VERSION 5.8 ;
BUSBITCHARS "[]" ;
DIVIDERCHAR "/" ;
UNITS
    DATABASE MICRONS 1000 ;
END UNITS

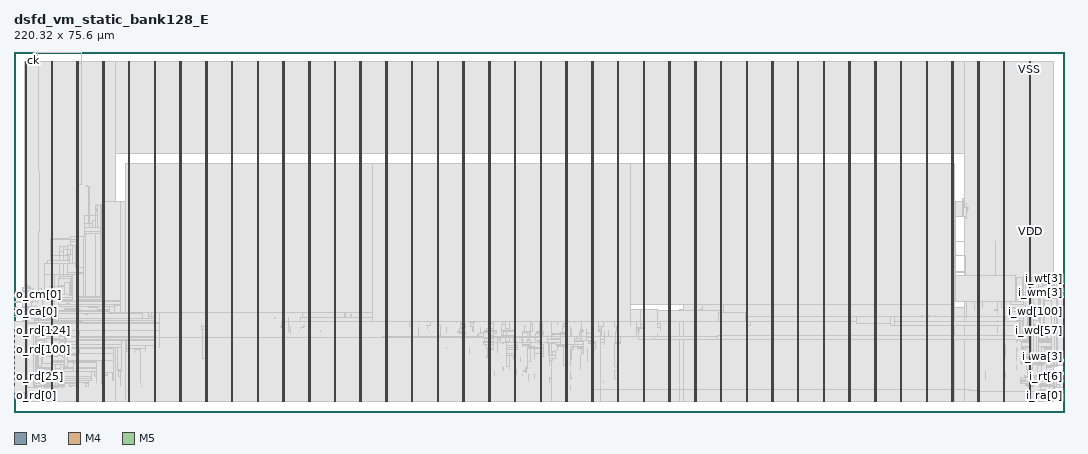
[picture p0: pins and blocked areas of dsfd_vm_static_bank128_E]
MACRO dsfd_vm_static_bank128_E
  FOREIGN dsfd_vm_static_bank128_E 0 0 ;
  CLASS BLOCK ;
  SIZE 220.32 BY 75.6 ;
  PIN ck
    DIRECTION INPUT ;
    USE SIGNAL ;
    PORT
      LAYER M3 ;
        RECT  4.032 75.562 4.05 75.6 ;
    END
  END ck
  PIN i_ra[0]
    DIRECTION INPUT ;
    USE SIGNAL ;
    PORT
      LAYER M4 ;
        RECT  220.236 5.088 220.32 5.112 ;
    END
  END i_ra[0]
  PIN i_ra[1]
    DIRECTION INPUT ;
    USE SIGNAL ;
    PORT
      LAYER M4 ;
        RECT  220.236 5.184 220.32 5.208 ;
    END
  END i_ra[1]
  PIN i_ra[2]
    DIRECTION INPUT ;
    USE SIGNAL ;
    PORT
      LAYER M4 ;
        RECT  220.236 5.28 220.32 5.304 ;
    END
  END i_ra[2]
  PIN i_ra[3]
    DIRECTION INPUT ;
    USE SIGNAL ;
    PORT
      LAYER M4 ;
        RECT  220.236 5.376 220.32 5.4 ;
    END
  END i_ra[3]
  PIN i_ra[4]
    DIRECTION INPUT ;
    USE SIGNAL ;
    PORT
      LAYER M4 ;
        RECT  220.236 5.472 220.32 5.496 ;
    END
  END i_ra[4]
  PIN i_ra[5]
    DIRECTION INPUT ;
    USE SIGNAL ;
    PORT
      LAYER M4 ;
        RECT  220.236 5.568 220.32 5.592 ;
    END
  END i_ra[5]
  PIN i_ra[6]
    DIRECTION INPUT ;
    USE SIGNAL ;
    PORT
      LAYER M4 ;
        RECT  220.236 5.664 220.32 5.688 ;
    END
  END i_ra[6]
  PIN i_ra[7]
    DIRECTION INPUT ;
    USE SIGNAL ;
    PORT
      LAYER M4 ;
        RECT  220.236 5.76 220.32 5.784 ;
    END
  END i_ra[7]
  PIN i_ra[8]
    DIRECTION INPUT ;
    USE SIGNAL ;
    PORT
      LAYER M4 ;
        RECT  220.236 5.856 220.32 5.88 ;
    END
  END i_ra[8]
  PIN i_rt[0]
    DIRECTION INPUT ;
    USE SIGNAL ;
    PORT
      LAYER M4 ;
        RECT  220.236 6.912 220.32 6.936 ;
    END
  END i_rt[0]
  PIN i_rt[1]
    DIRECTION INPUT ;
    USE SIGNAL ;
    PORT
      LAYER M4 ;
        RECT  220.236 7.008 220.32 7.032 ;
    END
  END i_rt[1]
  PIN i_rt[2]
    DIRECTION INPUT ;
    USE SIGNAL ;
    PORT
      LAYER M4 ;
        RECT  220.236 7.104 220.32 7.128 ;
    END
  END i_rt[2]
  PIN i_rt[3]
    DIRECTION INPUT ;
    USE SIGNAL ;
    PORT
      LAYER M4 ;
        RECT  220.236 7.2 220.32 7.224 ;
    END
  END i_rt[3]
  PIN i_rt[4]
    DIRECTION INPUT ;
    USE SIGNAL ;
    PORT
      LAYER M4 ;
        RECT  220.236 7.296 220.32 7.32 ;
    END
  END i_rt[4]
  PIN i_rt[5]
    DIRECTION INPUT ;
    USE SIGNAL ;
    PORT
      LAYER M4 ;
        RECT  220.236 7.392 220.32 7.416 ;
    END
  END i_rt[5]
  PIN i_rt[6]
    DIRECTION INPUT ;
    USE SIGNAL ;
    PORT
      LAYER M4 ;
        RECT  220.236 7.488 220.32 7.512 ;
    END
  END i_rt[6]
  PIN i_rt[7]
    DIRECTION INPUT ;
    USE SIGNAL ;
    PORT
      LAYER M4 ;
        RECT  220.236 7.584 220.32 7.608 ;
    END
  END i_rt[7]
  PIN i_rv
    DIRECTION INPUT ;
    USE SIGNAL ;
    PORT
      LAYER M4 ;
        RECT  220.236 4.032 220.32 4.056 ;
    END
  END i_rv
  PIN i_wa[0]
    DIRECTION INPUT ;
    USE SIGNAL ;
    PORT
      LAYER M4 ;
        RECT  220.236 9.696 220.32 9.72 ;
    END
  END i_wa[0]
  PIN i_wa[1]
    DIRECTION INPUT ;
    USE SIGNAL ;
    PORT
      LAYER M4 ;
        RECT  220.236 9.792 220.32 9.816 ;
    END
  END i_wa[1]
  PIN i_wa[2]
    DIRECTION INPUT ;
    USE SIGNAL ;
    PORT
      LAYER M4 ;
        RECT  220.236 9.888 220.32 9.912 ;
    END
  END i_wa[2]
  PIN i_wa[3]
    DIRECTION INPUT ;
    USE SIGNAL ;
    PORT
      LAYER M4 ;
        RECT  220.236 9.984 220.32 10.008 ;
    END
  END i_wa[3]
  PIN i_wa[4]
    DIRECTION INPUT ;
    USE SIGNAL ;
    PORT
      LAYER M4 ;
        RECT  220.236 10.08 220.32 10.104 ;
    END
  END i_wa[4]
  PIN i_wa[5]
    DIRECTION INPUT ;
    USE SIGNAL ;
    PORT
      LAYER M4 ;
        RECT  220.236 10.176 220.32 10.2 ;
    END
  END i_wa[5]
  PIN i_wa[6]
    DIRECTION INPUT ;
    USE SIGNAL ;
    PORT
      LAYER M4 ;
        RECT  220.236 10.272 220.32 10.296 ;
    END
  END i_wa[6]
  PIN i_wa[7]
    DIRECTION INPUT ;
    USE SIGNAL ;
    PORT
      LAYER M4 ;
        RECT  220.236 10.368 220.32 10.392 ;
    END
  END i_wa[7]
  PIN i_wa[8]
    DIRECTION INPUT ;
    USE SIGNAL ;
    PORT
      LAYER M4 ;
        RECT  220.236 10.464 220.32 10.488 ;
    END
  END i_wa[8]
  PIN i_wd[0]
    DIRECTION INPUT ;
    USE SIGNAL ;
    PORT
      LAYER M4 ;
        RECT  220.236 11.52 220.32 11.544 ;
    END
  END i_wd[0]
  PIN i_wd[100]
    DIRECTION INPUT ;
    USE SIGNAL ;
    PORT
      LAYER M4 ;
        RECT  220.236 21.12 220.32 21.144 ;
    END
  END i_wd[100]
  PIN i_wd[101]
    DIRECTION INPUT ;
    USE SIGNAL ;
    PORT
      LAYER M4 ;
        RECT  220.236 21.216 220.32 21.24 ;
    END
  END i_wd[101]
  PIN i_wd[102]
    DIRECTION INPUT ;
    USE SIGNAL ;
    PORT
      LAYER M4 ;
        RECT  220.236 21.312 220.32 21.336 ;
    END
  END i_wd[102]
  PIN i_wd[103]
    DIRECTION INPUT ;
    USE SIGNAL ;
    PORT
      LAYER M4 ;
        RECT  220.236 21.408 220.32 21.432 ;
    END
  END i_wd[103]
  PIN i_wd[104]
    DIRECTION INPUT ;
    USE SIGNAL ;
    PORT
      LAYER M4 ;
        RECT  220.236 21.504 220.32 21.528 ;
    END
  END i_wd[104]
  PIN i_wd[105]
    DIRECTION INPUT ;
    USE SIGNAL ;
    PORT
      LAYER M4 ;
        RECT  220.236 21.6 220.32 21.624 ;
    END
  END i_wd[105]
  PIN i_wd[106]
    DIRECTION INPUT ;
    USE SIGNAL ;
    PORT
      LAYER M4 ;
        RECT  220.236 21.696 220.32 21.72 ;
    END
  END i_wd[106]
  PIN i_wd[107]
    DIRECTION INPUT ;
    USE SIGNAL ;
    PORT
      LAYER M4 ;
        RECT  220.236 21.792 220.32 21.816 ;
    END
  END i_wd[107]
  PIN i_wd[108]
    DIRECTION INPUT ;
    USE SIGNAL ;
    PORT
      LAYER M4 ;
        RECT  220.236 21.888 220.32 21.912 ;
    END
  END i_wd[108]
  PIN i_wd[109]
    DIRECTION INPUT ;
    USE SIGNAL ;
    PORT
      LAYER M4 ;
        RECT  220.236 21.984 220.32 22.008 ;
    END
  END i_wd[109]
  PIN i_wd[10]
    DIRECTION INPUT ;
    USE SIGNAL ;
    PORT
      LAYER M4 ;
        RECT  220.236 12.48 220.32 12.504 ;
    END
  END i_wd[10]
  PIN i_wd[110]
    DIRECTION INPUT ;
    USE SIGNAL ;
    PORT
      LAYER M4 ;
        RECT  220.236 22.08 220.32 22.104 ;
    END
  END i_wd[110]
  PIN i_wd[111]
    DIRECTION INPUT ;
    USE SIGNAL ;
    PORT
      LAYER M4 ;
        RECT  220.236 22.176 220.32 22.2 ;
    END
  END i_wd[111]
  PIN i_wd[112]
    DIRECTION INPUT ;
    USE SIGNAL ;
    PORT
      LAYER M4 ;
        RECT  220.236 22.272 220.32 22.296 ;
    END
  END i_wd[112]
  PIN i_wd[113]
    DIRECTION INPUT ;
    USE SIGNAL ;
    PORT
      LAYER M4 ;
        RECT  220.236 22.368 220.32 22.392 ;
    END
  END i_wd[113]
  PIN i_wd[114]
    DIRECTION INPUT ;
    USE SIGNAL ;
    PORT
      LAYER M4 ;
        RECT  220.236 22.464 220.32 22.488 ;
    END
  END i_wd[114]
  PIN i_wd[115]
    DIRECTION INPUT ;
    USE SIGNAL ;
    PORT
      LAYER M4 ;
        RECT  220.236 22.56 220.32 22.584 ;
    END
  END i_wd[115]
  PIN i_wd[116]
    DIRECTION INPUT ;
    USE SIGNAL ;
    PORT
      LAYER M4 ;
        RECT  220.236 22.656 220.32 22.68 ;
    END
  END i_wd[116]
  PIN i_wd[117]
    DIRECTION INPUT ;
    USE SIGNAL ;
    PORT
      LAYER M4 ;
        RECT  220.236 22.752 220.32 22.776 ;
    END
  END i_wd[117]
  PIN i_wd[118]
    DIRECTION INPUT ;
    USE SIGNAL ;
    PORT
      LAYER M4 ;
        RECT  220.236 22.848 220.32 22.872 ;
    END
  END i_wd[118]
  PIN i_wd[119]
    DIRECTION INPUT ;
    USE SIGNAL ;
    PORT
      LAYER M4 ;
        RECT  220.236 22.944 220.32 22.968 ;
    END
  END i_wd[119]
  PIN i_wd[11]
    DIRECTION INPUT ;
    USE SIGNAL ;
    PORT
      LAYER M4 ;
        RECT  220.236 12.576 220.32 12.6 ;
    END
  END i_wd[11]
  PIN i_wd[120]
    DIRECTION INPUT ;
    USE SIGNAL ;
    PORT
      LAYER M4 ;
        RECT  220.236 23.04 220.32 23.064 ;
    END
  END i_wd[120]
  PIN i_wd[121]
    DIRECTION INPUT ;
    USE SIGNAL ;
    PORT
      LAYER M4 ;
        RECT  220.236 23.136 220.32 23.16 ;
    END
  END i_wd[121]
  PIN i_wd[122]
    DIRECTION INPUT ;
    USE SIGNAL ;
    PORT
      LAYER M4 ;
        RECT  220.236 23.232 220.32 23.256 ;
    END
  END i_wd[122]
  PIN i_wd[123]
    DIRECTION INPUT ;
    USE SIGNAL ;
    PORT
      LAYER M4 ;
        RECT  220.236 23.328 220.32 23.352 ;
    END
  END i_wd[123]
  PIN i_wd[124]
    DIRECTION INPUT ;
    USE SIGNAL ;
    PORT
      LAYER M4 ;
        RECT  220.236 23.424 220.32 23.448 ;
    END
  END i_wd[124]
  PIN i_wd[125]
    DIRECTION INPUT ;
    USE SIGNAL ;
    PORT
      LAYER M4 ;
        RECT  220.236 23.52 220.32 23.544 ;
    END
  END i_wd[125]
  PIN i_wd[126]
    DIRECTION INPUT ;
    USE SIGNAL ;
    PORT
      LAYER M4 ;
        RECT  220.236 23.616 220.32 23.64 ;
    END
  END i_wd[126]
  PIN i_wd[127]
    DIRECTION INPUT ;
    USE SIGNAL ;
    PORT
      LAYER M4 ;
        RECT  220.236 23.712 220.32 23.736 ;
    END
  END i_wd[127]
  PIN i_wd[12]
    DIRECTION INPUT ;
    USE SIGNAL ;
    PORT
      LAYER M4 ;
        RECT  220.236 12.672 220.32 12.696 ;
    END
  END i_wd[12]
  PIN i_wd[13]
    DIRECTION INPUT ;
    USE SIGNAL ;
    PORT
      LAYER M4 ;
        RECT  220.236 12.768 220.32 12.792 ;
    END
  END i_wd[13]
  PIN i_wd[14]
    DIRECTION INPUT ;
    USE SIGNAL ;
    PORT
      LAYER M4 ;
        RECT  220.236 12.864 220.32 12.888 ;
    END
  END i_wd[14]
  PIN i_wd[15]
    DIRECTION INPUT ;
    USE SIGNAL ;
    PORT
      LAYER M4 ;
        RECT  220.236 12.96 220.32 12.984 ;
    END
  END i_wd[15]
  PIN i_wd[16]
    DIRECTION INPUT ;
    USE SIGNAL ;
    PORT
      LAYER M4 ;
        RECT  220.236 13.056 220.32 13.08 ;
    END
  END i_wd[16]
  PIN i_wd[17]
    DIRECTION INPUT ;
    USE SIGNAL ;
    PORT
      LAYER M4 ;
        RECT  220.236 13.152 220.32 13.176 ;
    END
  END i_wd[17]
  PIN i_wd[18]
    DIRECTION INPUT ;
    USE SIGNAL ;
    PORT
      LAYER M4 ;
        RECT  220.236 13.248 220.32 13.272 ;
    END
  END i_wd[18]
  PIN i_wd[19]
    DIRECTION INPUT ;
    USE SIGNAL ;
    PORT
      LAYER M4 ;
        RECT  220.236 13.344 220.32 13.368 ;
    END
  END i_wd[19]
  PIN i_wd[1]
    DIRECTION INPUT ;
    USE SIGNAL ;
    PORT
      LAYER M4 ;
        RECT  220.236 11.616 220.32 11.64 ;
    END
  END i_wd[1]
  PIN i_wd[20]
    DIRECTION INPUT ;
    USE SIGNAL ;
    PORT
      LAYER M4 ;
        RECT  220.236 13.44 220.32 13.464 ;
    END
  END i_wd[20]
  PIN i_wd[21]
    DIRECTION INPUT ;
    USE SIGNAL ;
    PORT
      LAYER M4 ;
        RECT  220.236 13.536 220.32 13.56 ;
    END
  END i_wd[21]
  PIN i_wd[22]
    DIRECTION INPUT ;
    USE SIGNAL ;
    PORT
      LAYER M4 ;
        RECT  220.236 13.632 220.32 13.656 ;
    END
  END i_wd[22]
  PIN i_wd[23]
    DIRECTION INPUT ;
    USE SIGNAL ;
    PORT
      LAYER M4 ;
        RECT  220.236 13.728 220.32 13.752 ;
    END
  END i_wd[23]
  PIN i_wd[24]
    DIRECTION INPUT ;
    USE SIGNAL ;
    PORT
      LAYER M4 ;
        RECT  220.236 13.824 220.32 13.848 ;
    END
  END i_wd[24]
  PIN i_wd[25]
    DIRECTION INPUT ;
    USE SIGNAL ;
    PORT
      LAYER M4 ;
        RECT  220.236 13.92 220.32 13.944 ;
    END
  END i_wd[25]
  PIN i_wd[26]
    DIRECTION INPUT ;
    USE SIGNAL ;
    PORT
      LAYER M4 ;
        RECT  220.236 14.016 220.32 14.04 ;
    END
  END i_wd[26]
  PIN i_wd[27]
    DIRECTION INPUT ;
    USE SIGNAL ;
    PORT
      LAYER M4 ;
        RECT  220.236 14.112 220.32 14.136 ;
    END
  END i_wd[27]
  PIN i_wd[28]
    DIRECTION INPUT ;
    USE SIGNAL ;
    PORT
      LAYER M4 ;
        RECT  220.236 14.208 220.32 14.232 ;
    END
  END i_wd[28]
  PIN i_wd[29]
    DIRECTION INPUT ;
    USE SIGNAL ;
    PORT
      LAYER M4 ;
        RECT  220.236 14.304 220.32 14.328 ;
    END
  END i_wd[29]
  PIN i_wd[2]
    DIRECTION INPUT ;
    USE SIGNAL ;
    PORT
      LAYER M4 ;
        RECT  220.236 11.712 220.32 11.736 ;
    END
  END i_wd[2]
  PIN i_wd[30]
    DIRECTION INPUT ;
    USE SIGNAL ;
    PORT
      LAYER M4 ;
        RECT  220.236 14.4 220.32 14.424 ;
    END
  END i_wd[30]
  PIN i_wd[31]
    DIRECTION INPUT ;
    USE SIGNAL ;
    PORT
      LAYER M4 ;
        RECT  220.236 14.496 220.32 14.52 ;
    END
  END i_wd[31]
  PIN i_wd[32]
    DIRECTION INPUT ;
    USE SIGNAL ;
    PORT
      LAYER M4 ;
        RECT  220.236 14.592 220.32 14.616 ;
    END
  END i_wd[32]
  PIN i_wd[33]
    DIRECTION INPUT ;
    USE SIGNAL ;
    PORT
      LAYER M4 ;
        RECT  220.236 14.688 220.32 14.712 ;
    END
  END i_wd[33]
  PIN i_wd[34]
    DIRECTION INPUT ;
    USE SIGNAL ;
    PORT
      LAYER M4 ;
        RECT  220.236 14.784 220.32 14.808 ;
    END
  END i_wd[34]
  PIN i_wd[35]
    DIRECTION INPUT ;
    USE SIGNAL ;
    PORT
      LAYER M4 ;
        RECT  220.236 14.88 220.32 14.904 ;
    END
  END i_wd[35]
  PIN i_wd[36]
    DIRECTION INPUT ;
    USE SIGNAL ;
    PORT
      LAYER M4 ;
        RECT  220.236 14.976 220.32 15 ;
    END
  END i_wd[36]
  PIN i_wd[37]
    DIRECTION INPUT ;
    USE SIGNAL ;
    PORT
      LAYER M4 ;
        RECT  220.236 15.072 220.32 15.096 ;
    END
  END i_wd[37]
  PIN i_wd[38]
    DIRECTION INPUT ;
    USE SIGNAL ;
    PORT
      LAYER M4 ;
        RECT  220.236 15.168 220.32 15.192 ;
    END
  END i_wd[38]
  PIN i_wd[39]
    DIRECTION INPUT ;
    USE SIGNAL ;
    PORT
      LAYER M4 ;
        RECT  220.236 15.264 220.32 15.288 ;
    END
  END i_wd[39]
  PIN i_wd[3]
    DIRECTION INPUT ;
    USE SIGNAL ;
    PORT
      LAYER M4 ;
        RECT  220.236 11.808 220.32 11.832 ;
    END
  END i_wd[3]
  PIN i_wd[40]
    DIRECTION INPUT ;
    USE SIGNAL ;
    PORT
      LAYER M4 ;
        RECT  220.236 15.36 220.32 15.384 ;
    END
  END i_wd[40]
  PIN i_wd[41]
    DIRECTION INPUT ;
    USE SIGNAL ;
    PORT
      LAYER M4 ;
        RECT  220.236 15.456 220.32 15.48 ;
    END
  END i_wd[41]
  PIN i_wd[42]
    DIRECTION INPUT ;
    USE SIGNAL ;
    PORT
      LAYER M4 ;
        RECT  220.236 15.552 220.32 15.576 ;
    END
  END i_wd[42]
  PIN i_wd[43]
    DIRECTION INPUT ;
    USE SIGNAL ;
    PORT
      LAYER M4 ;
        RECT  220.236 15.648 220.32 15.672 ;
    END
  END i_wd[43]
  PIN i_wd[44]
    DIRECTION INPUT ;
    USE SIGNAL ;
    PORT
      LAYER M4 ;
        RECT  220.236 15.744 220.32 15.768 ;
    END
  END i_wd[44]
  PIN i_wd[45]
    DIRECTION INPUT ;
    USE SIGNAL ;
    PORT
      LAYER M4 ;
        RECT  220.236 15.84 220.32 15.864 ;
    END
  END i_wd[45]
  PIN i_wd[46]
    DIRECTION INPUT ;
    USE SIGNAL ;
    PORT
      LAYER M4 ;
        RECT  220.236 15.936 220.32 15.96 ;
    END
  END i_wd[46]
  PIN i_wd[47]
    DIRECTION INPUT ;
    USE SIGNAL ;
    PORT
      LAYER M4 ;
        RECT  220.236 16.032 220.32 16.056 ;
    END
  END i_wd[47]
  PIN i_wd[48]
    DIRECTION INPUT ;
    USE SIGNAL ;
    PORT
      LAYER M4 ;
        RECT  220.236 16.128 220.32 16.152 ;
    END
  END i_wd[48]
  PIN i_wd[49]
    DIRECTION INPUT ;
    USE SIGNAL ;
    PORT
      LAYER M4 ;
        RECT  220.236 16.224 220.32 16.248 ;
    END
  END i_wd[49]
  PIN i_wd[4]
    DIRECTION INPUT ;
    USE SIGNAL ;
    PORT
      LAYER M4 ;
        RECT  220.236 11.904 220.32 11.928 ;
    END
  END i_wd[4]
  PIN i_wd[50]
    DIRECTION INPUT ;
    USE SIGNAL ;
    PORT
      LAYER M4 ;
        RECT  220.236 16.32 220.32 16.344 ;
    END
  END i_wd[50]
  PIN i_wd[51]
    DIRECTION INPUT ;
    USE SIGNAL ;
    PORT
      LAYER M4 ;
        RECT  220.236 16.416 220.32 16.44 ;
    END
  END i_wd[51]
  PIN i_wd[52]
    DIRECTION INPUT ;
    USE SIGNAL ;
    PORT
      LAYER M4 ;
        RECT  220.236 16.512 220.32 16.536 ;
    END
  END i_wd[52]
  PIN i_wd[53]
    DIRECTION INPUT ;
    USE SIGNAL ;
    PORT
      LAYER M4 ;
        RECT  220.236 16.608 220.32 16.632 ;
    END
  END i_wd[53]
  PIN i_wd[54]
    DIRECTION INPUT ;
    USE SIGNAL ;
    PORT
      LAYER M4 ;
        RECT  220.236 16.704 220.32 16.728 ;
    END
  END i_wd[54]
  PIN i_wd[55]
    DIRECTION INPUT ;
    USE SIGNAL ;
    PORT
      LAYER M4 ;
        RECT  220.236 16.8 220.32 16.824 ;
    END
  END i_wd[55]
  PIN i_wd[56]
    DIRECTION INPUT ;
    USE SIGNAL ;
    PORT
      LAYER M4 ;
        RECT  220.236 16.896 220.32 16.92 ;
    END
  END i_wd[56]
  PIN i_wd[57]
    DIRECTION INPUT ;
    USE SIGNAL ;
    PORT
      LAYER M4 ;
        RECT  220.236 16.992 220.32 17.016 ;
    END
  END i_wd[57]
  PIN i_wd[58]
    DIRECTION INPUT ;
    USE SIGNAL ;
    PORT
      LAYER M4 ;
        RECT  220.236 17.088 220.32 17.112 ;
    END
  END i_wd[58]
  PIN i_wd[59]
    DIRECTION INPUT ;
    USE SIGNAL ;
    PORT
      LAYER M4 ;
        RECT  220.236 17.184 220.32 17.208 ;
    END
  END i_wd[59]
  PIN i_wd[5]
    DIRECTION INPUT ;
    USE SIGNAL ;
    PORT
      LAYER M4 ;
        RECT  220.236 12 220.32 12.024 ;
    END
  END i_wd[5]
  PIN i_wd[60]
    DIRECTION INPUT ;
    USE SIGNAL ;
    PORT
      LAYER M4 ;
        RECT  220.236 17.28 220.32 17.304 ;
    END
  END i_wd[60]
  PIN i_wd[61]
    DIRECTION INPUT ;
    USE SIGNAL ;
    PORT
      LAYER M4 ;
        RECT  220.236 17.376 220.32 17.4 ;
    END
  END i_wd[61]
  PIN i_wd[62]
    DIRECTION INPUT ;
    USE SIGNAL ;
    PORT
      LAYER M4 ;
        RECT  220.236 17.472 220.32 17.496 ;
    END
  END i_wd[62]
  PIN i_wd[63]
    DIRECTION INPUT ;
    USE SIGNAL ;
    PORT
      LAYER M4 ;
        RECT  220.236 17.568 220.32 17.592 ;
    END
  END i_wd[63]
  PIN i_wd[64]
    DIRECTION INPUT ;
    USE SIGNAL ;
    PORT
      LAYER M4 ;
        RECT  220.236 17.664 220.32 17.688 ;
    END
  END i_wd[64]
  PIN i_wd[65]
    DIRECTION INPUT ;
    USE SIGNAL ;
    PORT
      LAYER M4 ;
        RECT  220.236 17.76 220.32 17.784 ;
    END
  END i_wd[65]
  PIN i_wd[66]
    DIRECTION INPUT ;
    USE SIGNAL ;
    PORT
      LAYER M4 ;
        RECT  220.236 17.856 220.32 17.88 ;
    END
  END i_wd[66]
  PIN i_wd[67]
    DIRECTION INPUT ;
    USE SIGNAL ;
    PORT
      LAYER M4 ;
        RECT  220.236 17.952 220.32 17.976 ;
    END
  END i_wd[67]
  PIN i_wd[68]
    DIRECTION INPUT ;
    USE SIGNAL ;
    PORT
      LAYER M4 ;
        RECT  220.236 18.048 220.32 18.072 ;
    END
  END i_wd[68]
  PIN i_wd[69]
    DIRECTION INPUT ;
    USE SIGNAL ;
    PORT
      LAYER M4 ;
        RECT  220.236 18.144 220.32 18.168 ;
    END
  END i_wd[69]
  PIN i_wd[6]
    DIRECTION INPUT ;
    USE SIGNAL ;
    PORT
      LAYER M4 ;
        RECT  220.236 12.096 220.32 12.12 ;
    END
  END i_wd[6]
  PIN i_wd[70]
    DIRECTION INPUT ;
    USE SIGNAL ;
    PORT
      LAYER M4 ;
        RECT  220.236 18.24 220.32 18.264 ;
    END
  END i_wd[70]
  PIN i_wd[71]
    DIRECTION INPUT ;
    USE SIGNAL ;
    PORT
      LAYER M4 ;
        RECT  220.236 18.336 220.32 18.36 ;
    END
  END i_wd[71]
  PIN i_wd[72]
    DIRECTION INPUT ;
    USE SIGNAL ;
    PORT
      LAYER M4 ;
        RECT  220.236 18.432 220.32 18.456 ;
    END
  END i_wd[72]
  PIN i_wd[73]
    DIRECTION INPUT ;
    USE SIGNAL ;
    PORT
      LAYER M4 ;
        RECT  220.236 18.528 220.32 18.552 ;
    END
  END i_wd[73]
  PIN i_wd[74]
    DIRECTION INPUT ;
    USE SIGNAL ;
    PORT
      LAYER M4 ;
        RECT  220.236 18.624 220.32 18.648 ;
    END
  END i_wd[74]
  PIN i_wd[75]
    DIRECTION INPUT ;
    USE SIGNAL ;
    PORT
      LAYER M4 ;
        RECT  220.236 18.72 220.32 18.744 ;
    END
  END i_wd[75]
  PIN i_wd[76]
    DIRECTION INPUT ;
    USE SIGNAL ;
    PORT
      LAYER M4 ;
        RECT  220.236 18.816 220.32 18.84 ;
    END
  END i_wd[76]
  PIN i_wd[77]
    DIRECTION INPUT ;
    USE SIGNAL ;
    PORT
      LAYER M4 ;
        RECT  220.236 18.912 220.32 18.936 ;
    END
  END i_wd[77]
  PIN i_wd[78]
    DIRECTION INPUT ;
    USE SIGNAL ;
    PORT
      LAYER M4 ;
        RECT  220.236 19.008 220.32 19.032 ;
    END
  END i_wd[78]
  PIN i_wd[79]
    DIRECTION INPUT ;
    USE SIGNAL ;
    PORT
      LAYER M4 ;
        RECT  220.236 19.104 220.32 19.128 ;
    END
  END i_wd[79]
  PIN i_wd[7]
    DIRECTION INPUT ;
    USE SIGNAL ;
    PORT
      LAYER M4 ;
        RECT  220.236 12.192 220.32 12.216 ;
    END
  END i_wd[7]
  PIN i_wd[80]
    DIRECTION INPUT ;
    USE SIGNAL ;
    PORT
      LAYER M4 ;
        RECT  220.236 19.2 220.32 19.224 ;
    END
  END i_wd[80]
  PIN i_wd[81]
    DIRECTION INPUT ;
    USE SIGNAL ;
    PORT
      LAYER M4 ;
        RECT  220.236 19.296 220.32 19.32 ;
    END
  END i_wd[81]
  PIN i_wd[82]
    DIRECTION INPUT ;
    USE SIGNAL ;
    PORT
      LAYER M4 ;
        RECT  220.236 19.392 220.32 19.416 ;
    END
  END i_wd[82]
  PIN i_wd[83]
    DIRECTION INPUT ;
    USE SIGNAL ;
    PORT
      LAYER M4 ;
        RECT  220.236 19.488 220.32 19.512 ;
    END
  END i_wd[83]
  PIN i_wd[84]
    DIRECTION INPUT ;
    USE SIGNAL ;
    PORT
      LAYER M4 ;
        RECT  220.236 19.584 220.32 19.608 ;
    END
  END i_wd[84]
  PIN i_wd[85]
    DIRECTION INPUT ;
    USE SIGNAL ;
    PORT
      LAYER M4 ;
        RECT  220.236 19.68 220.32 19.704 ;
    END
  END i_wd[85]
  PIN i_wd[86]
    DIRECTION INPUT ;
    USE SIGNAL ;
    PORT
      LAYER M4 ;
        RECT  220.236 19.776 220.32 19.8 ;
    END
  END i_wd[86]
  PIN i_wd[87]
    DIRECTION INPUT ;
    USE SIGNAL ;
    PORT
      LAYER M4 ;
        RECT  220.236 19.872 220.32 19.896 ;
    END
  END i_wd[87]
  PIN i_wd[88]
    DIRECTION INPUT ;
    USE SIGNAL ;
    PORT
      LAYER M4 ;
        RECT  220.236 19.968 220.32 19.992 ;
    END
  END i_wd[88]
  PIN i_wd[89]
    DIRECTION INPUT ;
    USE SIGNAL ;
    PORT
      LAYER M4 ;
        RECT  220.236 20.064 220.32 20.088 ;
    END
  END i_wd[89]
  PIN i_wd[8]
    DIRECTION INPUT ;
    USE SIGNAL ;
    PORT
      LAYER M4 ;
        RECT  220.236 12.288 220.32 12.312 ;
    END
  END i_wd[8]
  PIN i_wd[90]
    DIRECTION INPUT ;
    USE SIGNAL ;
    PORT
      LAYER M4 ;
        RECT  220.236 20.16 220.32 20.184 ;
    END
  END i_wd[90]
  PIN i_wd[91]
    DIRECTION INPUT ;
    USE SIGNAL ;
    PORT
      LAYER M4 ;
        RECT  220.236 20.256 220.32 20.28 ;
    END
  END i_wd[91]
  PIN i_wd[92]
    DIRECTION INPUT ;
    USE SIGNAL ;
    PORT
      LAYER M4 ;
        RECT  220.236 20.352 220.32 20.376 ;
    END
  END i_wd[92]
  PIN i_wd[93]
    DIRECTION INPUT ;
    USE SIGNAL ;
    PORT
      LAYER M4 ;
        RECT  220.236 20.448 220.32 20.472 ;
    END
  END i_wd[93]
  PIN i_wd[94]
    DIRECTION INPUT ;
    USE SIGNAL ;
    PORT
      LAYER M4 ;
        RECT  220.236 20.544 220.32 20.568 ;
    END
  END i_wd[94]
  PIN i_wd[95]
    DIRECTION INPUT ;
    USE SIGNAL ;
    PORT
      LAYER M4 ;
        RECT  220.236 20.64 220.32 20.664 ;
    END
  END i_wd[95]
  PIN i_wd[96]
    DIRECTION INPUT ;
    USE SIGNAL ;
    PORT
      LAYER M4 ;
        RECT  220.236 20.736 220.32 20.76 ;
    END
  END i_wd[96]
  PIN i_wd[97]
    DIRECTION INPUT ;
    USE SIGNAL ;
    PORT
      LAYER M4 ;
        RECT  220.236 20.832 220.32 20.856 ;
    END
  END i_wd[97]
  PIN i_wd[98]
    DIRECTION INPUT ;
    USE SIGNAL ;
    PORT
      LAYER M4 ;
        RECT  220.236 20.928 220.32 20.952 ;
    END
  END i_wd[98]
  PIN i_wd[99]
    DIRECTION INPUT ;
    USE SIGNAL ;
    PORT
      LAYER M4 ;
        RECT  220.236 21.024 220.32 21.048 ;
    END
  END i_wd[99]
  PIN i_wd[9]
    DIRECTION INPUT ;
    USE SIGNAL ;
    PORT
      LAYER M4 ;
        RECT  220.236 12.384 220.32 12.408 ;
    END
  END i_wd[9]
  PIN i_wm[0]
    DIRECTION INPUT ;
    USE SIGNAL ;
    PORT
      LAYER M4 ;
        RECT  220.236 24.768 220.32 24.792 ;
    END
  END i_wm[0]
  PIN i_wm[1]
    DIRECTION INPUT ;
    USE SIGNAL ;
    PORT
      LAYER M4 ;
        RECT  220.236 24.864 220.32 24.888 ;
    END
  END i_wm[1]
  PIN i_wm[2]
    DIRECTION INPUT ;
    USE SIGNAL ;
    PORT
      LAYER M4 ;
        RECT  220.236 24.96 220.32 24.984 ;
    END
  END i_wm[2]
  PIN i_wm[3]
    DIRECTION INPUT ;
    USE SIGNAL ;
    PORT
      LAYER M4 ;
        RECT  220.236 25.056 220.32 25.08 ;
    END
  END i_wm[3]
  PIN i_wt[0]
    DIRECTION INPUT ;
    USE SIGNAL ;
    PORT
      LAYER M4 ;
        RECT  220.236 26.112 220.32 26.136 ;
    END
  END i_wt[0]
  PIN i_wt[1]
    DIRECTION INPUT ;
    USE SIGNAL ;
    PORT
      LAYER M4 ;
        RECT  220.236 26.208 220.32 26.232 ;
    END
  END i_wt[1]
  PIN i_wt[2]
    DIRECTION INPUT ;
    USE SIGNAL ;
    PORT
      LAYER M4 ;
        RECT  220.236 26.304 220.32 26.328 ;
    END
  END i_wt[2]
  PIN i_wt[3]
    DIRECTION INPUT ;
    USE SIGNAL ;
    PORT
      LAYER M4 ;
        RECT  220.236 26.4 220.32 26.424 ;
    END
  END i_wt[3]
  PIN i_wt[4]
    DIRECTION INPUT ;
    USE SIGNAL ;
    PORT
      LAYER M4 ;
        RECT  220.236 26.496 220.32 26.52 ;
    END
  END i_wt[4]
  PIN i_wt[5]
    DIRECTION INPUT ;
    USE SIGNAL ;
    PORT
      LAYER M4 ;
        RECT  220.236 26.592 220.32 26.616 ;
    END
  END i_wt[5]
  PIN i_wt[6]
    DIRECTION INPUT ;
    USE SIGNAL ;
    PORT
      LAYER M4 ;
        RECT  220.236 26.688 220.32 26.712 ;
    END
  END i_wt[6]
  PIN i_wt[7]
    DIRECTION INPUT ;
    USE SIGNAL ;
    PORT
      LAYER M4 ;
        RECT  220.236 26.784 220.32 26.808 ;
    END
  END i_wt[7]
  PIN i_wv
    DIRECTION INPUT ;
    USE SIGNAL ;
    PORT
      LAYER M4 ;
        RECT  220.236 8.64 220.32 8.664 ;
    END
  END i_wv
  PIN o_ca[0]
    DIRECTION OUTPUT ;
    USE SIGNAL ;
    PORT
      LAYER M4 ;
        RECT  0 21.12 0.084 21.144 ;
    END
  END o_ca[0]
  PIN o_ca[1]
    DIRECTION OUTPUT ;
    USE SIGNAL ;
    PORT
      LAYER M4 ;
        RECT  0 21.216 0.084 21.24 ;
    END
  END o_ca[1]
  PIN o_ca[2]
    DIRECTION OUTPUT ;
    USE SIGNAL ;
    PORT
      LAYER M4 ;
        RECT  0 21.312 0.084 21.336 ;
    END
  END o_ca[2]
  PIN o_ca[3]
    DIRECTION OUTPUT ;
    USE SIGNAL ;
    PORT
      LAYER M4 ;
        RECT  0 21.408 0.084 21.432 ;
    END
  END o_ca[3]
  PIN o_ca[4]
    DIRECTION OUTPUT ;
    USE SIGNAL ;
    PORT
      LAYER M4 ;
        RECT  0 21.504 0.084 21.528 ;
    END
  END o_ca[4]
  PIN o_ca[5]
    DIRECTION OUTPUT ;
    USE SIGNAL ;
    PORT
      LAYER M4 ;
        RECT  0 21.6 0.084 21.624 ;
    END
  END o_ca[5]
  PIN o_ca[6]
    DIRECTION OUTPUT ;
    USE SIGNAL ;
    PORT
      LAYER M4 ;
        RECT  0 21.696 0.084 21.72 ;
    END
  END o_ca[6]
  PIN o_ca[7]
    DIRECTION OUTPUT ;
    USE SIGNAL ;
    PORT
      LAYER M4 ;
        RECT  0 21.792 0.084 21.816 ;
    END
  END o_ca[7]
  PIN o_ca[8]
    DIRECTION OUTPUT ;
    USE SIGNAL ;
    PORT
      LAYER M4 ;
        RECT  0 21.888 0.084 21.912 ;
    END
  END o_ca[8]
  PIN o_cm[0]
    DIRECTION OUTPUT ;
    USE SIGNAL ;
    PORT
      LAYER M4 ;
        RECT  0 22.944 0.084 22.968 ;
    END
  END o_cm[0]
  PIN o_cm[1]
    DIRECTION OUTPUT ;
    USE SIGNAL ;
    PORT
      LAYER M4 ;
        RECT  0 23.04 0.084 23.064 ;
    END
  END o_cm[1]
  PIN o_cm[2]
    DIRECTION OUTPUT ;
    USE SIGNAL ;
    PORT
      LAYER M4 ;
        RECT  0 23.136 0.084 23.16 ;
    END
  END o_cm[2]
  PIN o_cm[3]
    DIRECTION OUTPUT ;
    USE SIGNAL ;
    PORT
      LAYER M4 ;
        RECT  0 23.232 0.084 23.256 ;
    END
  END o_cm[3]
  PIN o_commit
    DIRECTION OUTPUT ;
    USE SIGNAL ;
    PORT
      LAYER M4 ;
        RECT  0 20.064 0.084 20.088 ;
    END
  END o_commit
  PIN o_ct[0]
    DIRECTION OUTPUT ;
    USE SIGNAL ;
    PORT
      LAYER M4 ;
        RECT  0 24.288 0.084 24.312 ;
    END
  END o_ct[0]
  PIN o_ct[1]
    DIRECTION OUTPUT ;
    USE SIGNAL ;
    PORT
      LAYER M4 ;
        RECT  0 24.384 0.084 24.408 ;
    END
  END o_ct[1]
  PIN o_ct[2]
    DIRECTION OUTPUT ;
    USE SIGNAL ;
    PORT
      LAYER M4 ;
        RECT  0 24.48 0.084 24.504 ;
    END
  END o_ct[2]
  PIN o_ct[3]
    DIRECTION OUTPUT ;
    USE SIGNAL ;
    PORT
      LAYER M4 ;
        RECT  0 24.576 0.084 24.6 ;
    END
  END o_ct[3]
  PIN o_ct[4]
    DIRECTION OUTPUT ;
    USE SIGNAL ;
    PORT
      LAYER M4 ;
        RECT  0 24.672 0.084 24.696 ;
    END
  END o_ct[4]
  PIN o_ct[5]
    DIRECTION OUTPUT ;
    USE SIGNAL ;
    PORT
      LAYER M4 ;
        RECT  0 24.768 0.084 24.792 ;
    END
  END o_ct[5]
  PIN o_ct[6]
    DIRECTION OUTPUT ;
    USE SIGNAL ;
    PORT
      LAYER M4 ;
        RECT  0 24.864 0.084 24.888 ;
    END
  END o_ct[6]
  PIN o_ct[7]
    DIRECTION OUTPUT ;
    USE SIGNAL ;
    PORT
      LAYER M4 ;
        RECT  0 24.96 0.084 24.984 ;
    END
  END o_ct[7]
  PIN o_rd[0]
    DIRECTION OUTPUT ;
    USE SIGNAL ;
    PORT
      LAYER M4 ;
        RECT  0 5.088 0.084 5.112 ;
    END
  END o_rd[0]
  PIN o_rd[100]
    DIRECTION OUTPUT ;
    USE SIGNAL ;
    PORT
      LAYER M4 ;
        RECT  0 14.688 0.084 14.712 ;
    END
  END o_rd[100]
  PIN o_rd[101]
    DIRECTION OUTPUT ;
    USE SIGNAL ;
    PORT
      LAYER M4 ;
        RECT  0 14.784 0.084 14.808 ;
    END
  END o_rd[101]
  PIN o_rd[102]
    DIRECTION OUTPUT ;
    USE SIGNAL ;
    PORT
      LAYER M4 ;
        RECT  0 14.88 0.084 14.904 ;
    END
  END o_rd[102]
  PIN o_rd[103]
    DIRECTION OUTPUT ;
    USE SIGNAL ;
    PORT
      LAYER M4 ;
        RECT  0 14.976 0.084 15 ;
    END
  END o_rd[103]
  PIN o_rd[104]
    DIRECTION OUTPUT ;
    USE SIGNAL ;
    PORT
      LAYER M4 ;
        RECT  0 15.072 0.084 15.096 ;
    END
  END o_rd[104]
  PIN o_rd[105]
    DIRECTION OUTPUT ;
    USE SIGNAL ;
    PORT
      LAYER M4 ;
        RECT  0 15.168 0.084 15.192 ;
    END
  END o_rd[105]
  PIN o_rd[106]
    DIRECTION OUTPUT ;
    USE SIGNAL ;
    PORT
      LAYER M4 ;
        RECT  0 15.264 0.084 15.288 ;
    END
  END o_rd[106]
  PIN o_rd[107]
    DIRECTION OUTPUT ;
    USE SIGNAL ;
    PORT
      LAYER M4 ;
        RECT  0 15.36 0.084 15.384 ;
    END
  END o_rd[107]
  PIN o_rd[108]
    DIRECTION OUTPUT ;
    USE SIGNAL ;
    PORT
      LAYER M4 ;
        RECT  0 15.456 0.084 15.48 ;
    END
  END o_rd[108]
  PIN o_rd[109]
    DIRECTION OUTPUT ;
    USE SIGNAL ;
    PORT
      LAYER M4 ;
        RECT  0 15.552 0.084 15.576 ;
    END
  END o_rd[109]
  PIN o_rd[10]
    DIRECTION OUTPUT ;
    USE SIGNAL ;
    PORT
      LAYER M4 ;
        RECT  0 6.048 0.084 6.072 ;
    END
  END o_rd[10]
  PIN o_rd[110]
    DIRECTION OUTPUT ;
    USE SIGNAL ;
    PORT
      LAYER M4 ;
        RECT  0 15.648 0.084 15.672 ;
    END
  END o_rd[110]
  PIN o_rd[111]
    DIRECTION OUTPUT ;
    USE SIGNAL ;
    PORT
      LAYER M4 ;
        RECT  0 15.744 0.084 15.768 ;
    END
  END o_rd[111]
  PIN o_rd[112]
    DIRECTION OUTPUT ;
    USE SIGNAL ;
    PORT
      LAYER M4 ;
        RECT  0 15.84 0.084 15.864 ;
    END
  END o_rd[112]
  PIN o_rd[113]
    DIRECTION OUTPUT ;
    USE SIGNAL ;
    PORT
      LAYER M4 ;
        RECT  0 15.936 0.084 15.96 ;
    END
  END o_rd[113]
  PIN o_rd[114]
    DIRECTION OUTPUT ;
    USE SIGNAL ;
    PORT
      LAYER M4 ;
        RECT  0 16.032 0.084 16.056 ;
    END
  END o_rd[114]
  PIN o_rd[115]
    DIRECTION OUTPUT ;
    USE SIGNAL ;
    PORT
      LAYER M4 ;
        RECT  0 16.128 0.084 16.152 ;
    END
  END o_rd[115]
  PIN o_rd[116]
    DIRECTION OUTPUT ;
    USE SIGNAL ;
    PORT
      LAYER M4 ;
        RECT  0 16.224 0.084 16.248 ;
    END
  END o_rd[116]
  PIN o_rd[117]
    DIRECTION OUTPUT ;
    USE SIGNAL ;
    PORT
      LAYER M4 ;
        RECT  0 16.32 0.084 16.344 ;
    END
  END o_rd[117]
  PIN o_rd[118]
    DIRECTION OUTPUT ;
    USE SIGNAL ;
    PORT
      LAYER M4 ;
        RECT  0 16.416 0.084 16.44 ;
    END
  END o_rd[118]
  PIN o_rd[119]
    DIRECTION OUTPUT ;
    USE SIGNAL ;
    PORT
      LAYER M4 ;
        RECT  0 16.512 0.084 16.536 ;
    END
  END o_rd[119]
  PIN o_rd[11]
    DIRECTION OUTPUT ;
    USE SIGNAL ;
    PORT
      LAYER M4 ;
        RECT  0 6.144 0.084 6.168 ;
    END
  END o_rd[11]
  PIN o_rd[120]
    DIRECTION OUTPUT ;
    USE SIGNAL ;
    PORT
      LAYER M4 ;
        RECT  0 16.608 0.084 16.632 ;
    END
  END o_rd[120]
  PIN o_rd[121]
    DIRECTION OUTPUT ;
    USE SIGNAL ;
    PORT
      LAYER M4 ;
        RECT  0 16.704 0.084 16.728 ;
    END
  END o_rd[121]
  PIN o_rd[122]
    DIRECTION OUTPUT ;
    USE SIGNAL ;
    PORT
      LAYER M4 ;
        RECT  0 16.8 0.084 16.824 ;
    END
  END o_rd[122]
  PIN o_rd[123]
    DIRECTION OUTPUT ;
    USE SIGNAL ;
    PORT
      LAYER M4 ;
        RECT  0 16.896 0.084 16.92 ;
    END
  END o_rd[123]
  PIN o_rd[124]
    DIRECTION OUTPUT ;
    USE SIGNAL ;
    PORT
      LAYER M4 ;
        RECT  0 16.992 0.084 17.016 ;
    END
  END o_rd[124]
  PIN o_rd[125]
    DIRECTION OUTPUT ;
    USE SIGNAL ;
    PORT
      LAYER M4 ;
        RECT  0 17.088 0.084 17.112 ;
    END
  END o_rd[125]
  PIN o_rd[126]
    DIRECTION OUTPUT ;
    USE SIGNAL ;
    PORT
      LAYER M4 ;
        RECT  0 17.184 0.084 17.208 ;
    END
  END o_rd[126]
  PIN o_rd[127]
    DIRECTION OUTPUT ;
    USE SIGNAL ;
    PORT
      LAYER M4 ;
        RECT  0 17.28 0.084 17.304 ;
    END
  END o_rd[127]
  PIN o_rd[12]
    DIRECTION OUTPUT ;
    USE SIGNAL ;
    PORT
      LAYER M4 ;
        RECT  0 6.24 0.084 6.264 ;
    END
  END o_rd[12]
  PIN o_rd[13]
    DIRECTION OUTPUT ;
    USE SIGNAL ;
    PORT
      LAYER M4 ;
        RECT  0 6.336 0.084 6.36 ;
    END
  END o_rd[13]
  PIN o_rd[14]
    DIRECTION OUTPUT ;
    USE SIGNAL ;
    PORT
      LAYER M4 ;
        RECT  0 6.432 0.084 6.456 ;
    END
  END o_rd[14]
  PIN o_rd[15]
    DIRECTION OUTPUT ;
    USE SIGNAL ;
    PORT
      LAYER M4 ;
        RECT  0 6.528 0.084 6.552 ;
    END
  END o_rd[15]
  PIN o_rd[16]
    DIRECTION OUTPUT ;
    USE SIGNAL ;
    PORT
      LAYER M4 ;
        RECT  0 6.624 0.084 6.648 ;
    END
  END o_rd[16]
  PIN o_rd[17]
    DIRECTION OUTPUT ;
    USE SIGNAL ;
    PORT
      LAYER M4 ;
        RECT  0 6.72 0.084 6.744 ;
    END
  END o_rd[17]
  PIN o_rd[18]
    DIRECTION OUTPUT ;
    USE SIGNAL ;
    PORT
      LAYER M4 ;
        RECT  0 6.816 0.084 6.84 ;
    END
  END o_rd[18]
  PIN o_rd[19]
    DIRECTION OUTPUT ;
    USE SIGNAL ;
    PORT
      LAYER M4 ;
        RECT  0 6.912 0.084 6.936 ;
    END
  END o_rd[19]
  PIN o_rd[1]
    DIRECTION OUTPUT ;
    USE SIGNAL ;
    PORT
      LAYER M4 ;
        RECT  0 5.184 0.084 5.208 ;
    END
  END o_rd[1]
  PIN o_rd[20]
    DIRECTION OUTPUT ;
    USE SIGNAL ;
    PORT
      LAYER M4 ;
        RECT  0 7.008 0.084 7.032 ;
    END
  END o_rd[20]
  PIN o_rd[21]
    DIRECTION OUTPUT ;
    USE SIGNAL ;
    PORT
      LAYER M4 ;
        RECT  0 7.104 0.084 7.128 ;
    END
  END o_rd[21]
  PIN o_rd[22]
    DIRECTION OUTPUT ;
    USE SIGNAL ;
    PORT
      LAYER M4 ;
        RECT  0 7.2 0.084 7.224 ;
    END
  END o_rd[22]
  PIN o_rd[23]
    DIRECTION OUTPUT ;
    USE SIGNAL ;
    PORT
      LAYER M4 ;
        RECT  0 7.296 0.084 7.32 ;
    END
  END o_rd[23]
  PIN o_rd[24]
    DIRECTION OUTPUT ;
    USE SIGNAL ;
    PORT
      LAYER M4 ;
        RECT  0 7.392 0.084 7.416 ;
    END
  END o_rd[24]
  PIN o_rd[25]
    DIRECTION OUTPUT ;
    USE SIGNAL ;
    PORT
      LAYER M4 ;
        RECT  0 7.488 0.084 7.512 ;
    END
  END o_rd[25]
  PIN o_rd[26]
    DIRECTION OUTPUT ;
    USE SIGNAL ;
    PORT
      LAYER M4 ;
        RECT  0 7.584 0.084 7.608 ;
    END
  END o_rd[26]
  PIN o_rd[27]
    DIRECTION OUTPUT ;
    USE SIGNAL ;
    PORT
      LAYER M4 ;
        RECT  0 7.68 0.084 7.704 ;
    END
  END o_rd[27]
  PIN o_rd[28]
    DIRECTION OUTPUT ;
    USE SIGNAL ;
    PORT
      LAYER M4 ;
        RECT  0 7.776 0.084 7.8 ;
    END
  END o_rd[28]
  PIN o_rd[29]
    DIRECTION OUTPUT ;
    USE SIGNAL ;
    PORT
      LAYER M4 ;
        RECT  0 7.872 0.084 7.896 ;
    END
  END o_rd[29]
  PIN o_rd[2]
    DIRECTION OUTPUT ;
    USE SIGNAL ;
    PORT
      LAYER M4 ;
        RECT  0 5.28 0.084 5.304 ;
    END
  END o_rd[2]
  PIN o_rd[30]
    DIRECTION OUTPUT ;
    USE SIGNAL ;
    PORT
      LAYER M4 ;
        RECT  0 7.968 0.084 7.992 ;
    END
  END o_rd[30]
  PIN o_rd[31]
    DIRECTION OUTPUT ;
    USE SIGNAL ;
    PORT
      LAYER M4 ;
        RECT  0 8.064 0.084 8.088 ;
    END
  END o_rd[31]
  PIN o_rd[32]
    DIRECTION OUTPUT ;
    USE SIGNAL ;
    PORT
      LAYER M4 ;
        RECT  0 8.16 0.084 8.184 ;
    END
  END o_rd[32]
  PIN o_rd[33]
    DIRECTION OUTPUT ;
    USE SIGNAL ;
    PORT
      LAYER M4 ;
        RECT  0 8.256 0.084 8.28 ;
    END
  END o_rd[33]
  PIN o_rd[34]
    DIRECTION OUTPUT ;
    USE SIGNAL ;
    PORT
      LAYER M4 ;
        RECT  0 8.352 0.084 8.376 ;
    END
  END o_rd[34]
  PIN o_rd[35]
    DIRECTION OUTPUT ;
    USE SIGNAL ;
    PORT
      LAYER M4 ;
        RECT  0 8.448 0.084 8.472 ;
    END
  END o_rd[35]
  PIN o_rd[36]
    DIRECTION OUTPUT ;
    USE SIGNAL ;
    PORT
      LAYER M4 ;
        RECT  0 8.544 0.084 8.568 ;
    END
  END o_rd[36]
  PIN o_rd[37]
    DIRECTION OUTPUT ;
    USE SIGNAL ;
    PORT
      LAYER M4 ;
        RECT  0 8.64 0.084 8.664 ;
    END
  END o_rd[37]
  PIN o_rd[38]
    DIRECTION OUTPUT ;
    USE SIGNAL ;
    PORT
      LAYER M4 ;
        RECT  0 8.736 0.084 8.76 ;
    END
  END o_rd[38]
  PIN o_rd[39]
    DIRECTION OUTPUT ;
    USE SIGNAL ;
    PORT
      LAYER M4 ;
        RECT  0 8.832 0.084 8.856 ;
    END
  END o_rd[39]
  PIN o_rd[3]
    DIRECTION OUTPUT ;
    USE SIGNAL ;
    PORT
      LAYER M4 ;
        RECT  0 5.376 0.084 5.4 ;
    END
  END o_rd[3]
  PIN o_rd[40]
    DIRECTION OUTPUT ;
    USE SIGNAL ;
    PORT
      LAYER M4 ;
        RECT  0 8.928 0.084 8.952 ;
    END
  END o_rd[40]
  PIN o_rd[41]
    DIRECTION OUTPUT ;
    USE SIGNAL ;
    PORT
      LAYER M4 ;
        RECT  0 9.024 0.084 9.048 ;
    END
  END o_rd[41]
  PIN o_rd[42]
    DIRECTION OUTPUT ;
    USE SIGNAL ;
    PORT
      LAYER M4 ;
        RECT  0 9.12 0.084 9.144 ;
    END
  END o_rd[42]
  PIN o_rd[43]
    DIRECTION OUTPUT ;
    USE SIGNAL ;
    PORT
      LAYER M4 ;
        RECT  0 9.216 0.084 9.24 ;
    END
  END o_rd[43]
  PIN o_rd[44]
    DIRECTION OUTPUT ;
    USE SIGNAL ;
    PORT
      LAYER M4 ;
        RECT  0 9.312 0.084 9.336 ;
    END
  END o_rd[44]
  PIN o_rd[45]
    DIRECTION OUTPUT ;
    USE SIGNAL ;
    PORT
      LAYER M4 ;
        RECT  0 9.408 0.084 9.432 ;
    END
  END o_rd[45]
  PIN o_rd[46]
    DIRECTION OUTPUT ;
    USE SIGNAL ;
    PORT
      LAYER M4 ;
        RECT  0 9.504 0.084 9.528 ;
    END
  END o_rd[46]
  PIN o_rd[47]
    DIRECTION OUTPUT ;
    USE SIGNAL ;
    PORT
      LAYER M4 ;
        RECT  0 9.6 0.084 9.624 ;
    END
  END o_rd[47]
  PIN o_rd[48]
    DIRECTION OUTPUT ;
    USE SIGNAL ;
    PORT
      LAYER M4 ;
        RECT  0 9.696 0.084 9.72 ;
    END
  END o_rd[48]
  PIN o_rd[49]
    DIRECTION OUTPUT ;
    USE SIGNAL ;
    PORT
      LAYER M4 ;
        RECT  0 9.792 0.084 9.816 ;
    END
  END o_rd[49]
  PIN o_rd[4]
    DIRECTION OUTPUT ;
    USE SIGNAL ;
    PORT
      LAYER M4 ;
        RECT  0 5.472 0.084 5.496 ;
    END
  END o_rd[4]
  PIN o_rd[50]
    DIRECTION OUTPUT ;
    USE SIGNAL ;
    PORT
      LAYER M4 ;
        RECT  0 9.888 0.084 9.912 ;
    END
  END o_rd[50]
  PIN o_rd[51]
    DIRECTION OUTPUT ;
    USE SIGNAL ;
    PORT
      LAYER M4 ;
        RECT  0 9.984 0.084 10.008 ;
    END
  END o_rd[51]
  PIN o_rd[52]
    DIRECTION OUTPUT ;
    USE SIGNAL ;
    PORT
      LAYER M4 ;
        RECT  0 10.08 0.084 10.104 ;
    END
  END o_rd[52]
  PIN o_rd[53]
    DIRECTION OUTPUT ;
    USE SIGNAL ;
    PORT
      LAYER M4 ;
        RECT  0 10.176 0.084 10.2 ;
    END
  END o_rd[53]
  PIN o_rd[54]
    DIRECTION OUTPUT ;
    USE SIGNAL ;
    PORT
      LAYER M4 ;
        RECT  0 10.272 0.084 10.296 ;
    END
  END o_rd[54]
  PIN o_rd[55]
    DIRECTION OUTPUT ;
    USE SIGNAL ;
    PORT
      LAYER M4 ;
        RECT  0 10.368 0.084 10.392 ;
    END
  END o_rd[55]
  PIN o_rd[56]
    DIRECTION OUTPUT ;
    USE SIGNAL ;
    PORT
      LAYER M4 ;
        RECT  0 10.464 0.084 10.488 ;
    END
  END o_rd[56]
  PIN o_rd[57]
    DIRECTION OUTPUT ;
    USE SIGNAL ;
    PORT
      LAYER M4 ;
        RECT  0 10.56 0.084 10.584 ;
    END
  END o_rd[57]
  PIN o_rd[58]
    DIRECTION OUTPUT ;
    USE SIGNAL ;
    PORT
      LAYER M4 ;
        RECT  0 10.656 0.084 10.68 ;
    END
  END o_rd[58]
  PIN o_rd[59]
    DIRECTION OUTPUT ;
    USE SIGNAL ;
    PORT
      LAYER M4 ;
        RECT  0 10.752 0.084 10.776 ;
    END
  END o_rd[59]
  PIN o_rd[5]
    DIRECTION OUTPUT ;
    USE SIGNAL ;
    PORT
      LAYER M4 ;
        RECT  0 5.568 0.084 5.592 ;
    END
  END o_rd[5]
  PIN o_rd[60]
    DIRECTION OUTPUT ;
    USE SIGNAL ;
    PORT
      LAYER M4 ;
        RECT  0 10.848 0.084 10.872 ;
    END
  END o_rd[60]
  PIN o_rd[61]
    DIRECTION OUTPUT ;
    USE SIGNAL ;
    PORT
      LAYER M4 ;
        RECT  0 10.944 0.084 10.968 ;
    END
  END o_rd[61]
  PIN o_rd[62]
    DIRECTION OUTPUT ;
    USE SIGNAL ;
    PORT
      LAYER M4 ;
        RECT  0 11.04 0.084 11.064 ;
    END
  END o_rd[62]
  PIN o_rd[63]
    DIRECTION OUTPUT ;
    USE SIGNAL ;
    PORT
      LAYER M4 ;
        RECT  0 11.136 0.084 11.16 ;
    END
  END o_rd[63]
  PIN o_rd[64]
    DIRECTION OUTPUT ;
    USE SIGNAL ;
    PORT
      LAYER M4 ;
        RECT  0 11.232 0.084 11.256 ;
    END
  END o_rd[64]
  PIN o_rd[65]
    DIRECTION OUTPUT ;
    USE SIGNAL ;
    PORT
      LAYER M4 ;
        RECT  0 11.328 0.084 11.352 ;
    END
  END o_rd[65]
  PIN o_rd[66]
    DIRECTION OUTPUT ;
    USE SIGNAL ;
    PORT
      LAYER M4 ;
        RECT  0 11.424 0.084 11.448 ;
    END
  END o_rd[66]
  PIN o_rd[67]
    DIRECTION OUTPUT ;
    USE SIGNAL ;
    PORT
      LAYER M4 ;
        RECT  0 11.52 0.084 11.544 ;
    END
  END o_rd[67]
  PIN o_rd[68]
    DIRECTION OUTPUT ;
    USE SIGNAL ;
    PORT
      LAYER M4 ;
        RECT  0 11.616 0.084 11.64 ;
    END
  END o_rd[68]
  PIN o_rd[69]
    DIRECTION OUTPUT ;
    USE SIGNAL ;
    PORT
      LAYER M4 ;
        RECT  0 11.712 0.084 11.736 ;
    END
  END o_rd[69]
  PIN o_rd[6]
    DIRECTION OUTPUT ;
    USE SIGNAL ;
    PORT
      LAYER M4 ;
        RECT  0 5.664 0.084 5.688 ;
    END
  END o_rd[6]
  PIN o_rd[70]
    DIRECTION OUTPUT ;
    USE SIGNAL ;
    PORT
      LAYER M4 ;
        RECT  0 11.808 0.084 11.832 ;
    END
  END o_rd[70]
  PIN o_rd[71]
    DIRECTION OUTPUT ;
    USE SIGNAL ;
    PORT
      LAYER M4 ;
        RECT  0 11.904 0.084 11.928 ;
    END
  END o_rd[71]
  PIN o_rd[72]
    DIRECTION OUTPUT ;
    USE SIGNAL ;
    PORT
      LAYER M4 ;
        RECT  0 12 0.084 12.024 ;
    END
  END o_rd[72]
  PIN o_rd[73]
    DIRECTION OUTPUT ;
    USE SIGNAL ;
    PORT
      LAYER M4 ;
        RECT  0 12.096 0.084 12.12 ;
    END
  END o_rd[73]
  PIN o_rd[74]
    DIRECTION OUTPUT ;
    USE SIGNAL ;
    PORT
      LAYER M4 ;
        RECT  0 12.192 0.084 12.216 ;
    END
  END o_rd[74]
  PIN o_rd[75]
    DIRECTION OUTPUT ;
    USE SIGNAL ;
    PORT
      LAYER M4 ;
        RECT  0 12.288 0.084 12.312 ;
    END
  END o_rd[75]
  PIN o_rd[76]
    DIRECTION OUTPUT ;
    USE SIGNAL ;
    PORT
      LAYER M4 ;
        RECT  0 12.384 0.084 12.408 ;
    END
  END o_rd[76]
  PIN o_rd[77]
    DIRECTION OUTPUT ;
    USE SIGNAL ;
    PORT
      LAYER M4 ;
        RECT  0 12.48 0.084 12.504 ;
    END
  END o_rd[77]
  PIN o_rd[78]
    DIRECTION OUTPUT ;
    USE SIGNAL ;
    PORT
      LAYER M4 ;
        RECT  0 12.576 0.084 12.6 ;
    END
  END o_rd[78]
  PIN o_rd[79]
    DIRECTION OUTPUT ;
    USE SIGNAL ;
    PORT
      LAYER M4 ;
        RECT  0 12.672 0.084 12.696 ;
    END
  END o_rd[79]
  PIN o_rd[7]
    DIRECTION OUTPUT ;
    USE SIGNAL ;
    PORT
      LAYER M4 ;
        RECT  0 5.76 0.084 5.784 ;
    END
  END o_rd[7]
  PIN o_rd[80]
    DIRECTION OUTPUT ;
    USE SIGNAL ;
    PORT
      LAYER M4 ;
        RECT  0 12.768 0.084 12.792 ;
    END
  END o_rd[80]
  PIN o_rd[81]
    DIRECTION OUTPUT ;
    USE SIGNAL ;
    PORT
      LAYER M4 ;
        RECT  0 12.864 0.084 12.888 ;
    END
  END o_rd[81]
  PIN o_rd[82]
    DIRECTION OUTPUT ;
    USE SIGNAL ;
    PORT
      LAYER M4 ;
        RECT  0 12.96 0.084 12.984 ;
    END
  END o_rd[82]
  PIN o_rd[83]
    DIRECTION OUTPUT ;
    USE SIGNAL ;
    PORT
      LAYER M4 ;
        RECT  0 13.056 0.084 13.08 ;
    END
  END o_rd[83]
  PIN o_rd[84]
    DIRECTION OUTPUT ;
    USE SIGNAL ;
    PORT
      LAYER M4 ;
        RECT  0 13.152 0.084 13.176 ;
    END
  END o_rd[84]
  PIN o_rd[85]
    DIRECTION OUTPUT ;
    USE SIGNAL ;
    PORT
      LAYER M4 ;
        RECT  0 13.248 0.084 13.272 ;
    END
  END o_rd[85]
  PIN o_rd[86]
    DIRECTION OUTPUT ;
    USE SIGNAL ;
    PORT
      LAYER M4 ;
        RECT  0 13.344 0.084 13.368 ;
    END
  END o_rd[86]
  PIN o_rd[87]
    DIRECTION OUTPUT ;
    USE SIGNAL ;
    PORT
      LAYER M4 ;
        RECT  0 13.44 0.084 13.464 ;
    END
  END o_rd[87]
  PIN o_rd[88]
    DIRECTION OUTPUT ;
    USE SIGNAL ;
    PORT
      LAYER M4 ;
        RECT  0 13.536 0.084 13.56 ;
    END
  END o_rd[88]
  PIN o_rd[89]
    DIRECTION OUTPUT ;
    USE SIGNAL ;
    PORT
      LAYER M4 ;
        RECT  0 13.632 0.084 13.656 ;
    END
  END o_rd[89]
  PIN o_rd[8]
    DIRECTION OUTPUT ;
    USE SIGNAL ;
    PORT
      LAYER M4 ;
        RECT  0 5.856 0.084 5.88 ;
    END
  END o_rd[8]
  PIN o_rd[90]
    DIRECTION OUTPUT ;
    USE SIGNAL ;
    PORT
      LAYER M4 ;
        RECT  0 13.728 0.084 13.752 ;
    END
  END o_rd[90]
  PIN o_rd[91]
    DIRECTION OUTPUT ;
    USE SIGNAL ;
    PORT
      LAYER M4 ;
        RECT  0 13.824 0.084 13.848 ;
    END
  END o_rd[91]
  PIN o_rd[92]
    DIRECTION OUTPUT ;
    USE SIGNAL ;
    PORT
      LAYER M4 ;
        RECT  0 13.92 0.084 13.944 ;
    END
  END o_rd[92]
  PIN o_rd[93]
    DIRECTION OUTPUT ;
    USE SIGNAL ;
    PORT
      LAYER M4 ;
        RECT  0 14.016 0.084 14.04 ;
    END
  END o_rd[93]
  PIN o_rd[94]
    DIRECTION OUTPUT ;
    USE SIGNAL ;
    PORT
      LAYER M4 ;
        RECT  0 14.112 0.084 14.136 ;
    END
  END o_rd[94]
  PIN o_rd[95]
    DIRECTION OUTPUT ;
    USE SIGNAL ;
    PORT
      LAYER M4 ;
        RECT  0 14.208 0.084 14.232 ;
    END
  END o_rd[95]
  PIN o_rd[96]
    DIRECTION OUTPUT ;
    USE SIGNAL ;
    PORT
      LAYER M4 ;
        RECT  0 14.304 0.084 14.328 ;
    END
  END o_rd[96]
  PIN o_rd[97]
    DIRECTION OUTPUT ;
    USE SIGNAL ;
    PORT
      LAYER M4 ;
        RECT  0 14.4 0.084 14.424 ;
    END
  END o_rd[97]
  PIN o_rd[98]
    DIRECTION OUTPUT ;
    USE SIGNAL ;
    PORT
      LAYER M4 ;
        RECT  0 14.496 0.084 14.52 ;
    END
  END o_rd[98]
  PIN o_rd[99]
    DIRECTION OUTPUT ;
    USE SIGNAL ;
    PORT
      LAYER M4 ;
        RECT  0 14.592 0.084 14.616 ;
    END
  END o_rd[99]
  PIN o_rd[9]
    DIRECTION OUTPUT ;
    USE SIGNAL ;
    PORT
      LAYER M4 ;
        RECT  0 5.952 0.084 5.976 ;
    END
  END o_rd[9]
  PIN o_rt[0]
    DIRECTION OUTPUT ;
    USE SIGNAL ;
    PORT
      LAYER M4 ;
        RECT  0 18.336 0.084 18.36 ;
    END
  END o_rt[0]
  PIN o_rt[1]
    DIRECTION OUTPUT ;
    USE SIGNAL ;
    PORT
      LAYER M4 ;
        RECT  0 18.432 0.084 18.456 ;
    END
  END o_rt[1]
  PIN o_rt[2]
    DIRECTION OUTPUT ;
    USE SIGNAL ;
    PORT
      LAYER M4 ;
        RECT  0 18.528 0.084 18.552 ;
    END
  END o_rt[2]
  PIN o_rt[3]
    DIRECTION OUTPUT ;
    USE SIGNAL ;
    PORT
      LAYER M4 ;
        RECT  0 18.624 0.084 18.648 ;
    END
  END o_rt[3]
  PIN o_rt[4]
    DIRECTION OUTPUT ;
    USE SIGNAL ;
    PORT
      LAYER M4 ;
        RECT  0 18.72 0.084 18.744 ;
    END
  END o_rt[4]
  PIN o_rt[5]
    DIRECTION OUTPUT ;
    USE SIGNAL ;
    PORT
      LAYER M4 ;
        RECT  0 18.816 0.084 18.84 ;
    END
  END o_rt[5]
  PIN o_rt[6]
    DIRECTION OUTPUT ;
    USE SIGNAL ;
    PORT
      LAYER M4 ;
        RECT  0 18.912 0.084 18.936 ;
    END
  END o_rt[6]
  PIN o_rt[7]
    DIRECTION OUTPUT ;
    USE SIGNAL ;
    PORT
      LAYER M4 ;
        RECT  0 19.008 0.084 19.032 ;
    END
  END o_rt[7]
  PIN o_rv
    DIRECTION OUTPUT ;
    USE SIGNAL ;
    PORT
      LAYER M4 ;
        RECT  0 4.032 0.084 4.056 ;
    END
  END o_rv
  PIN rst_n
    DIRECTION INPUT ;
    USE SIGNAL ;
    PORT
      LAYER M3 ;
        RECT  5.004 75.562 5.022 75.6 ;
    END
  END rst_n
  PIN VDD
    DIRECTION INOUT ;
    USE POWER ;
    PORT
      LAYER M5 ;
        RECT  213.192 2.151 213.312 73.449 ;
        RECT  207.792 2.151 207.912 73.449 ;
        RECT  202.392 2.151 202.512 73.449 ;
        RECT  196.992 2.151 197.112 73.449 ;
        RECT  191.592 2.151 191.712 73.449 ;
        RECT  186.192 2.151 186.312 73.449 ;
        RECT  180.792 2.151 180.912 73.449 ;
        RECT  175.392 2.151 175.512 73.449 ;
        RECT  169.992 2.151 170.112 73.449 ;
        RECT  164.592 2.151 164.712 73.449 ;
        RECT  159.192 2.151 159.312 73.449 ;
        RECT  153.792 2.151 153.912 73.449 ;
        RECT  148.392 2.151 148.512 73.449 ;
        RECT  142.992 2.151 143.112 73.449 ;
        RECT  137.592 2.151 137.712 73.449 ;
        RECT  132.192 2.151 132.312 73.449 ;
        RECT  126.792 2.151 126.912 73.449 ;
        RECT  121.392 2.151 121.512 73.449 ;
        RECT  115.992 2.151 116.112 73.449 ;
        RECT  110.592 2.151 110.712 73.449 ;
        RECT  105.192 2.151 105.312 73.449 ;
        RECT  99.792 2.151 99.912 73.449 ;
        RECT  94.392 2.151 94.512 73.449 ;
        RECT  88.992 2.151 89.112 73.449 ;
        RECT  83.592 2.151 83.712 73.449 ;
        RECT  78.192 2.151 78.312 73.449 ;
        RECT  72.792 2.151 72.912 73.449 ;
        RECT  67.392 2.151 67.512 73.449 ;
        RECT  61.992 2.151 62.112 73.449 ;
        RECT  56.592 2.151 56.712 73.449 ;
        RECT  51.192 2.151 51.312 73.449 ;
        RECT  45.792 2.151 45.912 73.449 ;
        RECT  40.392 2.151 40.512 73.449 ;
        RECT  34.992 2.151 35.112 73.449 ;
        RECT  29.592 2.151 29.712 73.449 ;
        RECT  24.192 2.151 24.312 73.449 ;
        RECT  18.792 2.151 18.912 73.449 ;
        RECT  13.392 2.151 13.512 73.449 ;
        RECT  7.992 2.151 8.112 73.449 ;
        RECT  2.592 2.151 2.712 73.449 ;
    END
  END VDD
  PIN VSS
    DIRECTION INOUT ;
    USE GROUND ;
    PORT
      LAYER M5 ;
        RECT  213 2.137 213.12 73.463 ;
        RECT  207.6 2.137 207.72 73.463 ;
        RECT  202.2 2.137 202.32 73.463 ;
        RECT  196.8 2.137 196.92 73.463 ;
        RECT  191.4 2.137 191.52 73.463 ;
        RECT  186 2.137 186.12 73.463 ;
        RECT  180.6 2.137 180.72 73.463 ;
        RECT  175.2 2.137 175.32 73.463 ;
        RECT  169.8 2.137 169.92 73.463 ;
        RECT  164.4 2.137 164.52 73.463 ;
        RECT  159 2.137 159.12 73.463 ;
        RECT  153.6 2.137 153.72 73.463 ;
        RECT  148.2 2.137 148.32 73.463 ;
        RECT  142.8 2.137 142.92 73.463 ;
        RECT  137.4 2.137 137.52 73.463 ;
        RECT  132 2.137 132.12 73.463 ;
        RECT  126.6 2.137 126.72 73.463 ;
        RECT  121.2 2.137 121.32 73.463 ;
        RECT  115.8 2.137 115.92 73.463 ;
        RECT  110.4 2.137 110.52 73.463 ;
        RECT  105 2.137 105.12 73.463 ;
        RECT  99.6 2.137 99.72 73.463 ;
        RECT  94.2 2.137 94.32 73.463 ;
        RECT  88.8 2.137 88.92 73.463 ;
        RECT  83.4 2.137 83.52 73.463 ;
        RECT  78 2.137 78.12 73.463 ;
        RECT  72.6 2.137 72.72 73.463 ;
        RECT  67.2 2.137 67.32 73.463 ;
        RECT  61.8 2.137 61.92 73.463 ;
        RECT  56.4 2.137 56.52 73.463 ;
        RECT  51 2.137 51.12 73.463 ;
        RECT  45.6 2.137 45.72 73.463 ;
        RECT  40.2 2.137 40.32 73.463 ;
        RECT  34.8 2.137 34.92 73.463 ;
        RECT  29.4 2.137 29.52 73.463 ;
        RECT  24 2.137 24.12 73.463 ;
        RECT  18.6 2.137 18.72 73.463 ;
        RECT  13.2 2.137 13.32 73.463 ;
        RECT  7.8 2.137 7.92 73.463 ;
        RECT  2.4 2.137 2.52 73.463 ;
    END
  END VSS
  OBS
    LAYER RVTN ;
     RECT  2.16 2.16 218.16 2.295 ;
     RECT  2.16 2.565 218.16 2.835 ;
     RECT  2.16 3.105 218.16 3.375 ;
     RECT  2.16 3.645 218.16 3.915 ;
     RECT  2.16 4.185 218.16 4.455 ;
     RECT  2.16 4.725 218.16 4.995 ;
     RECT  2.16 5.265 218.16 5.535 ;
     RECT  2.16 5.805 218.16 6.075 ;
     RECT  2.16 6.345 218.16 6.615 ;
     RECT  2.16 6.885 218.16 7.155 ;
     RECT  2.16 7.425 218.16 7.695 ;
     RECT  2.16 7.965 218.16 8.235 ;
     RECT  2.16 8.505 218.16 8.775 ;
     RECT  2.16 9.045 218.16 9.315 ;
     RECT  2.16 9.585 218.16 9.855 ;
     RECT  2.16 10.125 218.16 10.395 ;
     RECT  2.16 10.665 218.16 10.935 ;
     RECT  2.16 11.205 218.16 11.475 ;
     RECT  2.16 11.745 218.16 12.015 ;
     RECT  2.16 12.285 218.16 12.555 ;
     RECT  2.16 12.825 218.16 13.095 ;
     RECT  2.16 13.365 218.16 13.635 ;
     RECT  2.16 13.905 218.16 14.175 ;
     RECT  2.16 14.445 218.16 14.715 ;
     RECT  2.16 14.985 218.16 15.255 ;
     RECT  2.16 15.525 218.16 15.795 ;
     RECT  2.16 16.065 218.16 16.335 ;
     RECT  2.16 16.605 218.16 16.875 ;
     RECT  2.16 17.145 218.16 17.415 ;
     RECT  2.16 17.685 218.16 17.955 ;
     RECT  2.16 18.225 218.16 18.495 ;
     RECT  2.16 18.765 218.16 19.035 ;
     RECT  2.16 19.305 218.16 19.575 ;
     RECT  2.16 19.845 218.16 20.115 ;
     RECT  2.16 20.385 21.276 20.655 ;
     RECT  199.476 20.385 218.16 20.655 ;
     RECT  2.16 20.925 21.276 21.195 ;
     RECT  199.476 20.925 218.16 21.195 ;
     RECT  2.16 21.465 21.276 21.735 ;
     RECT  199.476 21.465 218.16 21.735 ;
     RECT  2.16 22.005 21.276 22.275 ;
     RECT  199.476 22.005 218.16 22.275 ;
     RECT  2.16 22.545 21.276 22.815 ;
     RECT  199.476 22.545 218.16 22.815 ;
     RECT  2.16 23.085 21.276 23.355 ;
     RECT  199.476 23.085 218.16 23.355 ;
     RECT  2.16 23.625 21.276 23.895 ;
     RECT  199.476 23.625 218.16 23.895 ;
     RECT  2.16 24.165 21.276 24.435 ;
     RECT  199.476 24.165 218.16 24.435 ;
     RECT  2.16 24.705 21.276 24.975 ;
     RECT  199.476 24.705 218.16 24.975 ;
     RECT  2.16 25.245 21.276 25.515 ;
     RECT  199.476 25.245 218.16 25.515 ;
     RECT  2.16 25.785 21.276 26.055 ;
     RECT  199.476 25.785 218.16 26.055 ;
     RECT  2.16 26.325 21.276 26.595 ;
     RECT  199.476 26.325 218.16 26.595 ;
     RECT  2.16 26.865 21.276 27.135 ;
     RECT  199.476 26.865 218.16 27.135 ;
     RECT  2.16 27.405 21.276 27.675 ;
     RECT  199.476 27.405 218.16 27.675 ;
     RECT  2.16 27.945 21.276 28.215 ;
     RECT  199.476 27.945 218.16 28.215 ;
     RECT  2.16 28.485 21.276 28.755 ;
     RECT  199.476 28.485 218.16 28.755 ;
     RECT  2.16 29.025 21.276 29.295 ;
     RECT  199.476 29.025 218.16 29.295 ;
     RECT  2.16 29.565 21.276 29.835 ;
     RECT  199.476 29.565 218.16 29.835 ;
     RECT  2.16 30.105 21.276 30.375 ;
     RECT  199.476 30.105 218.16 30.375 ;
     RECT  2.16 30.645 21.276 30.915 ;
     RECT  199.476 30.645 218.16 30.915 ;
     RECT  2.16 31.185 21.276 31.455 ;
     RECT  199.476 31.185 218.16 31.455 ;
     RECT  2.16 31.725 21.276 31.995 ;
     RECT  199.476 31.725 218.16 31.995 ;
     RECT  2.16 32.265 21.276 32.535 ;
     RECT  199.476 32.265 218.16 32.535 ;
     RECT  2.16 32.805 21.276 33.075 ;
     RECT  199.476 32.805 218.16 33.075 ;
     RECT  2.16 33.345 21.276 33.615 ;
     RECT  199.476 33.345 218.16 33.615 ;
     RECT  2.16 33.885 21.276 34.155 ;
     RECT  199.476 33.885 218.16 34.155 ;
     RECT  2.16 34.425 21.276 34.695 ;
     RECT  199.476 34.425 218.16 34.695 ;
     RECT  2.16 34.965 21.276 35.235 ;
     RECT  199.476 34.965 218.16 35.235 ;
     RECT  2.16 35.505 21.276 35.775 ;
     RECT  199.476 35.505 218.16 35.775 ;
     RECT  2.16 36.045 21.276 36.315 ;
     RECT  199.476 36.045 218.16 36.315 ;
     RECT  2.16 36.585 21.276 36.855 ;
     RECT  199.476 36.585 218.16 36.855 ;
     RECT  2.16 37.125 21.276 37.395 ;
     RECT  199.476 37.125 218.16 37.395 ;
     RECT  2.16 37.665 21.276 37.935 ;
     RECT  199.476 37.665 218.16 37.935 ;
     RECT  2.16 38.205 21.276 38.475 ;
     RECT  199.476 38.205 218.16 38.475 ;
     RECT  2.16 38.745 21.276 39.015 ;
     RECT  199.476 38.745 218.16 39.015 ;
     RECT  2.16 39.285 21.276 39.555 ;
     RECT  199.476 39.285 218.16 39.555 ;
     RECT  2.16 39.825 21.276 40.095 ;
     RECT  199.476 39.825 218.16 40.095 ;
     RECT  2.16 40.365 21.276 40.635 ;
     RECT  199.476 40.365 218.16 40.635 ;
     RECT  2.16 40.905 21.276 41.175 ;
     RECT  199.476 40.905 218.16 41.175 ;
     RECT  2.16 41.445 21.276 41.715 ;
     RECT  199.476 41.445 218.16 41.715 ;
     RECT  2.16 41.985 21.276 42.255 ;
     RECT  199.476 41.985 218.16 42.255 ;
     RECT  2.16 42.525 21.276 42.795 ;
     RECT  199.476 42.525 218.16 42.795 ;
     RECT  2.16 43.065 21.276 43.335 ;
     RECT  199.476 43.065 218.16 43.335 ;
     RECT  2.16 43.605 21.276 43.875 ;
     RECT  199.476 43.605 218.16 43.875 ;
     RECT  2.16 44.145 21.276 44.415 ;
     RECT  199.476 44.145 218.16 44.415 ;
     RECT  2.16 44.685 21.276 44.955 ;
     RECT  199.476 44.685 218.16 44.955 ;
     RECT  2.16 45.225 21.276 45.495 ;
     RECT  199.476 45.225 218.16 45.495 ;
     RECT  2.16 45.765 21.276 46.035 ;
     RECT  199.476 45.765 218.16 46.035 ;
     RECT  2.16 46.305 21.276 46.575 ;
     RECT  199.476 46.305 218.16 46.575 ;
     RECT  2.16 46.845 21.276 47.115 ;
     RECT  199.476 46.845 218.16 47.115 ;
     RECT  2.16 47.385 21.276 47.655 ;
     RECT  199.476 47.385 218.16 47.655 ;
     RECT  2.16 47.925 21.276 48.195 ;
     RECT  199.476 47.925 218.16 48.195 ;
     RECT  2.16 48.465 21.276 48.735 ;
     RECT  199.476 48.465 218.16 48.735 ;
     RECT  2.16 49.005 21.276 49.275 ;
     RECT  199.476 49.005 218.16 49.275 ;
     RECT  2.16 49.545 21.276 49.815 ;
     RECT  199.476 49.545 218.16 49.815 ;
     RECT  2.16 50.085 21.276 50.355 ;
     RECT  199.476 50.085 218.16 50.355 ;
     RECT  2.16 50.625 21.276 50.895 ;
     RECT  199.476 50.625 218.16 50.895 ;
     RECT  2.16 51.165 21.276 51.435 ;
     RECT  199.476 51.165 218.16 51.435 ;
     RECT  2.16 51.705 21.276 51.975 ;
     RECT  199.476 51.705 218.16 51.975 ;
     RECT  2.16 52.245 21.276 52.515 ;
     RECT  199.476 52.245 218.16 52.515 ;
     RECT  2.16 52.785 21.276 53.055 ;
     RECT  199.476 52.785 218.16 53.055 ;
     RECT  2.16 53.325 21.276 53.595 ;
     RECT  199.476 53.325 218.16 53.595 ;
     RECT  2.16 53.865 21.276 54.135 ;
     RECT  199.476 53.865 218.16 54.135 ;
     RECT  2.16 54.405 218.16 54.675 ;
     RECT  2.16 54.945 218.16 55.215 ;
     RECT  2.16 55.485 218.16 55.755 ;
     RECT  2.16 56.025 218.16 56.295 ;
     RECT  2.16 56.565 218.16 56.835 ;
     RECT  2.16 57.105 218.16 57.375 ;
     RECT  2.16 57.645 218.16 57.915 ;
     RECT  2.16 58.185 218.16 58.455 ;
     RECT  2.16 58.725 218.16 58.995 ;
     RECT  2.16 59.265 218.16 59.535 ;
     RECT  2.16 59.805 218.16 60.075 ;
     RECT  2.16 60.345 218.16 60.615 ;
     RECT  2.16 60.885 218.16 61.155 ;
     RECT  2.16 61.425 218.16 61.695 ;
     RECT  2.16 61.965 218.16 62.235 ;
     RECT  2.16 62.505 218.16 62.775 ;
     RECT  2.16 63.045 218.16 63.315 ;
     RECT  2.16 63.585 218.16 63.855 ;
     RECT  2.16 64.125 218.16 64.395 ;
     RECT  2.16 64.665 218.16 64.935 ;
     RECT  2.16 65.205 218.16 65.475 ;
     RECT  2.16 65.745 218.16 66.015 ;
     RECT  2.16 66.285 218.16 66.555 ;
     RECT  2.16 66.825 218.16 67.095 ;
     RECT  2.16 67.365 218.16 67.635 ;
     RECT  2.16 67.905 218.16 68.175 ;
     RECT  2.16 68.445 218.16 68.715 ;
     RECT  2.16 68.985 218.16 69.255 ;
     RECT  2.16 69.525 218.16 69.795 ;
     RECT  2.16 70.065 218.16 70.335 ;
     RECT  2.16 70.605 218.16 70.875 ;
     RECT  2.16 71.145 218.16 71.415 ;
     RECT  2.16 71.685 218.16 71.955 ;
     RECT  2.16 72.225 218.16 72.495 ;
     RECT  2.16 72.765 218.16 73.035 ;
     RECT  2.16 73.305 218.16 73.44 ;
    LAYER RVTP ;
     RECT  2.16 2.295 218.16 2.565 ;
     RECT  2.16 2.835 218.16 3.105 ;
     RECT  2.16 3.375 218.16 3.645 ;
     RECT  2.16 3.915 218.16 4.185 ;
     RECT  2.16 4.455 218.16 4.725 ;
     RECT  2.16 4.995 218.16 5.265 ;
     RECT  2.16 5.535 218.16 5.805 ;
     RECT  2.16 6.075 218.16 6.345 ;
     RECT  2.16 6.615 218.16 6.885 ;
     RECT  2.16 7.155 218.16 7.425 ;
     RECT  2.16 7.695 218.16 7.965 ;
     RECT  2.16 8.235 218.16 8.505 ;
     RECT  2.16 8.775 218.16 9.045 ;
     RECT  2.16 9.315 218.16 9.585 ;
     RECT  2.16 9.855 218.16 10.125 ;
     RECT  2.16 10.395 218.16 10.665 ;
     RECT  2.16 10.935 218.16 11.205 ;
     RECT  2.16 11.475 218.16 11.745 ;
     RECT  2.16 12.015 218.16 12.285 ;
     RECT  2.16 12.555 218.16 12.825 ;
     RECT  2.16 13.095 218.16 13.365 ;
     RECT  2.16 13.635 218.16 13.905 ;
     RECT  2.16 14.175 218.16 14.445 ;
     RECT  2.16 14.715 218.16 14.985 ;
     RECT  2.16 15.255 218.16 15.525 ;
     RECT  2.16 15.795 218.16 16.065 ;
     RECT  2.16 16.335 218.16 16.605 ;
     RECT  2.16 16.875 218.16 17.145 ;
     RECT  2.16 17.415 218.16 17.685 ;
     RECT  2.16 17.955 218.16 18.225 ;
     RECT  2.16 18.495 218.16 18.765 ;
     RECT  2.16 19.035 218.16 19.305 ;
     RECT  2.16 19.575 218.16 19.845 ;
     RECT  2.16 20.115 218.16 20.25 ;
     RECT  2.16 20.25 21.276 20.385 ;
     RECT  199.476 20.25 218.16 20.385 ;
     RECT  2.16 20.655 21.276 20.925 ;
     RECT  199.476 20.655 218.16 20.925 ;
     RECT  2.16 21.195 21.276 21.465 ;
     RECT  199.476 21.195 218.16 21.465 ;
     RECT  2.16 21.735 21.276 22.005 ;
     RECT  199.476 21.735 218.16 22.005 ;
     RECT  2.16 22.275 21.276 22.545 ;
     RECT  199.476 22.275 218.16 22.545 ;
     RECT  2.16 22.815 21.276 23.085 ;
     RECT  199.476 22.815 218.16 23.085 ;
     RECT  2.16 23.355 21.276 23.625 ;
     RECT  199.476 23.355 218.16 23.625 ;
     RECT  2.16 23.895 21.276 24.165 ;
     RECT  199.476 23.895 218.16 24.165 ;
     RECT  2.16 24.435 21.276 24.705 ;
     RECT  199.476 24.435 218.16 24.705 ;
     RECT  2.16 24.975 21.276 25.245 ;
     RECT  199.476 24.975 218.16 25.245 ;
     RECT  2.16 25.515 21.276 25.785 ;
     RECT  199.476 25.515 218.16 25.785 ;
     RECT  2.16 26.055 21.276 26.325 ;
     RECT  199.476 26.055 218.16 26.325 ;
     RECT  2.16 26.595 21.276 26.865 ;
     RECT  199.476 26.595 218.16 26.865 ;
     RECT  2.16 27.135 21.276 27.405 ;
     RECT  199.476 27.135 218.16 27.405 ;
     RECT  2.16 27.675 21.276 27.945 ;
     RECT  199.476 27.675 218.16 27.945 ;
     RECT  2.16 28.215 21.276 28.485 ;
     RECT  199.476 28.215 218.16 28.485 ;
     RECT  2.16 28.755 21.276 29.025 ;
     RECT  199.476 28.755 218.16 29.025 ;
     RECT  2.16 29.295 21.276 29.565 ;
     RECT  199.476 29.295 218.16 29.565 ;
     RECT  2.16 29.835 21.276 30.105 ;
     RECT  199.476 29.835 218.16 30.105 ;
     RECT  2.16 30.375 21.276 30.645 ;
     RECT  199.476 30.375 218.16 30.645 ;
     RECT  2.16 30.915 21.276 31.185 ;
     RECT  199.476 30.915 218.16 31.185 ;
     RECT  2.16 31.455 21.276 31.725 ;
     RECT  199.476 31.455 218.16 31.725 ;
     RECT  2.16 31.995 21.276 32.265 ;
     RECT  199.476 31.995 218.16 32.265 ;
     RECT  2.16 32.535 21.276 32.805 ;
     RECT  199.476 32.535 218.16 32.805 ;
     RECT  2.16 33.075 21.276 33.345 ;
     RECT  199.476 33.075 218.16 33.345 ;
     RECT  2.16 33.615 21.276 33.885 ;
     RECT  199.476 33.615 218.16 33.885 ;
     RECT  2.16 34.155 21.276 34.425 ;
     RECT  199.476 34.155 218.16 34.425 ;
     RECT  2.16 34.695 21.276 34.965 ;
     RECT  199.476 34.695 218.16 34.965 ;
     RECT  2.16 35.235 21.276 35.505 ;
     RECT  199.476 35.235 218.16 35.505 ;
     RECT  2.16 35.775 21.276 36.045 ;
     RECT  199.476 35.775 218.16 36.045 ;
     RECT  2.16 36.315 21.276 36.585 ;
     RECT  199.476 36.315 218.16 36.585 ;
     RECT  2.16 36.855 21.276 37.125 ;
     RECT  199.476 36.855 218.16 37.125 ;
     RECT  2.16 37.395 21.276 37.665 ;
     RECT  199.476 37.395 218.16 37.665 ;
     RECT  2.16 37.935 21.276 38.205 ;
     RECT  199.476 37.935 218.16 38.205 ;
     RECT  2.16 38.475 21.276 38.745 ;
     RECT  199.476 38.475 218.16 38.745 ;
     RECT  2.16 39.015 21.276 39.285 ;
     RECT  199.476 39.015 218.16 39.285 ;
     RECT  2.16 39.555 21.276 39.825 ;
     RECT  199.476 39.555 218.16 39.825 ;
     RECT  2.16 40.095 21.276 40.365 ;
     RECT  199.476 40.095 218.16 40.365 ;
     RECT  2.16 40.635 21.276 40.905 ;
     RECT  199.476 40.635 218.16 40.905 ;
     RECT  2.16 41.175 21.276 41.445 ;
     RECT  199.476 41.175 218.16 41.445 ;
     RECT  2.16 41.715 21.276 41.985 ;
     RECT  199.476 41.715 218.16 41.985 ;
     RECT  2.16 42.255 21.276 42.525 ;
     RECT  199.476 42.255 218.16 42.525 ;
     RECT  2.16 42.795 21.276 43.065 ;
     RECT  199.476 42.795 218.16 43.065 ;
     RECT  2.16 43.335 21.276 43.605 ;
     RECT  199.476 43.335 218.16 43.605 ;
     RECT  2.16 43.875 21.276 44.145 ;
     RECT  199.476 43.875 218.16 44.145 ;
     RECT  2.16 44.415 21.276 44.685 ;
     RECT  199.476 44.415 218.16 44.685 ;
     RECT  2.16 44.955 21.276 45.225 ;
     RECT  199.476 44.955 218.16 45.225 ;
     RECT  2.16 45.495 21.276 45.765 ;
     RECT  199.476 45.495 218.16 45.765 ;
     RECT  2.16 46.035 21.276 46.305 ;
     RECT  199.476 46.035 218.16 46.305 ;
     RECT  2.16 46.575 21.276 46.845 ;
     RECT  199.476 46.575 218.16 46.845 ;
     RECT  2.16 47.115 21.276 47.385 ;
     RECT  199.476 47.115 218.16 47.385 ;
     RECT  2.16 47.655 21.276 47.925 ;
     RECT  199.476 47.655 218.16 47.925 ;
     RECT  2.16 48.195 21.276 48.465 ;
     RECT  199.476 48.195 218.16 48.465 ;
     RECT  2.16 48.735 21.276 49.005 ;
     RECT  199.476 48.735 218.16 49.005 ;
     RECT  2.16 49.275 21.276 49.545 ;
     RECT  199.476 49.275 218.16 49.545 ;
     RECT  2.16 49.815 21.276 50.085 ;
     RECT  199.476 49.815 218.16 50.085 ;
     RECT  2.16 50.355 21.276 50.625 ;
     RECT  199.476 50.355 218.16 50.625 ;
     RECT  2.16 50.895 21.276 51.165 ;
     RECT  199.476 50.895 218.16 51.165 ;
     RECT  2.16 51.435 21.276 51.705 ;
     RECT  199.476 51.435 218.16 51.705 ;
     RECT  2.16 51.975 21.276 52.245 ;
     RECT  199.476 51.975 218.16 52.245 ;
     RECT  2.16 52.515 21.276 52.785 ;
     RECT  199.476 52.515 218.16 52.785 ;
     RECT  2.16 53.055 21.276 53.325 ;
     RECT  199.476 53.055 218.16 53.325 ;
     RECT  2.16 53.595 21.276 53.865 ;
     RECT  199.476 53.595 218.16 53.865 ;
     RECT  2.16 54.135 21.276 54.27 ;
     RECT  199.476 54.135 218.16 54.27 ;
     RECT  2.16 54.27 218.16 54.405 ;
     RECT  2.16 54.675 218.16 54.945 ;
     RECT  2.16 55.215 218.16 55.485 ;
     RECT  2.16 55.755 218.16 56.025 ;
     RECT  2.16 56.295 218.16 56.565 ;
     RECT  2.16 56.835 218.16 57.105 ;
     RECT  2.16 57.375 218.16 57.645 ;
     RECT  2.16 57.915 218.16 58.185 ;
     RECT  2.16 58.455 218.16 58.725 ;
     RECT  2.16 58.995 218.16 59.265 ;
     RECT  2.16 59.535 218.16 59.805 ;
     RECT  2.16 60.075 218.16 60.345 ;
     RECT  2.16 60.615 218.16 60.885 ;
     RECT  2.16 61.155 218.16 61.425 ;
     RECT  2.16 61.695 218.16 61.965 ;
     RECT  2.16 62.235 218.16 62.505 ;
     RECT  2.16 62.775 218.16 63.045 ;
     RECT  2.16 63.315 218.16 63.585 ;
     RECT  2.16 63.855 218.16 64.125 ;
     RECT  2.16 64.395 218.16 64.665 ;
     RECT  2.16 64.935 218.16 65.205 ;
     RECT  2.16 65.475 218.16 65.745 ;
     RECT  2.16 66.015 218.16 66.285 ;
     RECT  2.16 66.555 218.16 66.825 ;
     RECT  2.16 67.095 218.16 67.365 ;
     RECT  2.16 67.635 218.16 67.905 ;
     RECT  2.16 68.175 218.16 68.445 ;
     RECT  2.16 68.715 218.16 68.985 ;
     RECT  2.16 69.255 218.16 69.525 ;
     RECT  2.16 69.795 218.16 70.065 ;
     RECT  2.16 70.335 218.16 70.605 ;
     RECT  2.16 70.875 218.16 71.145 ;
     RECT  2.16 71.415 218.16 71.685 ;
     RECT  2.16 71.955 218.16 72.225 ;
     RECT  2.16 72.495 218.16 72.765 ;
     RECT  2.16 73.035 218.16 73.305 ;
    LAYER M1 ;
     RECT  2.16 2.151 218.16 20.259 ;
     RECT  23.328 22.464 197.448 52.2 ;
     RECT  2.16 20.259 21.276 54.261 ;
     RECT  199.476 20.259 218.16 54.261 ;
     RECT  2.16 54.261 218.16 73.449 ;
    LAYER M2 ;
     RECT  0.103 13.806 0.203 14.508 ;
     RECT  0.103 8.946 0.239 8.964 ;
     RECT  0.203 13.806 0.239 13.824 ;
     RECT  1.147 4.266 1.183 4.284 ;
     RECT  1.219 3.384 1.687 3.402 ;
     RECT  1.183 4.266 1.687 4.752 ;
     RECT  1.723 7.704 1.759 7.794 ;
     RECT  1.723 9.396 1.759 9.954 ;
     RECT  1.723 12.294 1.759 13.392 ;
     RECT  1.147 17.082 1.759 17.1 ;
     RECT  1.723 18.576 1.759 18.594 ;
     RECT  1.723 22.626 1.759 23.274 ;
     RECT  1.759 7.704 1.795 8.334 ;
     RECT  1.759 9.126 1.795 9.954 ;
     RECT  1.723 11.016 1.795 11.034 ;
     RECT  1.759 12.294 1.795 13.464 ;
     RECT  1.759 18.576 1.795 19.134 ;
     RECT  1.759 22.626 1.795 24.462 ;
     RECT  1.723 25.326 1.795 25.344 ;
     RECT  1.759 26.136 1.795 26.154 ;
     RECT  1.795 12.294 1.831 14.004 ;
     RECT  1.759 15.876 1.831 15.894 ;
     RECT  1.795 18.576 1.831 19.872 ;
     RECT  1.723 20.736 1.831 21.294 ;
     RECT  1.795 11.016 1.867 11.394 ;
     RECT  1.831 12.294 1.867 14.742 ;
     RECT  1.831 15.534 1.867 15.894 ;
     RECT  1.795 7.704 1.903 9.954 ;
     RECT  1.867 15.534 1.903 16.092 ;
     RECT  1.759 16.956 1.903 17.1 ;
     RECT  1.903 7.704 1.975 10.224 ;
     RECT  1.867 11.016 1.975 14.742 ;
     RECT  1.687 3.384 2.16 4.752 ;
     RECT  1.723 5.778 2.16 6.714 ;
     RECT  1.975 7.704 2.16 14.742 ;
     RECT  1.903 15.534 2.16 17.1 ;
     RECT  1.831 18.576 2.16 21.294 ;
     RECT  1.795 22.086 2.16 24.462 ;
     RECT  1.795 25.326 2.16 26.154 ;
     RECT  4.999 74.628 5.099 74.646 ;
     RECT  2.16 2.151 21.276 73.449 ;
     RECT  22.999 36.594 23.035 36.612 ;
     RECT  21.276 2.151 23.328 22.806 ;
     RECT  22.531 23.976 23.328 23.994 ;
     RECT  23.071 25.101 23.328 25.119 ;
     RECT  23.071 26.766 23.328 26.784 ;
     RECT  23.107 33.084 23.328 33.102 ;
     RECT  23.035 36.594 23.328 36.684 ;
     RECT  23.071 43.506 23.328 43.524 ;
     RECT  23.328 2.151 112.775 52.2 ;
     RECT  112.775 2.151 123.143 21.42 ;
     RECT  123.143 2.151 139.639 20.988 ;
     RECT  139.639 2.151 140.467 21.42 ;
     RECT  112.775 22.464 140.467 52.2 ;
     RECT  140.467 2.151 197.448 52.2 ;
     RECT  197.448 32.886 197.771 33.03 ;
     RECT  198.931 41.382 198.967 41.4 ;
     RECT  198.931 42.156 198.967 44.334 ;
     RECT  198.967 41.382 199.003 44.334 ;
     RECT  199.003 41.382 199.039 44.64 ;
     RECT  199.039 41.382 199.471 44.874 ;
     RECT  197.448 2.151 199.476 22.032 ;
     RECT  197.448 23.436 199.476 23.454 ;
     RECT  197.448 25.254 199.476 25.272 ;
     RECT  197.448 26.406 199.476 26.892 ;
     RECT  197.448 28.026 199.476 28.584 ;
     RECT  197.448 29.376 199.476 29.394 ;
     RECT  197.771 32.886 199.476 32.904 ;
     RECT  197.448 35.676 199.476 35.694 ;
     RECT  199.435 40.14 199.476 40.158 ;
     RECT  199.471 41.22 199.476 44.874 ;
     RECT  21.276 54.261 199.476 73.449 ;
     RECT  199.476 2.151 218.16 73.449 ;
     RECT  218.16 4.968 218.327 8.766 ;
     RECT  218.16 9.558 218.327 27.234 ;
     RECT  218.327 4.968 218.363 6.336 ;
     RECT  218.16 4.158 218.867 4.176 ;
     RECT  218.327 7.128 218.867 8.766 ;
     RECT  218.327 9.63 218.867 27.234 ;
     RECT  218.867 9.63 218.903 24.426 ;
     RECT  218.903 9.666 218.975 24.426 ;
     RECT  218.975 10.368 219.407 24.426 ;
     RECT  218.867 25.182 219.407 27.234 ;
     RECT  218.363 5.238 219.443 6.336 ;
     RECT  218.867 7.128 219.443 8.19 ;
     RECT  219.407 10.368 219.443 24.264 ;
     RECT  219.407 25.182 219.443 26.892 ;
     RECT  219.443 10.944 219.479 11.97 ;
     RECT  219.443 14.184 219.479 16.668 ;
     RECT  219.479 11.718 219.515 11.97 ;
     RECT  219.479 14.184 219.515 16.29 ;
     RECT  219.515 11.718 219.551 11.736 ;
     RECT  219.515 14.49 220.127 16.29 ;
     RECT  219.443 17.424 220.163 24.264 ;
     RECT  219.443 5.742 220.199 5.868 ;
     RECT  220.127 14.49 220.199 16.209 ;
     RECT  220.163 17.424 220.199 22.806 ;
     RECT  220.163 23.634 220.199 24.12 ;
     RECT  220.199 5.742 220.235 5.76 ;
     RECT  219.443 8.172 220.235 8.19 ;
     RECT  219.479 10.944 220.235 10.962 ;
     RECT  219.443 13.374 220.235 13.392 ;
     RECT  220.199 14.49 220.235 14.508 ;
     RECT  220.199 15.768 220.235 16.209 ;
     RECT  220.199 17.496 220.235 20.646 ;
     RECT  220.199 21.744 220.235 22.806 ;
     RECT  220.199 24.102 220.235 24.12 ;
     RECT  219.443 25.182 220.235 25.2 ;
     RECT  219.443 26.874 220.235 26.892 ;
     RECT  220.235 18.27 220.307 18.288 ;
     RECT  220.235 20.052 220.307 20.07 ;
    LAYER M3 ;
     RECT  2.415 2.143 2.505 2.413 ;
     RECT  7.815 2.143 7.905 2.413 ;
     RECT  13.215 2.143 13.305 2.413 ;
     RECT  18.615 2.143 18.705 2.413 ;
     RECT  24.015 2.143 24.105 2.413 ;
     RECT  29.415 2.143 29.505 2.413 ;
     RECT  34.815 2.143 34.905 2.413 ;
     RECT  40.215 2.143 40.305 2.413 ;
     RECT  45.615 2.143 45.705 2.413 ;
     RECT  51.015 2.143 51.105 2.413 ;
     RECT  56.415 2.143 56.505 2.413 ;
     RECT  61.815 2.143 61.905 2.413 ;
     RECT  67.215 2.143 67.305 2.413 ;
     RECT  72.615 2.143 72.705 2.413 ;
     RECT  78.015 2.143 78.105 2.413 ;
     RECT  83.415 2.143 83.505 2.413 ;
     RECT  88.815 2.143 88.905 2.413 ;
     RECT  94.215 2.143 94.305 2.413 ;
     RECT  99.615 2.143 99.705 2.413 ;
     RECT  105.015 2.143 105.105 2.413 ;
     RECT  110.415 2.143 110.505 2.413 ;
     RECT  115.815 2.143 115.905 2.413 ;
     RECT  121.215 2.143 121.305 2.413 ;
     RECT  126.615 2.143 126.705 2.413 ;
     RECT  132.015 2.143 132.105 2.413 ;
     RECT  137.415 2.143 137.505 2.413 ;
     RECT  142.815 2.143 142.905 2.413 ;
     RECT  148.215 2.143 148.305 2.413 ;
     RECT  153.615 2.143 153.705 2.413 ;
     RECT  159.015 2.143 159.105 2.413 ;
     RECT  164.415 2.143 164.505 2.413 ;
     RECT  169.815 2.143 169.905 2.413 ;
     RECT  175.215 2.143 175.305 2.413 ;
     RECT  180.615 2.143 180.705 2.413 ;
     RECT  186.015 2.143 186.105 2.413 ;
     RECT  191.415 2.143 191.505 2.413 ;
     RECT  196.815 2.143 196.905 2.413 ;
     RECT  202.215 2.143 202.305 2.413 ;
     RECT  207.615 2.143 207.705 2.413 ;
     RECT  213.015 2.143 213.105 2.413 ;
     RECT  2.415 2.413 2.697 3.181 ;
     RECT  2.34 3.181 2.697 3.271 ;
     RECT  3.492 3.181 3.51 3.271 ;
     RECT  2.34 3.271 3.51 3.379 ;
     RECT  2.34 3.379 3.654 3.451 ;
     RECT  2.34 3.451 3.69 3.721 ;
     RECT  2.304 3.721 3.762 3.811 ;
     RECT  1.224 3.379 1.242 3.955 ;
     RECT  2.304 3.811 4.302 3.955 ;
     RECT  7.815 2.413 8.097 3.991 ;
     RECT  5.796 3.991 5.814 4.109 ;
     RECT  7.632 3.991 8.097 4.117 ;
     RECT  0.108 4.027 0.126 4.157 ;
     RECT  218.844 4.027 218.862 4.181 ;
     RECT  1.224 3.955 4.302 4.261 ;
     RECT  6.336 4.189 6.354 4.261 ;
     RECT  7.164 4.117 8.097 4.261 ;
     RECT  1.152 4.261 4.302 4.351 ;
     RECT  213.015 2.413 213.297 4.351 ;
     RECT  217.584 4.261 217.602 4.379 ;
     RECT  212.904 4.351 213.297 4.397 ;
     RECT  215.46 4.351 215.478 4.459 ;
     RECT  216.324 4.351 216.342 4.459 ;
     RECT  215.46 4.459 216.342 4.495 ;
     RECT  200.484 4.459 200.502 4.531 ;
     RECT  215.064 4.495 216.342 4.531 ;
     RECT  215.064 4.531 216.522 4.541 ;
     RECT  200.484 4.531 200.682 4.559 ;
     RECT  121.215 2.413 121.497 4.657 ;
     RECT  215.46 4.541 216.522 4.657 ;
     RECT  121.215 4.657 121.986 4.733 ;
     RECT  200.664 4.559 200.682 4.733 ;
     RECT  218.34 4.963 218.358 5.035 ;
     RECT  6.336 4.261 8.262 5.071 ;
     RECT  1.152 4.351 4.878 5.161 ;
     RECT  6.336 5.071 8.298 5.197 ;
     RECT  9.252 5.161 9.27 5.197 ;
     RECT  1.152 5.161 4.914 5.269 ;
     RECT  218.304 5.035 218.358 5.275 ;
     RECT  219.42 5.179 219.438 5.275 ;
     RECT  10.116 4.963 10.134 5.305 ;
     RECT  11.664 5.269 11.682 5.305 ;
     RECT  215.46 4.657 217.314 5.305 ;
     RECT  1.152 5.269 5.238 5.341 ;
     RECT  6.336 5.197 9.27 5.341 ;
     RECT  11.592 5.305 11.682 5.341 ;
     RECT  13.215 2.413 13.497 5.341 ;
     RECT  213.015 4.397 213.297 5.341 ;
     RECT  215.1 5.305 217.314 5.341 ;
     RECT  218.304 5.275 219.438 5.341 ;
     RECT  215.1 5.341 219.438 5.405 ;
     RECT  1.152 5.341 9.27 5.419 ;
     RECT  10.044 5.305 10.134 5.419 ;
     RECT  1.152 5.419 10.134 5.431 ;
     RECT  11.592 5.341 11.718 5.431 ;
     RECT  15.084 5.269 15.102 5.431 ;
     RECT  213.015 5.341 213.822 5.431 ;
     RECT  116.856 4.621 116.874 5.459 ;
     RECT  215.1 5.405 218.034 5.459 ;
     RECT  11.592 5.431 12.114 5.467 ;
     RECT  12.888 5.341 13.497 5.467 ;
     RECT  1.152 5.431 10.566 5.531 ;
     RECT  26.784 5.431 26.802 5.531 ;
     RECT  212.58 5.431 213.822 5.575 ;
     RECT  220.212 5.563 220.23 5.659 ;
     RECT  6.3 5.531 10.566 5.707 ;
     RECT  220.176 5.659 220.23 5.765 ;
     RECT  212.148 5.575 213.822 5.809 ;
     RECT  215.1 5.459 217.746 5.809 ;
     RECT  220.176 5.765 220.194 5.873 ;
     RECT  6.3 5.707 10.638 5.881 ;
     RECT  11.592 5.467 13.497 5.881 ;
     RECT  211.14 5.971 211.158 6.007 ;
     RECT  212.148 5.809 217.746 6.007 ;
     RECT  18.615 2.413 18.897 6.043 ;
     RECT  1.152 5.531 5.562 6.071 ;
     RECT  15.084 5.431 15.678 6.079 ;
     RECT  6.3 5.881 13.497 6.091 ;
     RECT  218.844 5.405 219.438 6.143 ;
     RECT  17.352 6.115 17.37 6.151 ;
     RECT  6.3 6.091 13.95 6.241 ;
     RECT  14.868 6.079 15.678 6.241 ;
     RECT  123.732 6.151 123.75 6.305 ;
     RECT  211.14 6.007 217.746 6.341 ;
     RECT  1.152 6.071 5.274 6.365 ;
     RECT  213.015 6.341 217.746 6.575 ;
     RECT  0.144 6.379 0.162 6.653 ;
     RECT  6.3 6.241 15.678 6.691 ;
     RECT  211.14 6.341 212.166 6.691 ;
     RECT  214.164 6.575 217.746 6.817 ;
     RECT  211.104 6.691 212.166 6.881 ;
     RECT  1.188 6.365 5.274 6.893 ;
     RECT  1.728 6.893 5.274 6.925 ;
     RECT  6.3 6.691 16.182 6.925 ;
     RECT  116.856 6.781 116.874 6.961 ;
     RECT  0.18 6.859 0.198 7.003 ;
     RECT  112.284 6.241 112.302 7.123 ;
     RECT  126.615 2.413 126.897 7.123 ;
     RECT  0.18 7.003 0.306 7.133 ;
     RECT  112.284 7.123 112.698 7.151 ;
     RECT  116.856 6.961 116.946 7.151 ;
     RECT  211.176 6.881 212.166 7.151 ;
     RECT  214.164 6.817 218.322 7.195 ;
     RECT  219.42 6.143 219.438 7.195 ;
     RECT  207.615 2.413 207.897 7.231 ;
     RECT  211.5 7.151 212.166 7.259 ;
     RECT  213.015 6.575 213.426 7.321 ;
     RECT  212.976 7.321 213.426 7.339 ;
     RECT  214.164 7.195 219.438 7.421 ;
     RECT  17.244 6.151 17.37 7.429 ;
     RECT  22.392 5.467 22.41 7.429 ;
     RECT  1.728 6.925 16.182 7.465 ;
     RECT  214.164 7.421 218.322 7.517 ;
     RECT  0.144 7.435 0.162 7.613 ;
     RECT  214.164 7.517 217.854 7.619 ;
     RECT  18.432 6.043 18.897 7.627 ;
     RECT  212.94 7.339 213.426 7.627 ;
     RECT  214.164 7.619 217.422 7.627 ;
     RECT  212.94 7.627 217.422 7.655 ;
     RECT  17.064 7.429 17.37 7.663 ;
     RECT  18.432 7.627 19.098 7.663 ;
     RECT  212.004 7.259 212.166 7.691 ;
     RECT  219.384 7.421 219.438 7.691 ;
     RECT  109.116 7.123 109.134 7.699 ;
     RECT  18.432 7.663 19.674 7.771 ;
     RECT  107.964 6.511 107.982 7.771 ;
     RECT  212.94 7.655 213.786 7.771 ;
     RECT  20.772 6.511 20.79 7.861 ;
     RECT  107.964 7.771 108.09 7.889 ;
     RECT  109.116 7.699 109.206 7.889 ;
     RECT  214.704 7.655 217.422 7.889 ;
     RECT  106.596 7.699 106.614 7.925 ;
     RECT  214.776 7.889 217.422 7.925 ;
     RECT  105.015 2.413 105.297 7.933 ;
     RECT  210.348 7.861 210.366 7.961 ;
     RECT  216.576 7.925 217.422 7.961 ;
     RECT  219.384 7.691 219.402 7.961 ;
     RECT  216.576 7.961 216.81 8.033 ;
     RECT  109.188 7.889 109.206 8.069 ;
     RECT  216.576 8.033 216.738 8.195 ;
     RECT  220.212 7.387 220.23 8.195 ;
     RECT  207.615 7.231 208.062 8.267 ;
     RECT  18.36 7.771 19.674 8.311 ;
     RECT  20.736 7.861 20.79 8.311 ;
     RECT  212.58 7.771 213.786 8.339 ;
     RECT  110.415 2.413 110.697 8.401 ;
     RECT  100.728 7.663 100.746 8.429 ;
     RECT  21.924 7.429 22.41 8.437 ;
     RECT  216.684 8.195 216.738 8.465 ;
     RECT  116.856 7.151 116.874 8.501 ;
     RECT  1.728 7.465 16.254 8.509 ;
     RECT  16.992 7.663 17.37 8.509 ;
     RECT  107.424 8.239 107.442 8.545 ;
     RECT  203.76 6.817 203.778 8.573 ;
     RECT  105.015 7.933 105.498 8.581 ;
     RECT  125.964 7.123 126.897 8.609 ;
     RECT  0.144 8.587 0.162 8.635 ;
     RECT  104.94 8.581 105.498 8.699 ;
     RECT  106.848 8.545 107.442 8.699 ;
     RECT  112.68 7.151 112.698 8.699 ;
     RECT  21.924 8.437 22.482 8.707 ;
     RECT  0.144 8.635 0.342 8.765 ;
     RECT  106.92 8.699 107.442 8.771 ;
     RECT  218.844 8.635 218.862 8.771 ;
     RECT  106.992 8.771 107.442 8.807 ;
     RECT  212.58 8.339 213.678 8.851 ;
     RECT  110.415 8.401 110.754 8.879 ;
     RECT  0.144 8.765 0.234 8.923 ;
     RECT  0.108 8.923 0.234 8.969 ;
     RECT  105.015 8.699 105.498 8.969 ;
     RECT  21.816 8.707 22.482 8.977 ;
     RECT  0.216 8.969 0.234 9.101 ;
     RECT  1.728 8.509 17.37 9.115 ;
     RECT  102.672 8.707 102.69 9.211 ;
     RECT  107.424 8.807 107.442 9.211 ;
     RECT  107.424 9.211 107.766 9.239 ;
     RECT  1.152 9.115 17.37 9.293 ;
     RECT  102.6 9.211 102.69 9.311 ;
     RECT  216.72 8.465 216.738 9.319 ;
     RECT  216.72 9.319 217.242 9.391 ;
     RECT  104.004 8.851 104.022 9.481 ;
     RECT  210.348 8.941 210.366 9.481 ;
     RECT  126.615 8.609 126.897 9.553 ;
     RECT  216.72 9.391 217.746 9.553 ;
     RECT  210.348 9.481 210.438 9.581 ;
     RECT  216.72 9.553 218.322 9.625 ;
     RECT  214.776 7.925 215.658 9.661 ;
     RECT  216.72 9.625 218.898 9.661 ;
     RECT  210.348 9.581 210.366 9.689 ;
     RECT  216.72 9.661 218.97 9.821 ;
     RECT  115.815 2.413 116.097 9.823 ;
     RECT  212.436 8.851 213.678 9.931 ;
     RECT  214.776 9.661 215.946 9.931 ;
     RECT  211.464 10.021 211.482 10.075 ;
     RECT  212.436 9.931 215.946 10.075 ;
     RECT  0.144 9.979 0.162 10.157 ;
     RECT  218.844 9.821 218.97 10.171 ;
     RECT  211.464 10.075 215.946 10.201 ;
     RECT  216.72 9.821 217.746 10.201 ;
     RECT  1.728 9.293 17.37 10.459 ;
     RECT  211.464 10.201 217.746 10.471 ;
     RECT  1.44 10.459 17.37 10.555 ;
     RECT  211.14 10.471 217.746 10.589 ;
     RECT  1.368 10.555 17.37 10.651 ;
     RECT  107.748 9.239 107.766 10.669 ;
     RECT  218.844 10.171 219.438 10.733 ;
     RECT  211.428 10.589 217.746 10.831 ;
     RECT  1.152 10.651 17.37 10.903 ;
     RECT  18.36 8.311 20.79 10.903 ;
     RECT  112.392 9.751 112.41 10.903 ;
     RECT  116.856 9.859 116.874 10.939 ;
     RECT  210.348 10.831 210.366 10.939 ;
     RECT  220.212 10.459 220.23 10.967 ;
     RECT  105.015 8.969 105.297 11.011 ;
     RECT  211.428 10.831 217.818 11.173 ;
     RECT  40.215 2.413 40.497 11.281 ;
     RECT  106.236 10.561 106.254 11.281 ;
     RECT  112.392 10.903 113.022 11.281 ;
     RECT  109.116 11.209 109.134 11.371 ;
     RECT  106.236 11.281 106.362 11.399 ;
     RECT  109.116 11.371 109.206 11.399 ;
     RECT  211.428 11.173 218.034 11.443 ;
     RECT  211.428 11.443 218.322 11.509 ;
     RECT  219.456 10.975 219.474 11.509 ;
     RECT  99.615 2.413 99.897 11.515 ;
     RECT  210.348 10.939 210.402 11.515 ;
     RECT  104.832 11.011 105.297 11.551 ;
     RECT  211.428 11.509 219.474 11.645 ;
     RECT  99.216 11.515 99.897 11.669 ;
     RECT  104.832 11.551 105.426 11.669 ;
     RECT  210.348 11.515 210.438 11.669 ;
     RECT  0.288 11.611 0.306 11.707 ;
     RECT  110.415 8.879 110.697 11.713 ;
     RECT  218.844 11.645 219.474 11.713 ;
     RECT  0.18 11.707 0.306 11.741 ;
     RECT  207.615 8.267 207.897 11.749 ;
     RECT  103.32 9.481 104.022 11.821 ;
     RECT  104.832 11.669 105.297 11.821 ;
     RECT  112.392 11.281 113.67 11.939 ;
     RECT  115.2 9.823 116.097 11.939 ;
     RECT  118.872 8.941 118.89 11.939 ;
     RECT  0.18 11.741 0.198 11.981 ;
     RECT  103.32 11.821 105.297 12.209 ;
     RECT  211.428 11.645 217.818 12.209 ;
     RECT  109.188 11.399 109.206 12.217 ;
     RECT  110.415 11.713 111.186 12.217 ;
     RECT  1.152 10.903 20.79 12.221 ;
     RECT  211.428 12.209 217.782 12.281 ;
     RECT  118.98 12.091 118.998 12.289 ;
     RECT  218.844 11.713 219.546 12.317 ;
     RECT  113.004 11.939 113.67 12.749 ;
     RECT  24.015 2.413 24.297 12.793 ;
     RECT  113.652 12.749 113.67 12.821 ;
     RECT  210.348 11.669 210.366 12.865 ;
     RECT  210.348 12.865 210.402 12.901 ;
     RECT  25.344 12.487 25.362 13.027 ;
     RECT  26.496 6.277 26.514 13.027 ;
     RECT  210.348 12.901 210.474 13.055 ;
     RECT  116.856 10.939 116.91 13.063 ;
     RECT  218.844 12.317 219.474 13.085 ;
     RECT  99.324 11.669 99.897 13.135 ;
     RECT  211.608 12.281 217.782 13.135 ;
     RECT  103.392 12.209 105.297 13.171 ;
     RECT  211.32 13.135 217.854 13.181 ;
     RECT  25.344 13.027 26.514 13.261 ;
     RECT  27.612 12.757 27.63 13.261 ;
     RECT  107.748 10.669 108.342 13.261 ;
     RECT  109.188 12.217 111.186 13.261 ;
     RECT  211.392 13.181 217.854 13.261 ;
     RECT  95.508 12.253 95.526 13.289 ;
     RECT  220.212 12.763 220.23 13.339 ;
     RECT  23.616 12.793 24.297 13.369 ;
     RECT  25.344 13.261 27.63 13.369 ;
     RECT  118.98 12.289 119.502 13.369 ;
     RECT  121.215 4.733 121.497 13.369 ;
     RECT  1.728 12.221 20.79 13.387 ;
     RECT  120.24 10.597 120.258 13.397 ;
     RECT  99.324 13.135 100.602 13.405 ;
     RECT  116.856 13.063 117.306 13.433 ;
     RECT  210.348 13.055 210.402 13.433 ;
     RECT  103.392 13.171 105.678 13.441 ;
     RECT  90.648 13.261 90.666 13.469 ;
     RECT  107.748 13.261 111.186 13.469 ;
     RECT  210.384 13.433 210.402 13.469 ;
     RECT  1.152 13.387 20.79 13.567 ;
     RECT  21.816 8.977 22.554 13.567 ;
     RECT  118.332 13.369 119.502 13.567 ;
     RECT  211.392 13.261 218.034 13.595 ;
     RECT  116.928 13.433 117.306 13.631 ;
     RECT  0.144 12.667 0.162 13.675 ;
     RECT  113.976 12.865 113.994 13.711 ;
     RECT  115.308 11.939 116.097 13.711 ;
     RECT  117.216 13.631 117.306 13.711 ;
     RECT  118.188 13.567 119.502 13.711 ;
     RECT  0.144 13.675 0.234 13.723 ;
     RECT  107.748 13.469 109.206 13.739 ;
     RECT  0.144 13.723 0.306 13.801 ;
     RECT  109.188 13.739 109.206 13.829 ;
     RECT  211.464 13.595 218.034 13.829 ;
     RECT  0.108 13.801 0.306 13.853 ;
     RECT  23.616 13.369 27.63 13.945 ;
     RECT  106.596 13.711 106.614 13.945 ;
     RECT  107.748 13.739 108.45 13.945 ;
     RECT  103.392 13.441 105.75 13.973 ;
     RECT  23.616 13.945 28.206 13.981 ;
     RECT  29.415 2.413 29.697 13.981 ;
     RECT  113.976 13.711 116.097 13.981 ;
     RECT  113.796 13.981 116.097 14.009 ;
     RECT  207.615 11.749 208.062 14.009 ;
     RECT  113.796 14.009 114.606 14.101 ;
     RECT  99.108 13.405 100.602 14.107 ;
     RECT  218.844 13.085 219.438 14.107 ;
     RECT  220.176 13.339 220.23 14.107 ;
     RECT  117.216 13.711 119.502 14.141 ;
     RECT  106.596 13.945 108.45 14.171 ;
     RECT  110.415 13.469 111.186 14.171 ;
     RECT  117.288 14.141 119.502 14.171 ;
     RECT  99.072 14.107 100.602 14.215 ;
     RECT  1.152 13.567 22.554 14.237 ;
     RECT  110.415 14.171 110.754 14.251 ;
     RECT  121.215 13.369 122.022 14.341 ;
     RECT  112.248 12.091 112.266 14.443 ;
     RECT  125.964 9.553 126.897 14.449 ;
     RECT  113.652 14.101 114.606 14.485 ;
     RECT  111.924 14.443 112.266 14.491 ;
     RECT  125.964 14.449 127.17 14.513 ;
     RECT  218.844 14.107 220.23 14.513 ;
     RECT  110.268 14.251 110.754 14.521 ;
     RECT  111.636 14.491 112.266 14.521 ;
     RECT  113.328 14.485 114.606 14.521 ;
     RECT  122.976 13.405 122.994 14.521 ;
     RECT  123.948 14.251 123.966 14.521 ;
     RECT  106.596 14.171 108.342 14.525 ;
     RECT  103.392 13.973 105.462 14.549 ;
     RECT  0.108 13.853 0.198 14.621 ;
     RECT  111.636 14.521 114.606 14.639 ;
     RECT  0.18 14.621 0.198 14.669 ;
     RECT  98.46 14.215 100.602 14.669 ;
     RECT  102.6 14.413 102.618 14.669 ;
     RECT  103.392 14.549 105.39 14.675 ;
     RECT  211.464 13.829 217.818 14.683 ;
     RECT  218.844 14.513 220.194 14.683 ;
     RECT  110.232 14.521 110.754 14.719 ;
     RECT  211.464 14.683 220.194 14.779 ;
     RECT  103.392 14.675 104.022 14.791 ;
     RECT  110.16 14.719 110.754 14.791 ;
     RECT  98.604 14.669 100.602 14.819 ;
     RECT  104.904 14.675 105.39 14.819 ;
     RECT  120.528 14.341 122.022 14.819 ;
     RECT  117.576 14.171 119.502 14.881 ;
     RECT  211.248 14.779 220.194 14.909 ;
     RECT  110.088 14.791 110.754 14.953 ;
     RECT  211.248 14.909 219.366 14.981 ;
     RECT  1.836 14.237 22.554 14.989 ;
     RECT  23.616 13.981 29.697 14.989 ;
     RECT  117.576 14.881 119.574 14.989 ;
     RECT  120.528 14.819 121.497 14.989 ;
     RECT  210.348 14.647 210.366 14.989 ;
     RECT  117.576 14.989 121.497 15.017 ;
     RECT  106.596 14.525 106.614 15.025 ;
     RECT  107.748 14.525 108.342 15.053 ;
     RECT  117.576 15.017 119.142 15.053 ;
     RECT  101.484 12.523 101.502 15.061 ;
     RECT  210.348 14.989 210.438 15.061 ;
     RECT  211.248 14.981 218.934 15.061 ;
     RECT  1.836 14.989 29.697 15.163 ;
     RECT  106.524 15.025 106.614 15.179 ;
     RECT  107.748 15.053 108.09 15.215 ;
     RECT  111.852 14.639 114.606 15.215 ;
     RECT  122.976 14.521 123.966 15.251 ;
     RECT  220.176 14.909 220.194 15.259 ;
     RECT  134.496 15.163 134.514 15.293 ;
     RECT  210.348 15.061 218.934 15.293 ;
     RECT  207.615 14.009 207.897 15.331 ;
     RECT  101.484 15.061 102.006 15.359 ;
     RECT  117.576 15.053 119.034 15.359 ;
     RECT  112.752 15.215 114.606 15.421 ;
     RECT  117.576 15.359 118.998 15.449 ;
     RECT  148.215 2.413 148.497 15.493 ;
     RECT  98.64 14.819 100.602 15.521 ;
     RECT  101.988 15.359 102.006 15.521 ;
     RECT  112.752 15.421 114.678 15.521 ;
     RECT  78.015 2.413 78.297 15.547 ;
     RECT  210.384 15.293 218.934 15.593 ;
     RECT  103.14 14.791 104.022 15.601 ;
     RECT  218.772 15.593 218.934 15.629 ;
     RECT  220.176 15.259 220.23 15.643 ;
     RECT  120.132 15.017 121.497 15.719 ;
     RECT  77.544 15.547 78.678 15.725 ;
     RECT  109.476 14.953 110.754 15.725 ;
     RECT  1.764 15.163 29.697 15.739 ;
     RECT  147.744 15.493 148.497 15.739 ;
     RECT  220.14 15.643 220.23 15.739 ;
     RECT  88.815 2.413 89.097 15.763 ;
     RECT  126.216 14.513 127.17 15.791 ;
     RECT  146.484 15.493 146.502 15.799 ;
     RECT  0.144 15.643 0.162 15.821 ;
     RECT  77.256 15.727 77.274 15.821 ;
     RECT  117.972 15.449 118.998 15.827 ;
     RECT  146.484 15.799 146.574 15.827 ;
     RECT  206.388 15.691 206.406 15.827 ;
     RECT  210.384 15.593 218.034 15.827 ;
     RECT  110.268 15.725 110.754 15.835 ;
     RECT  218.88 15.629 218.934 15.835 ;
     RECT  220.104 15.739 220.23 15.835 ;
     RECT  108.072 15.215 108.09 15.871 ;
     RECT  131.076 15.259 131.094 15.871 ;
     RECT  147.6 15.739 148.497 15.871 ;
     RECT  112.752 15.521 114.642 15.899 ;
     RECT  118.116 15.827 118.998 15.899 ;
     RECT  146.556 15.827 146.574 15.899 ;
     RECT  98.748 15.521 100.602 15.961 ;
     RECT  103.032 15.601 104.022 15.961 ;
     RECT  104.904 14.819 105.297 15.961 ;
     RECT  147.528 15.871 148.497 15.961 ;
     RECT  98.748 15.961 100.674 15.989 ;
     RECT  122.976 15.251 122.994 15.989 ;
     RECT  147.528 15.961 149.166 16.013 ;
     RECT  102.312 15.961 105.297 16.025 ;
     RECT  111.852 15.215 111.87 16.025 ;
     RECT  88.815 15.763 89.514 16.141 ;
     RECT  110.268 15.835 110.898 16.141 ;
     RECT  118.584 15.899 118.998 16.169 ;
     RECT  110.268 16.141 110.97 16.231 ;
     RECT  97.344 15.565 97.362 16.259 ;
     RECT  94.215 2.413 94.497 16.267 ;
     RECT  112.896 15.899 114.642 16.267 ;
     RECT  115.815 14.009 116.097 16.267 ;
     RECT  207.615 15.331 208.062 16.295 ;
     RECT  110.268 16.231 111.042 16.303 ;
     RECT  106.632 15.295 106.686 16.339 ;
     RECT  108.072 15.871 108.306 16.339 ;
     RECT  112.896 16.267 116.097 16.367 ;
     RECT  120.204 15.719 121.497 16.403 ;
     RECT  97.416 16.267 97.434 16.411 ;
     RECT  94.215 16.267 94.806 16.439 ;
     RECT  97.416 16.411 97.83 16.501 ;
     RECT  109.476 15.725 109.494 16.501 ;
     RECT  110.268 16.303 111.114 16.501 ;
     RECT  218.88 15.835 220.23 16.507 ;
     RECT  97.416 16.501 97.938 16.529 ;
     RECT  109.476 16.501 111.114 16.529 ;
     RECT  112.896 16.367 112.914 16.529 ;
     RECT  114.12 16.367 116.097 16.529 ;
     RECT  210.852 15.827 218.034 16.529 ;
     RECT  100.656 15.989 100.674 16.537 ;
     RECT  106.632 16.339 106.794 16.537 ;
     RECT  135.108 16.069 135.126 16.565 ;
     RECT  94.215 16.439 94.698 16.573 ;
     RECT  210.852 16.529 217.854 16.573 ;
     RECT  97.92 16.529 97.938 16.609 ;
     RECT  98.748 15.989 99.897 16.609 ;
     RECT  106.596 16.537 106.794 16.609 ;
     RECT  107.748 16.339 108.306 16.609 ;
     RECT  114.624 16.529 116.097 16.673 ;
     RECT  118.62 16.169 118.998 16.673 ;
     RECT  120.204 16.403 120.33 16.673 ;
     RECT  93.564 16.573 94.698 16.681 ;
     RECT  109.584 16.529 111.114 16.681 ;
     RECT  97.92 16.609 99.897 16.685 ;
     RECT  206.352 16.681 206.37 16.771 ;
     RECT  218.844 16.507 220.23 16.795 ;
     RECT  93.024 16.681 94.698 16.799 ;
     RECT  106.596 16.609 108.306 16.799 ;
     RECT  130.536 15.871 131.094 16.807 ;
     RECT  207.615 16.295 207.897 16.807 ;
     RECT  109.584 16.681 111.15 16.835 ;
     RECT  58.068 16.411 58.086 16.843 ;
     RECT  102.312 16.025 102.69 16.843 ;
     RECT  103.428 16.025 105.297 16.843 ;
     RECT  93.564 16.799 94.698 16.871 ;
     RECT  210.348 16.573 217.854 16.871 ;
     RECT  0.144 16.699 0.162 16.877 ;
     RECT  123.192 16.141 123.21 16.879 ;
     RECT  109.656 16.835 111.15 16.907 ;
     RECT  123.948 15.251 123.966 16.907 ;
     RECT  207.612 16.807 207.897 16.907 ;
     RECT  108.072 16.799 108.306 16.915 ;
     RECT  108.072 16.915 108.846 16.943 ;
     RECT  98.676 16.685 99.897 16.951 ;
     RECT  100.656 16.537 101.142 16.951 ;
     RECT  118.944 16.673 118.998 16.951 ;
     RECT  102.312 16.843 105.297 16.979 ;
     RECT  106.596 16.799 107.19 16.979 ;
     RECT  109.656 16.907 110.898 16.979 ;
     RECT  126.216 15.791 126.897 16.979 ;
     RECT  206.352 16.771 206.406 16.979 ;
     RECT  98.676 16.951 101.142 17.032 ;
     RECT  1.728 15.739 29.697 17.041 ;
     RECT  30.456 13.567 30.474 17.041 ;
     RECT  98.676 17.032 101.178 17.069 ;
     RECT  102.348 16.979 105.297 17.069 ;
     RECT  118.944 16.951 119.394 17.069 ;
     RECT  122.544 16.879 123.21 17.069 ;
     RECT  1.728 17.041 30.474 17.077 ;
     RECT  99.216 17.069 101.07 17.105 ;
     RECT  102.348 17.069 104.022 17.105 ;
     RECT  1.152 17.077 30.474 17.117 ;
     RECT  64.224 16.951 64.242 17.141 ;
     RECT  124.812 15.799 124.83 17.141 ;
     RECT  90.684 16.771 90.702 17.149 ;
     RECT  118.944 17.069 119.322 17.249 ;
     RECT  130.536 16.807 131.166 17.249 ;
     RECT  39.6 11.281 40.497 17.311 ;
     RECT  118.944 17.249 119.034 17.339 ;
     RECT  122.616 17.069 123.21 17.339 ;
     RECT  218.808 16.795 220.23 17.371 ;
     RECT  116.856 15.799 116.91 17.375 ;
     RECT  211.032 16.871 217.854 17.383 ;
     RECT  218.772 17.371 220.23 17.383 ;
     RECT  0.108 17.275 0.126 17.405 ;
     RECT  120.204 16.673 120.222 17.411 ;
     RECT  130.608 17.249 131.166 17.419 ;
     RECT  132.015 2.413 132.297 17.419 ;
     RECT  99.216 17.105 100.674 17.447 ;
     RECT  139.644 16.411 139.662 17.447 ;
     RECT  90.648 17.149 90.702 17.455 ;
     RECT  96.3 16.843 96.318 17.455 ;
     RECT  103.212 17.105 104.022 17.483 ;
     RECT  86.76 17.455 86.778 17.491 ;
     RECT  210.204 17.383 210.222 17.519 ;
     RECT  93.564 16.871 94.497 17.609 ;
     RECT  135.648 17.077 135.666 17.653 ;
     RECT  90.648 17.455 90.738 17.681 ;
     RECT  130.608 17.419 132.297 17.681 ;
     RECT  93.636 17.609 94.497 17.689 ;
     RECT  56.415 2.413 56.697 17.725 ;
     RECT  97.92 16.685 97.938 17.753 ;
     RECT  60.084 17.491 60.102 17.761 ;
     RECT  211.032 17.383 220.23 17.761 ;
     RECT  60.084 17.761 60.75 17.789 ;
     RECT  84.924 16.105 84.942 17.789 ;
     RECT  107.172 16.979 107.19 17.851 ;
     RECT  107.172 17.851 107.262 17.879 ;
     RECT  115.092 16.673 116.097 17.879 ;
     RECT  56.016 17.725 56.697 17.915 ;
     RECT  57.528 16.843 58.086 17.915 ;
     RECT  60.732 17.789 60.75 17.915 ;
     RECT  122.652 17.339 123.21 17.923 ;
     RECT  83.415 2.413 83.697 17.959 ;
     RECT  210.996 17.761 220.23 17.959 ;
     RECT  96.3 17.455 96.354 17.995 ;
     RECT  126.504 16.979 126.897 17.995 ;
     RECT  39.348 17.311 40.497 18.023 ;
     RECT  116.856 17.375 116.874 18.023 ;
     RECT  95.868 17.995 96.354 18.031 ;
     RECT  60.84 17.959 60.858 18.059 ;
     RECT  86.688 17.491 86.778 18.121 ;
     RECT  88.815 16.141 89.55 18.121 ;
     RECT  102.348 17.105 102.366 18.149 ;
     RECT  183.852 18.121 183.87 18.173 ;
     RECT  86.652 18.121 86.778 18.193 ;
     RECT  153.615 2.413 153.897 18.193 ;
     RECT  86.652 18.193 87.318 18.221 ;
     RECT  88.815 18.121 89.586 18.221 ;
     RECT  107.244 17.879 107.262 18.221 ;
     RECT  130.608 17.681 130.626 18.257 ;
     RECT  210.348 17.959 220.23 18.265 ;
     RECT  103.212 17.483 103.23 18.301 ;
     RECT  39.348 18.023 39.366 18.329 ;
     RECT  93.636 17.689 94.77 18.391 ;
     RECT  131.364 17.681 132.297 18.419 ;
     RECT  93.636 18.391 94.842 18.491 ;
     RECT  108.288 16.943 108.846 18.491 ;
     RECT  115.2 17.879 116.097 18.527 ;
     RECT  135.108 17.653 135.666 18.527 ;
     RECT  99.576 17.447 100.674 18.563 ;
     RECT  1.728 17.117 30.474 18.599 ;
     RECT  206.352 16.979 206.37 18.661 ;
     RECT  95.868 18.031 96.462 18.689 ;
     RECT  176.868 18.661 176.886 18.701 ;
     RECT  95.976 18.689 96.462 18.769 ;
     RECT  207.615 16.907 207.897 18.769 ;
     RECT  112.68 17.725 112.698 18.805 ;
     RECT  1.764 18.599 30.474 18.833 ;
     RECT  113.976 18.301 113.994 18.833 ;
     RECT  87.3 18.221 87.318 18.931 ;
     RECT  57.564 17.915 57.582 18.955 ;
     RECT  56.16 17.915 56.697 18.959 ;
     RECT  87.3 18.931 87.39 18.959 ;
     RECT  95.976 18.769 96.534 18.959 ;
     RECT  207.615 18.769 208.062 18.967 ;
     RECT  207.612 18.967 208.062 19.003 ;
     RECT  92.88 18.733 92.898 19.039 ;
     RECT  121.215 16.403 121.497 19.039 ;
     RECT  206.352 18.661 206.406 19.039 ;
     RECT  125.964 17.995 126.897 19.067 ;
     RECT  207.612 19.003 208.134 19.067 ;
     RECT  210.348 18.265 220.302 19.103 ;
     RECT  153.615 18.193 154.458 19.111 ;
     RECT  1.764 18.833 29.697 19.139 ;
     RECT  206.352 19.039 206.442 19.139 ;
     RECT  92.304 19.039 92.898 19.201 ;
     RECT  82.908 17.959 83.697 19.229 ;
     RECT  129.312 18.229 129.33 19.229 ;
     RECT  206.352 19.139 206.37 19.229 ;
     RECT  207.615 19.067 208.134 19.229 ;
     RECT  91.98 19.201 92.898 19.237 ;
     RECT  1.8 19.139 29.697 19.265 ;
     RECT  119.016 17.339 119.034 19.273 ;
     RECT  121.215 19.039 121.914 19.273 ;
     RECT  122.652 17.923 123.714 19.273 ;
     RECT  91.8 19.237 92.898 19.301 ;
     RECT  121.215 19.273 123.714 19.301 ;
     RECT  130.536 18.463 130.554 19.301 ;
     RECT  1.8 19.265 8.658 19.373 ;
     RECT  118.584 19.273 119.034 19.373 ;
     RECT  121.215 19.301 123.21 19.373 ;
     RECT  148.215 16.013 148.497 19.381 ;
     RECT  91.8 19.301 92.322 19.409 ;
     RECT  67.215 2.413 67.497 19.471 ;
     RECT  104.004 17.483 104.022 19.471 ;
     RECT  105.015 17.069 105.297 19.471 ;
     RECT  69.372 18.967 69.39 19.499 ;
     RECT  112.68 18.805 112.842 19.499 ;
     RECT  61.815 2.413 62.097 19.507 ;
     RECT  67.215 19.471 67.554 19.517 ;
     RECT  184.68 18.121 184.698 19.517 ;
     RECT  6.516 19.373 8.658 19.571 ;
     RECT  98.604 19.471 98.622 19.571 ;
     RECT  102.564 18.301 103.23 19.571 ;
     RECT  74.88 19.003 74.898 19.579 ;
     RECT  1.8 19.373 5.742 19.607 ;
     RECT  153.615 19.111 154.638 19.615 ;
     RECT  1.8 19.607 5.598 19.643 ;
     RECT  57.528 18.955 57.582 19.651 ;
     RECT  9.396 19.265 29.697 19.679 ;
     RECT  61.815 19.507 62.73 19.679 ;
     RECT  210.384 19.103 220.302 19.679 ;
     RECT  115.815 18.527 116.097 19.741 ;
     RECT  153.615 19.615 154.854 19.741 ;
     RECT  74.88 19.579 74.97 19.769 ;
     RECT  91.98 19.409 92.322 19.769 ;
     RECT  117.684 18.769 117.702 19.769 ;
     RECT  126.288 19.067 126.897 19.769 ;
     RECT  139.932 19.615 139.95 19.769 ;
     RECT  60.228 19.768 60.246 19.805 ;
     RECT  177.192 18.841 177.21 19.805 ;
     RECT  54.72 19.651 54.738 19.813 ;
     RECT  57.528 19.651 57.69 19.841 ;
     RECT  115.815 19.741 116.262 19.853 ;
     RECT  153.468 19.741 154.854 19.853 ;
     RECT  54.72 19.813 54.81 19.913 ;
     RECT  57.6 19.841 57.69 19.913 ;
     RECT  112.752 19.499 112.842 19.921 ;
     RECT  141.876 19.741 141.894 19.921 ;
     RECT  90.648 19.381 90.666 19.949 ;
     RECT  126.36 19.769 126.897 19.949 ;
     RECT  153.468 19.853 154.458 19.949 ;
     RECT  28.188 19.679 29.697 19.997 ;
     RECT  34.815 2.413 35.097 19.997 ;
     RECT  40.215 18.023 40.497 19.997 ;
     RECT  45.615 2.413 45.897 19.997 ;
     RECT  51.015 2.413 51.297 19.997 ;
     RECT  56.415 18.959 56.697 19.997 ;
     RECT  61.815 19.679 62.097 19.997 ;
     RECT  67.215 19.517 67.497 19.997 ;
     RECT  72.615 2.413 72.897 19.997 ;
     RECT  78.015 15.725 78.297 19.997 ;
     RECT  88.815 18.221 89.097 19.997 ;
     RECT  115.815 19.853 116.097 19.997 ;
     RECT  121.215 19.373 122.022 19.997 ;
     RECT  126.615 19.949 126.897 19.997 ;
     RECT  131.436 18.419 132.297 19.997 ;
     RECT  137.415 2.413 137.697 19.997 ;
     RECT  159.015 2.413 159.297 19.997 ;
     RECT  164.415 2.413 164.697 19.997 ;
     RECT  169.815 2.413 170.097 19.997 ;
     RECT  175.215 2.413 175.497 19.997 ;
     RECT  180.615 2.413 180.897 19.997 ;
     RECT  186.015 2.413 186.297 19.997 ;
     RECT  191.415 2.413 191.697 19.997 ;
     RECT  196.815 2.413 197.097 19.997 ;
     RECT  78.207 19.997 78.297 20.011 ;
     RECT  79.2 19.075 79.218 20.011 ;
     RECT  93.636 18.491 94.497 20.011 ;
     RECT  139.644 19.921 139.662 20.011 ;
     RECT  141.552 19.921 141.894 20.011 ;
     RECT  142.815 2.413 143.097 20.011 ;
     RECT  147.78 19.381 148.497 20.011 ;
     RECT  190.404 19.813 190.422 20.011 ;
     RECT  191.607 19.997 191.697 20.011 ;
     RECT  1.8 19.643 5.238 20.039 ;
     RECT  83.415 19.229 83.697 20.047 ;
     RECT  139.608 20.011 139.662 20.047 ;
     RECT  140.796 20.011 140.814 20.047 ;
     RECT  190.404 20.011 190.494 20.047 ;
     RECT  1.8 20.039 4.266 20.059 ;
     RECT  1.728 20.059 4.266 20.075 ;
     RECT  207.615 19.229 208.062 20.075 ;
     RECT  210.6 19.679 220.302 20.075 ;
     RECT  145.656 19.921 145.674 20.111 ;
     RECT  138.6 20.047 139.662 20.119 ;
     RECT  199.764 19.777 199.782 20.119 ;
     RECT  75.204 20.011 75.294 20.141 ;
     RECT  191.607 20.011 192.474 20.141 ;
     RECT  138.528 20.119 139.662 20.147 ;
     RECT  146.412 20.047 146.43 20.147 ;
     RECT  191.607 20.141 192.114 20.147 ;
     RECT  78.207 20.011 79.218 20.191 ;
     RECT  143.928 19.921 144.27 20.191 ;
     RECT  147.78 20.011 148.806 20.191 ;
     RECT  82.728 20.047 83.697 20.219 ;
     RECT  141.552 20.011 143.097 20.219 ;
     RECT  190.404 20.047 190.53 20.219 ;
     RECT  191.607 20.147 191.754 20.219 ;
     RECT  29.607 19.997 29.697 20.267 ;
     RECT  35.007 19.997 35.097 20.267 ;
     RECT  40.407 19.997 40.497 20.267 ;
     RECT  45.807 19.997 45.897 20.267 ;
     RECT  51.207 19.997 51.297 20.267 ;
     RECT  56.556 19.997 56.697 20.267 ;
     RECT  62.007 19.997 62.097 20.267 ;
     RECT  67.407 19.997 67.497 20.267 ;
     RECT  72.807 19.997 72.897 20.267 ;
     RECT  78.207 20.191 79.29 20.267 ;
     RECT  82.872 20.219 83.697 20.267 ;
     RECT  89.007 19.997 89.097 20.267 ;
     RECT  93.6 20.011 94.497 20.267 ;
     RECT  99.576 18.563 99.897 20.267 ;
     RECT  104.004 19.471 105.297 20.267 ;
     RECT  116.007 19.997 116.097 20.267 ;
     RECT  121.407 19.997 122.022 20.267 ;
     RECT  126.807 19.997 126.897 20.267 ;
     RECT  132.207 19.997 132.297 20.267 ;
     RECT  137.607 19.997 137.697 20.267 ;
     RECT  143.007 20.219 143.097 20.267 ;
     RECT  147.6 20.191 148.806 20.267 ;
     RECT  153.468 19.949 153.897 20.267 ;
     RECT  159.207 19.997 159.297 20.267 ;
     RECT  164.607 19.997 164.697 20.267 ;
     RECT  170.007 19.997 170.097 20.267 ;
     RECT  175.407 19.997 175.497 20.267 ;
     RECT  180.807 19.997 180.897 20.267 ;
     RECT  186.207 19.997 186.297 20.267 ;
     RECT  191.607 20.219 191.697 20.267 ;
     RECT  197.007 19.997 197.097 20.267 ;
     RECT  70.776 20.047 70.794 20.281 ;
     RECT  75.276 20.141 75.294 20.281 ;
     RECT  5.22 20.039 5.238 20.309 ;
     RECT  70.704 20.281 70.794 20.309 ;
     RECT  75.276 20.281 75.366 20.309 ;
     RECT  93.6 20.267 93.726 20.309 ;
     RECT  139.284 20.147 139.662 20.309 ;
     RECT  182.916 20.155 182.934 20.309 ;
     RECT  190.512 20.219 190.53 20.309 ;
     RECT  193.356 20.047 193.374 20.309 ;
     RECT  112.752 19.921 112.95 20.345 ;
     RECT  141.552 20.219 142.11 20.345 ;
     RECT  56.556 20.267 56.574 20.381 ;
     RECT  70.704 20.309 70.722 20.381 ;
     RECT  75.348 20.309 75.366 20.381 ;
     RECT  138.528 20.147 138.546 20.381 ;
     RECT  146.34 20.191 146.358 20.381 ;
     RECT  210.6 20.075 220.23 20.381 ;
     RECT  78.66 20.267 79.29 20.453 ;
     RECT  82.872 20.267 82.89 20.453 ;
     RECT  210.6 20.381 219.438 20.453 ;
     RECT  140.472 20.047 140.814 20.489 ;
     RECT  210.6 20.453 217.746 20.587 ;
     RECT  9.396 19.679 27.054 20.723 ;
     RECT  218.808 20.453 219.438 20.723 ;
     RECT  6.516 19.571 8.514 20.731 ;
     RECT  60.444 19.921 60.462 20.759 ;
     RECT  91.98 19.769 91.998 20.804 ;
     RECT  153.468 20.267 153.486 20.813 ;
     RECT  147.6 20.267 147.87 20.849 ;
     RECT  122.004 20.267 122.022 20.921 ;
     RECT  139.608 20.309 139.662 20.957 ;
     RECT  79.272 20.453 79.29 20.993 ;
     RECT  93.6 20.309 93.618 20.993 ;
     RECT  206.352 20.731 206.37 20.993 ;
     RECT  80.136 20.011 80.154 21.029 ;
     RECT  9.396 20.723 25.938 21.074 ;
     RECT  210.312 20.587 217.746 21.091 ;
     RECT  209.772 21.091 217.746 21.163 ;
     RECT  9.396 21.074 24.786 21.191 ;
     RECT  1.728 20.075 4.122 21.235 ;
     RECT  25.92 21.074 25.938 21.299 ;
     RECT  102.564 19.571 102.582 21.316 ;
     RECT  102.024 21.316 102.582 21.344 ;
     RECT  6.012 20.731 8.514 21.352 ;
     RECT  9.396 21.191 24.75 21.352 ;
     RECT  1.728 21.235 4.194 21.361 ;
     RECT  123.012 19.373 123.21 21.389 ;
     RECT  141.552 20.345 141.57 21.389 ;
     RECT  147.852 20.849 147.87 21.389 ;
     RECT  139.644 20.957 139.662 21.425 ;
     RECT  135.072 18.535 135.09 21.437 ;
     RECT  102.024 21.344 102.042 21.461 ;
     RECT  143.928 20.191 144.558 21.461 ;
     RECT  131.436 19.997 131.454 21.485 ;
     RECT  95.976 18.959 95.994 21.497 ;
     RECT  205.776 21.397 206.298 21.497 ;
     RECT  87.372 18.959 87.39 21.533 ;
     RECT  129.384 19.381 129.402 21.533 ;
     RECT  69.444 19.651 69.462 21.569 ;
     RECT  209.124 21.163 217.746 21.631 ;
     RECT  27.036 20.723 27.054 21.659 ;
     RECT  218.844 20.723 219.438 21.787 ;
     RECT  220.176 20.381 220.23 21.787 ;
     RECT  1.728 21.361 4.41 21.811 ;
     RECT  209.124 21.631 218.034 21.883 ;
     RECT  218.844 21.787 220.23 21.883 ;
     RECT  1.728 21.811 4.698 21.929 ;
     RECT  207.615 20.075 207.897 22.009 ;
     RECT  1.728 21.929 4.662 22.199 ;
     RECT  6.012 21.352 24.75 22.235 ;
     RECT  4.644 22.199 4.662 22.271 ;
     RECT  9.396 22.235 24.75 22.464 ;
     RECT  28.188 19.997 28.782 22.464 ;
     RECT  30.456 18.833 30.474 22.464 ;
     RECT  99.576 20.267 99.594 22.464 ;
     RECT  100.656 18.563 100.674 22.464 ;
     RECT  104.004 20.267 104.526 22.464 ;
     RECT  108.288 18.491 108.306 22.464 ;
     RECT  110.268 16.979 110.898 22.464 ;
     RECT  112.752 20.345 112.77 22.464 ;
     RECT  116.856 19.921 116.874 22.464 ;
     RECT  119.016 19.373 119.034 22.464 ;
     RECT  123.084 21.389 123.21 22.464 ;
     RECT  140.472 20.489 140.49 22.464 ;
     RECT  144.54 21.461 144.558 22.464 ;
     RECT  148.788 20.267 148.806 22.464 ;
     RECT  209.124 21.883 220.23 22.577 ;
     RECT  1.728 22.199 3.618 23.017 ;
     RECT  1.728 23.017 3.978 23.089 ;
     RECT  4.86 23.017 4.878 23.089 ;
     RECT  9.396 22.464 197.448 23.131 ;
     RECT  6.012 22.235 8.442 23.251 ;
     RECT  1.728 23.089 4.878 23.279 ;
     RECT  209.124 22.577 219.366 23.315 ;
     RECT  218.844 23.315 219.366 23.323 ;
     RECT  220.14 22.577 220.23 23.323 ;
     RECT  9.396 23.131 197.55 23.431 ;
     RECT  209.124 23.315 218.034 23.459 ;
     RECT  206.28 21.497 206.298 23.521 ;
     RECT  5.904 23.251 8.442 23.557 ;
     RECT  9.396 23.431 197.586 23.563 ;
     RECT  206.28 23.521 206.37 23.621 ;
     RECT  207.252 22.009 207.897 23.665 ;
     RECT  5.76 23.557 8.442 23.701 ;
     RECT  9.396 23.563 197.658 23.947 ;
     RECT  203.256 21.973 203.274 24.089 ;
     RECT  206.28 23.621 206.298 24.089 ;
     RECT  218.844 23.323 220.23 24.125 ;
     RECT  202.215 2.413 202.497 24.205 ;
     RECT  218.844 24.125 220.158 24.233 ;
     RECT  1.764 23.279 4.482 24.241 ;
     RECT  220.14 24.233 220.158 24.269 ;
     RECT  1.764 24.241 4.626 24.283 ;
     RECT  1.728 24.283 4.626 24.331 ;
     RECT  5.364 23.701 8.442 24.331 ;
     RECT  1.728 24.331 8.442 24.395 ;
     RECT  5.184 24.395 8.442 24.467 ;
     RECT  9.396 23.947 197.694 24.605 ;
     RECT  218.844 24.233 219.402 24.763 ;
     RECT  5.364 24.467 8.442 24.773 ;
     RECT  1.728 24.395 4.41 24.899 ;
     RECT  209.448 23.459 218.034 24.899 ;
     RECT  207.252 23.665 208.35 24.941 ;
     RECT  0.288 24.859 0.306 24.955 ;
     RECT  218.808 24.763 219.402 24.955 ;
     RECT  0.108 24.955 0.306 24.989 ;
     RECT  218.808 24.955 219.438 25.043 ;
     RECT  6.444 24.773 8.442 25.051 ;
     RECT  9.396 24.605 197.622 25.051 ;
     RECT  199.764 20.119 199.818 25.051 ;
     RECT  199.62 25.051 199.818 25.079 ;
     RECT  0.108 24.989 0.126 25.085 ;
     RECT  209.448 24.899 217.854 25.177 ;
     RECT  220.212 24.859 220.23 25.205 ;
     RECT  5.364 24.773 5.706 25.285 ;
     RECT  209.16 25.177 217.854 25.321 ;
     RECT  1.728 24.899 4.122 25.349 ;
     RECT  6.444 25.051 197.622 25.349 ;
     RECT  1.764 25.349 4.122 25.439 ;
     RECT  201.456 21.433 201.474 25.439 ;
     RECT  207.252 24.941 207.897 25.439 ;
     RECT  209.124 25.321 217.854 25.439 ;
     RECT  206.136 24.205 206.154 25.447 ;
     RECT  9.396 25.349 197.622 25.469 ;
     RECT  209.124 25.439 209.178 25.519 ;
     RECT  206.136 25.447 206.406 25.547 ;
     RECT  199.62 25.079 199.782 25.619 ;
     RECT  210.168 25.439 217.854 25.619 ;
     RECT  9.432 25.469 197.622 25.661 ;
     RECT  206.136 25.547 206.154 25.681 ;
     RECT  210.204 25.619 217.854 25.805 ;
     RECT  5.22 25.285 5.706 25.889 ;
     RECT  1.764 25.439 4.05 26.015 ;
     RECT  207.615 25.439 207.897 26.023 ;
     RECT  208.62 25.519 209.178 26.023 ;
     RECT  204.588 23.593 204.606 26.045 ;
     RECT  219.384 25.043 219.438 26.095 ;
     RECT  1.764 26.015 3.546 26.159 ;
     RECT  218.88 26.095 219.438 26.203 ;
     RECT  218.844 26.203 219.438 26.321 ;
     RECT  206.028 25.681 206.154 26.347 ;
     RECT  2.304 26.159 3.546 26.357 ;
     RECT  218.844 26.321 219.402 26.392 ;
     RECT  2.376 26.357 3.546 26.393 ;
     RECT  9.432 25.661 197.55 26.491 ;
     RECT  2.376 26.393 2.934 26.519 ;
     RECT  206.028 26.347 206.37 26.525 ;
     RECT  210.312 25.805 217.854 26.527 ;
     RECT  210.096 26.527 217.854 26.563 ;
     RECT  218.808 26.392 219.402 26.591 ;
     RECT  2.415 26.519 2.934 26.663 ;
     RECT  202.215 24.205 203.13 26.663 ;
     RECT  210.024 26.563 217.854 26.789 ;
     RECT  220.212 26.491 220.23 26.897 ;
     RECT  210.852 26.789 217.854 26.969 ;
     RECT  212.688 26.969 217.854 27.059 ;
     RECT  212.688 27.059 214.758 27.095 ;
     RECT  210.852 26.969 211.878 27.101 ;
     RECT  218.844 26.591 219.402 27.131 ;
     RECT  215.496 27.059 217.854 27.167 ;
     RECT  217.836 27.167 217.854 27.175 ;
     RECT  217.836 27.175 218.034 27.203 ;
     RECT  219.384 27.131 219.402 27.239 ;
     RECT  215.496 27.167 216.954 27.329 ;
     RECT  218.016 27.203 218.034 27.329 ;
     RECT  215.712 27.329 216.954 27.341 ;
     RECT  207.615 26.023 209.178 27.485 ;
     RECT  206.028 26.525 206.046 27.595 ;
     RECT  215.712 27.341 216.774 27.599 ;
     RECT  211.284 27.101 211.878 27.629 ;
     RECT  207.615 27.485 209.142 27.725 ;
     RECT  206.028 27.595 206.37 27.773 ;
     RECT  212.94 27.095 214.758 27.779 ;
     RECT  214.668 27.779 214.758 27.835 ;
     RECT  215.712 27.599 216.486 27.869 ;
     RECT  214.668 27.835 214.866 27.905 ;
     RECT  216.396 27.869 216.414 27.905 ;
     RECT  212.94 27.779 213.894 27.931 ;
     RECT  9.432 26.491 197.586 28.049 ;
     RECT  214.668 27.905 214.686 28.049 ;
     RECT  212.616 27.931 213.894 28.157 ;
     RECT  213.015 28.157 213.894 28.253 ;
     RECT  207.615 27.725 208.458 28.319 ;
     RECT  9.576 28.049 197.586 28.409 ;
     RECT  207.615 28.319 208.386 28.445 ;
     RECT  210.024 26.789 210.114 28.541 ;
     RECT  211.86 27.629 211.878 28.589 ;
     RECT  210.096 28.541 210.114 28.733 ;
     RECT  6.444 25.349 8.442 28.781 ;
     RECT  199.62 25.619 199.674 29.255 ;
     RECT  11.124 28.409 197.586 29.371 ;
     RECT  6.444 28.781 8.097 31.133 ;
     RECT  7.056 31.133 8.097 31.709 ;
     RECT  11.124 29.371 197.622 31.997 ;
     RECT  199.62 29.255 199.638 32.765 ;
     RECT  7.632 31.709 8.097 32.861 ;
     RECT  11.952 31.997 197.622 32.881 ;
     RECT  11.952 32.881 197.766 33.035 ;
     RECT  11.952 33.035 197.694 33.053 ;
     RECT  11.124 31.997 11.178 33.149 ;
     RECT  9.576 28.409 10.386 33.719 ;
     RECT  10.368 33.719 10.386 34.205 ;
     RECT  9.576 33.719 9.594 34.685 ;
     RECT  11.16 33.149 11.178 35.021 ;
     RECT  206.028 27.773 206.046 35.735 ;
     RECT  11.952 33.053 197.622 35.837 ;
     RECT  14.58 35.837 197.622 36.077 ;
     RECT  7.668 32.861 8.097 36.317 ;
     RECT  11.952 35.837 13.497 36.653 ;
     RECT  11.952 36.653 11.97 36.893 ;
     RECT  5.22 25.889 5.238 37.859 ;
     RECT  14.796 36.077 197.622 37.949 ;
     RECT  14.796 37.949 197.55 38.717 ;
     RECT  14.796 38.717 15.75 39.581 ;
     RECT  16.488 38.717 197.55 40.109 ;
     RECT  17.064 40.109 197.55 40.349 ;
     RECT  199.44 40.135 199.458 40.675 ;
     RECT  17.1 40.349 197.55 41.021 ;
     RECT  14.796 39.581 14.814 41.261 ;
     RECT  199.44 40.675 199.89 41.368 ;
     RECT  198.936 41.368 199.89 41.885 ;
     RECT  17.1 41.021 197.448 41.981 ;
     RECT  198.936 41.885 199.134 42.089 ;
     RECT  199.872 41.885 199.89 42.151 ;
     RECT  18.108 41.981 197.448 42.173 ;
     RECT  198.936 42.089 198.99 42.173 ;
     RECT  20.916 42.173 197.448 42.461 ;
     RECT  18.108 42.173 20.106 42.557 ;
     RECT  199.872 42.151 200.106 42.557 ;
     RECT  199.908 42.557 200.106 42.691 ;
     RECT  199.908 42.691 200.25 42.845 ;
     RECT  198.936 42.173 198.954 42.907 ;
     RECT  198.936 42.907 199.134 43.096 ;
     RECT  199.908 42.845 199.926 43.259 ;
     RECT  17.1 41.981 17.262 43.373 ;
     RECT  20.988 42.461 197.448 43.421 ;
     RECT  17.244 43.373 17.262 43.529 ;
     RECT  18.216 42.557 20.106 43.565 ;
     RECT  198.936 43.096 199.17 43.645 ;
     RECT  21.456 43.421 197.448 43.709 ;
     RECT  198.936 43.645 199.782 43.799 ;
     RECT  22.068 43.709 197.448 43.805 ;
     RECT  18.615 43.565 20.106 43.901 ;
     RECT  22.068 43.805 22.086 43.997 ;
     RECT  18.615 43.901 19.926 44.093 ;
     RECT  18.615 44.093 19.35 44.189 ;
     RECT  198.936 43.799 199.17 44.339 ;
     RECT  199.008 44.339 199.17 44.411 ;
     RECT  199.008 44.411 199.062 44.645 ;
     RECT  199.044 44.645 199.062 44.879 ;
     RECT  15.732 39.581 15.75 47.323 ;
     RECT  15.3 47.323 15.75 47.357 ;
     RECT  15.3 47.357 15.318 47.579 ;
     RECT  13.215 36.653 13.497 47.731 ;
     RECT  5.256 37.975 5.274 50.549 ;
     RECT  23.328 43.805 197.448 52.2 ;
     RECT  24.207 54.253 24.297 54.523 ;
     RECT  29.607 54.253 29.697 54.523 ;
     RECT  35.007 54.253 35.097 54.523 ;
     RECT  40.407 54.253 40.497 54.523 ;
     RECT  45.807 54.253 45.897 54.523 ;
     RECT  51.207 54.253 51.297 54.523 ;
     RECT  56.607 54.253 56.697 54.523 ;
     RECT  62.007 54.253 62.097 54.523 ;
     RECT  67.407 54.253 67.497 54.523 ;
     RECT  72.807 54.253 72.897 54.523 ;
     RECT  78.207 54.253 78.297 54.523 ;
     RECT  83.607 54.253 83.697 54.523 ;
     RECT  89.007 54.253 89.097 54.523 ;
     RECT  94.407 54.253 94.497 54.523 ;
     RECT  99.807 54.253 99.897 54.523 ;
     RECT  105.207 54.253 105.297 54.523 ;
     RECT  110.607 54.253 110.697 54.523 ;
     RECT  116.007 54.253 116.097 54.523 ;
     RECT  121.407 54.253 121.497 54.523 ;
     RECT  126.807 54.253 126.897 54.523 ;
     RECT  132.207 54.253 132.297 54.523 ;
     RECT  137.607 54.253 137.697 54.523 ;
     RECT  143.007 54.253 143.097 54.523 ;
     RECT  148.407 54.253 148.497 54.523 ;
     RECT  153.807 54.253 153.897 54.523 ;
     RECT  159.207 54.253 159.297 54.523 ;
     RECT  164.607 54.253 164.697 54.523 ;
     RECT  170.007 54.253 170.097 54.523 ;
     RECT  175.407 54.253 175.497 54.523 ;
     RECT  180.807 54.253 180.897 54.523 ;
     RECT  186.207 54.253 186.297 54.523 ;
     RECT  191.607 54.253 191.697 54.523 ;
     RECT  197.007 54.253 197.097 54.523 ;
     RECT  5.112 50.665 5.13 63.239 ;
     RECT  2.415 26.663 2.697 73.187 ;
     RECT  7.815 36.317 8.097 73.187 ;
     RECT  13.215 47.731 14.202 73.187 ;
     RECT  18.615 44.189 18.897 73.187 ;
     RECT  24.015 54.523 24.297 73.187 ;
     RECT  29.415 54.523 29.697 73.187 ;
     RECT  34.815 54.523 35.097 73.187 ;
     RECT  40.215 54.523 40.497 73.187 ;
     RECT  45.615 54.523 45.897 73.187 ;
     RECT  51.015 54.523 51.297 73.187 ;
     RECT  56.415 54.523 56.697 73.187 ;
     RECT  61.815 54.523 62.097 73.187 ;
     RECT  67.215 54.523 67.497 73.187 ;
     RECT  72.615 54.523 72.897 73.187 ;
     RECT  78.015 54.523 78.297 73.187 ;
     RECT  83.415 54.523 83.697 73.187 ;
     RECT  88.815 54.523 89.097 73.187 ;
     RECT  94.215 54.523 94.497 73.187 ;
     RECT  99.615 54.523 99.897 73.187 ;
     RECT  105.015 54.523 105.297 73.187 ;
     RECT  110.415 54.523 110.697 73.187 ;
     RECT  115.815 54.523 116.097 73.187 ;
     RECT  121.215 54.523 121.497 73.187 ;
     RECT  126.615 54.523 126.897 73.187 ;
     RECT  132.015 54.523 132.297 73.187 ;
     RECT  137.415 54.523 137.697 73.187 ;
     RECT  142.815 54.523 143.097 73.187 ;
     RECT  148.215 54.523 148.497 73.187 ;
     RECT  153.615 54.523 153.897 73.187 ;
     RECT  159.015 54.523 159.297 73.187 ;
     RECT  164.415 54.523 164.697 73.187 ;
     RECT  169.815 54.523 170.097 73.187 ;
     RECT  175.215 54.523 175.497 73.187 ;
     RECT  180.615 54.523 180.897 73.187 ;
     RECT  186.015 54.523 186.297 73.187 ;
     RECT  191.415 54.523 191.697 73.187 ;
     RECT  196.815 54.523 197.097 73.187 ;
     RECT  202.215 26.663 202.497 73.187 ;
     RECT  207.615 28.445 207.897 73.187 ;
     RECT  213.015 28.253 213.297 73.187 ;
     RECT  2.415 73.187 2.505 73.457 ;
     RECT  7.815 73.187 7.905 73.457 ;
     RECT  13.215 73.187 13.305 73.457 ;
     RECT  18.615 73.187 18.705 73.457 ;
     RECT  24.015 73.187 24.105 73.457 ;
     RECT  29.415 73.187 29.505 73.457 ;
     RECT  34.815 73.187 34.905 73.457 ;
     RECT  40.215 73.187 40.305 73.457 ;
     RECT  45.615 73.187 45.705 73.457 ;
     RECT  51.015 73.187 51.105 73.457 ;
     RECT  56.415 73.187 56.505 73.457 ;
     RECT  61.815 73.187 61.905 73.457 ;
     RECT  67.215 73.187 67.305 73.457 ;
     RECT  72.615 73.187 72.705 73.457 ;
     RECT  78.015 73.187 78.105 73.457 ;
     RECT  83.415 73.187 83.505 73.457 ;
     RECT  88.815 73.187 88.905 73.457 ;
     RECT  94.215 73.187 94.305 73.457 ;
     RECT  99.615 73.187 99.705 73.457 ;
     RECT  105.015 73.187 105.105 73.457 ;
     RECT  110.415 73.187 110.505 73.457 ;
     RECT  115.815 73.187 115.905 73.457 ;
     RECT  121.215 73.187 121.305 73.457 ;
     RECT  126.615 73.187 126.705 73.457 ;
     RECT  132.015 73.187 132.105 73.457 ;
     RECT  137.415 73.187 137.505 73.457 ;
     RECT  142.815 73.187 142.905 73.457 ;
     RECT  148.215 73.187 148.305 73.457 ;
     RECT  153.615 73.187 153.705 73.457 ;
     RECT  159.015 73.187 159.105 73.457 ;
     RECT  164.415 73.187 164.505 73.457 ;
     RECT  169.815 73.187 169.905 73.457 ;
     RECT  175.215 73.187 175.305 73.457 ;
     RECT  180.615 73.187 180.705 73.457 ;
     RECT  186.015 73.187 186.105 73.457 ;
     RECT  191.415 73.187 191.505 73.457 ;
     RECT  196.815 73.187 196.905 73.457 ;
     RECT  202.215 73.187 202.305 73.457 ;
     RECT  207.615 73.187 207.705 73.457 ;
     RECT  213.015 73.187 213.105 73.457 ;
     RECT  5.076 63.355 5.094 74.623 ;
     RECT  5.004 74.623 5.094 74.651 ;
     RECT  14.184 73.187 14.202 75.485 ;
     RECT  4.032 75.451 4.05 75.581 ;
     RECT  5.004 74.651 5.022 75.581 ;
    LAYER M4 ;
     RECT  0.06 4.032 0.097 4.056 ;
     RECT  0.06 5.088 0.097 17.304 ;
     RECT  0.06 18.336 0.097 19.032 ;
     RECT  0.06 24.288 0.097 24.984 ;
     RECT  0.097 4.032 0.137 19.032 ;
     RECT  0.137 4.128 2.408 19.032 ;
     RECT  0.06 20.064 2.408 20.088 ;
     RECT  0.06 21.12 2.408 21.912 ;
     RECT  0.06 22.944 2.408 23.256 ;
     RECT  0.097 24.288 2.408 25.08 ;
     RECT  2.408 2.148 2.512 73.452 ;
     RECT  2.512 2.418 2.704 73.182 ;
     RECT  2.704 5.184 2.873 19.608 ;
     RECT  2.704 24.672 2.909 24.984 ;
     RECT  2.873 18.768 2.981 19.608 ;
     RECT  2.704 4.128 3.089 4.152 ;
     RECT  2.909 24.672 3.413 24.696 ;
     RECT  2.704 21.408 4.025 21.432 ;
     RECT  2.873 5.184 4.097 17.64 ;
     RECT  4.097 5.424 4.133 17.64 ;
     RECT  2.981 18.816 4.277 19.608 ;
     RECT  4.277 19.584 4.313 19.608 ;
     RECT  4.133 5.424 4.349 6.264 ;
     RECT  4.133 7.728 4.489 17.64 ;
     RECT  4.489 7.728 4.601 17.688 ;
     RECT  4.349 5.424 4.637 5.448 ;
     RECT  4.601 8.544 4.709 17.688 ;
     RECT  4.709 8.544 4.817 14.904 ;
     RECT  4.709 16.272 4.853 17.688 ;
     RECT  4.817 9.024 4.925 14.904 ;
     RECT  4.853 16.272 4.925 17.64 ;
     RECT  4.453 23.952 5.101 23.976 ;
     RECT  4.925 9.024 5.105 14.52 ;
     RECT  4.925 16.272 5.285 17.112 ;
     RECT  5.285 16.272 5.321 17.064 ;
     RECT  5.321 17.04 5.609 17.064 ;
     RECT  5.105 9.6 5.717 14.52 ;
     RECT  5.717 10.128 5.753 14.52 ;
     RECT  5.101 23.952 5.789 24.36 ;
     RECT  5.753 10.128 5.933 12.504 ;
     RECT  5.753 13.536 6.041 14.52 ;
     RECT  6.041 13.92 6.397 14.52 ;
     RECT  6.253 17.424 6.577 17.448 ;
     RECT  5.857 5.424 6.685 5.448 ;
     RECT  6.577 7.632 6.721 7.656 ;
     RECT  6.685 5.232 6.797 5.448 ;
     RECT  6.721 7.632 6.829 7.752 ;
     RECT  6.397 13.92 6.901 15.336 ;
     RECT  6.433 31.104 7.045 31.128 ;
     RECT  6.577 16.896 7.153 17.64 ;
     RECT  6.433 8.976 7.225 9 ;
     RECT  7.225 8.928 7.477 9 ;
     RECT  6.797 5.424 7.549 5.448 ;
     RECT  5.789 24.096 7.549 24.36 ;
     RECT  6.829 6.912 7.585 7.752 ;
     RECT  7.477 8.928 7.585 9.048 ;
     RECT  7.549 5.424 7.693 5.496 ;
     RECT  7.693 5.424 7.808 5.592 ;
     RECT  7.585 6.912 7.808 9.048 ;
     RECT  5.933 10.128 7.808 11.688 ;
     RECT  6.901 13.92 7.808 15.48 ;
     RECT  7.153 16.608 7.808 17.64 ;
     RECT  6.937 18.816 7.808 18.84 ;
     RECT  6.289 21.408 7.808 21.432 ;
     RECT  7.549 24.096 7.808 24.504 ;
     RECT  7.477 26.352 7.808 26.376 ;
     RECT  7.045 31.104 7.808 31.704 ;
     RECT  7.621 32.832 7.808 32.856 ;
     RECT  7.657 36.288 7.808 36.312 ;
     RECT  7.808 2.148 7.912 73.452 ;
     RECT  7.912 2.418 8.104 73.182 ;
     RECT  8.104 21.36 8.597 21.432 ;
     RECT  8.104 18.816 8.705 18.984 ;
     RECT  8.104 5.472 8.741 9.96 ;
     RECT  8.104 11.664 9.137 14.184 ;
     RECT  8.741 5.472 9.169 7.752 ;
     RECT  9.169 5.424 9.353 7.752 ;
     RECT  8.104 24.48 9.385 24.744 ;
     RECT  8.104 26.352 9.385 26.376 ;
     RECT  9.353 5.712 9.425 7.752 ;
     RECT  9.137 11.952 9.565 14.184 ;
     RECT  8.104 15.456 9.565 17.208 ;
     RECT  9.565 11.952 9.569 17.208 ;
     RECT  9.569 11.952 9.641 16.008 ;
     RECT  9.569 17.088 9.709 17.208 ;
     RECT  9.709 17.088 9.749 17.64 ;
     RECT  8.741 9.024 9.853 9.96 ;
     RECT  9.385 24.48 9.893 26.376 ;
     RECT  9.425 5.712 9.929 7.224 ;
     RECT  8.104 28.752 9.961 28.776 ;
     RECT  9.929 5.712 10.109 6.408 ;
     RECT  9.641 15.936 10.109 16.008 ;
     RECT  9.641 11.952 10.145 14.808 ;
     RECT  10.145 11.952 10.177 11.976 ;
     RECT  9.565 34.656 10.357 34.68 ;
     RECT  8.705 18.96 10.393 18.984 ;
     RECT  9.853 8.4 10.433 9.96 ;
     RECT  9.749 17.616 10.505 17.64 ;
     RECT  10.433 8.976 10.537 9.96 ;
     RECT  10.177 11.424 10.537 11.976 ;
     RECT  10.393 18.912 10.573 18.984 ;
     RECT  8.597 21.36 10.573 21.384 ;
     RECT  9.893 24.72 10.573 26.376 ;
     RECT  10.573 21.36 10.613 21.624 ;
     RECT  10.145 13.056 10.645 14.808 ;
     RECT  10.109 15.936 10.645 15.96 ;
     RECT  10.109 5.712 10.649 5.976 ;
     RECT  10.537 8.976 10.649 11.976 ;
     RECT  10.645 13.056 10.721 15.96 ;
     RECT  10.721 13.056 10.937 15.816 ;
     RECT  10.573 18.912 10.973 19.032 ;
     RECT  10.649 5.952 11.081 5.976 ;
     RECT  8.104 32.832 11.113 32.856 ;
     RECT  10.357 34.176 11.149 34.68 ;
     RECT  10.649 9.648 11.153 11.976 ;
     RECT  11.153 9.648 11.189 9.672 ;
     RECT  10.937 13.056 11.225 13.848 ;
     RECT  11.153 10.704 11.261 11.976 ;
     RECT  11.225 13.056 11.261 13.512 ;
     RECT  10.573 24.72 11.581 27.192 ;
     RECT  11.261 13.056 11.585 13.32 ;
     RECT  8.104 31.104 11.689 31.704 ;
     RECT  11.113 32.832 11.689 33.144 ;
     RECT  10.933 22.8 11.693 22.824 ;
     RECT  11.581 24.384 11.833 27.192 ;
     RECT  8.104 36.288 11.941 36.312 ;
     RECT  11.257 6.672 12.017 6.696 ;
     RECT  11.833 24.384 12.085 27.72 ;
     RECT  9.961 28.752 12.085 28.824 ;
     RECT  11.585 13.152 12.089 13.32 ;
     RECT  11.689 31.104 12.229 33.144 ;
     RECT  11.149 34.176 12.229 35.016 ;
     RECT  11.905 23.28 12.337 23.304 ;
     RECT  12.085 24.384 12.337 28.824 ;
     RECT  11.473 8.448 12.445 8.472 ;
     RECT  10.613 21.6 12.733 21.624 ;
     RECT  12.229 31.104 12.805 35.016 ;
     RECT  12.089 13.296 13.093 13.32 ;
     RECT  10.973 19.008 13.129 19.032 ;
     RECT  12.337 23.28 13.165 28.824 ;
     RECT  12.193 6.096 13.208 6.12 ;
     RECT  12.445 8.448 13.208 10.344 ;
     RECT  11.261 11.952 13.208 11.976 ;
     RECT  13.093 13.056 13.208 13.32 ;
     RECT  10.937 14.832 13.208 15.816 ;
     RECT  13.057 16.8 13.208 16.824 ;
     RECT  13.129 18.72 13.208 19.032 ;
     RECT  12.733 21.504 13.208 21.624 ;
     RECT  13.165 23.28 13.208 29.016 ;
     RECT  12.805 30.336 13.208 35.016 ;
     RECT  11.941 36.288 13.208 36.888 ;
     RECT  13.208 2.148 13.312 73.452 ;
     RECT  13.312 2.418 13.504 73.182 ;
     RECT  13.504 18.528 13.637 19.128 ;
     RECT  13.504 12.336 13.673 13.32 ;
     RECT  13.673 13.296 13.709 13.32 ;
     RECT  13.504 15.696 13.709 16.92 ;
     RECT  13.504 21.504 13.853 21.528 ;
     RECT  13.504 10.32 13.925 10.344 ;
     RECT  13.504 6.096 13.961 6.12 ;
     RECT  4.021 75.456 14.213 75.48 ;
     RECT  13.637 19.008 14.357 19.128 ;
     RECT  13.504 24.24 14.605 29.016 ;
     RECT  13.504 30.336 14.605 36.888 ;
     RECT  14.605 24.24 15.037 36.888 ;
     RECT  14.641 18.816 15.401 18.84 ;
     RECT  14.929 20.448 15.437 20.472 ;
     RECT  15.289 47.328 15.761 47.352 ;
     RECT  15.361 39.552 16.369 39.576 ;
     RECT  16.369 38.688 16.477 39.576 ;
     RECT  15.721 21.984 17.053 22.008 ;
     RECT  16.477 38.688 17.053 40.104 ;
     RECT  14.785 41.232 17.053 41.256 ;
     RECT  17.053 21.984 17.089 22.104 ;
     RECT  17.089 43.344 17.161 43.368 ;
     RECT  15.037 24.24 17.197 37.368 ;
     RECT  17.089 21.984 17.485 22.2 ;
     RECT  17.053 38.688 17.485 41.256 ;
     RECT  17.161 42.72 17.485 43.368 ;
     RECT  17.197 24.144 18.061 37.368 ;
     RECT  17.485 38.688 18.061 43.368 ;
     RECT  18.061 24.144 18.205 43.368 ;
     RECT  18.205 24.144 18.349 43.56 ;
     RECT  13.709 15.696 18.608 15.72 ;
     RECT  17.485 21.408 18.608 22.2 ;
     RECT  18.349 23.568 18.608 43.56 ;
     RECT  18.608 2.148 18.712 73.452 ;
     RECT  18.712 2.418 18.904 73.182 ;
     RECT  18.904 21.408 20.005 22.2 ;
     RECT  20.005 20.784 21.121 22.2 ;
     RECT  21.121 20.784 22.381 22.392 ;
     RECT  18.904 23.424 22.381 44.184 ;
     RECT  22.633 18.816 22.745 18.84 ;
     RECT  22.381 20.784 23.4 44.184 ;
     RECT  18.904 15.696 24.008 15.72 ;
     RECT  23.4 20.784 24.008 52.2 ;
     RECT  24.008 2.148 24.112 52.2 ;
     RECT  24.008 54.528 24.112 73.452 ;
     RECT  24.112 54.528 24.2 73.182 ;
     RECT  24.112 2.418 24.304 52.2 ;
     RECT  24.2 54.258 24.304 73.182 ;
     RECT  24.304 15.696 29.408 15.72 ;
     RECT  24.304 20.784 29.408 52.2 ;
     RECT  29.408 2.148 29.512 52.2 ;
     RECT  29.408 54.528 29.512 73.452 ;
     RECT  29.512 54.528 29.6 73.182 ;
     RECT  29.512 2.418 29.704 52.2 ;
     RECT  29.6 54.258 29.704 73.182 ;
     RECT  29.704 15.696 34.808 15.72 ;
     RECT  29.704 20.784 34.808 52.2 ;
     RECT  34.808 2.148 34.912 52.2 ;
     RECT  34.808 54.528 34.912 73.452 ;
     RECT  34.912 54.528 35 73.182 ;
     RECT  34.912 2.418 35.104 52.2 ;
     RECT  35 54.258 35.104 73.182 ;
     RECT  35.104 15.696 40.208 15.72 ;
     RECT  35.104 20.784 40.208 52.2 ;
     RECT  40.208 2.148 40.312 52.2 ;
     RECT  40.208 54.528 40.312 73.452 ;
     RECT  40.312 54.528 40.4 73.182 ;
     RECT  40.312 2.418 40.504 52.2 ;
     RECT  40.4 54.258 40.504 73.182 ;
     RECT  40.504 15.696 45.608 15.72 ;
     RECT  40.504 20.784 45.608 52.2 ;
     RECT  45.608 2.148 45.712 52.2 ;
     RECT  45.608 54.528 45.712 73.452 ;
     RECT  45.712 54.528 45.8 73.182 ;
     RECT  45.712 2.418 45.904 52.2 ;
     RECT  45.8 54.258 45.904 73.182 ;
     RECT  45.904 15.696 51.008 15.72 ;
     RECT  45.904 20.784 51.008 52.2 ;
     RECT  51.008 2.148 51.112 52.2 ;
     RECT  51.008 54.528 51.112 73.452 ;
     RECT  51.112 54.528 51.2 73.182 ;
     RECT  51.112 2.418 51.304 52.2 ;
     RECT  51.2 54.258 51.304 73.182 ;
     RECT  51.304 15.696 56.408 15.72 ;
     RECT  51.304 20.784 56.408 52.2 ;
     RECT  56.408 2.148 56.512 52.2 ;
     RECT  56.408 54.528 56.512 73.452 ;
     RECT  56.512 54.528 56.6 73.182 ;
     RECT  56.512 2.418 56.704 52.2 ;
     RECT  56.6 54.258 56.704 73.182 ;
     RECT  56.704 18.96 60.217 18.984 ;
     RECT  56.704 15.696 61.808 15.72 ;
     RECT  60.217 18.96 61.808 19.8 ;
     RECT  56.704 20.784 61.808 52.2 ;
     RECT  61.808 2.148 61.912 52.2 ;
     RECT  61.808 54.528 61.912 73.452 ;
     RECT  61.912 54.528 62 73.182 ;
     RECT  61.912 2.418 62.104 52.2 ;
     RECT  62 54.258 62.104 73.182 ;
     RECT  62.104 15.696 67.208 15.72 ;
     RECT  62.104 18.96 67.208 19.8 ;
     RECT  62.104 20.784 67.208 52.2 ;
     RECT  67.208 2.148 67.312 52.2 ;
     RECT  67.208 54.528 67.312 73.452 ;
     RECT  67.312 54.528 67.4 73.182 ;
     RECT  67.312 2.418 67.504 52.2 ;
     RECT  67.4 54.258 67.504 73.182 ;
     RECT  67.504 15.696 72.608 15.72 ;
     RECT  67.504 18.96 72.608 19.8 ;
     RECT  67.504 20.784 72.608 52.2 ;
     RECT  72.608 2.148 72.712 52.2 ;
     RECT  72.608 54.528 72.712 73.452 ;
     RECT  72.712 54.528 72.8 73.182 ;
     RECT  72.712 2.418 72.904 52.2 ;
     RECT  72.8 54.258 72.904 73.182 ;
     RECT  72.904 18.96 75.193 19.8 ;
     RECT  72.904 20.784 75.193 52.2 ;
     RECT  72.904 15.696 77.245 15.72 ;
     RECT  77.245 15.696 77.533 15.816 ;
     RECT  77.533 15.552 78.008 15.816 ;
     RECT  75.193 18.96 78.008 52.2 ;
     RECT  78.008 2.148 78.112 52.2 ;
     RECT  78.008 54.528 78.112 73.452 ;
     RECT  78.112 54.528 78.2 73.182 ;
     RECT  78.112 2.418 78.304 52.2 ;
     RECT  78.2 54.258 78.304 73.182 ;
     RECT  78.304 15.552 78.689 15.816 ;
     RECT  78.689 15.696 83.408 15.816 ;
     RECT  78.304 18.96 83.408 52.2 ;
     RECT  83.408 2.148 83.512 52.2 ;
     RECT  83.408 54.528 83.512 73.452 ;
     RECT  83.512 54.528 83.6 73.182 ;
     RECT  83.512 2.418 83.704 52.2 ;
     RECT  83.6 54.258 83.704 73.182 ;
     RECT  83.704 15.696 88.808 15.816 ;
     RECT  83.704 18.96 88.808 52.2 ;
     RECT  88.808 2.148 88.912 52.2 ;
     RECT  88.808 54.528 88.912 73.452 ;
     RECT  88.912 54.528 89 73.182 ;
     RECT  88.912 2.418 89.104 52.2 ;
     RECT  89 54.258 89.104 73.182 ;
     RECT  89.104 15.696 94.208 15.816 ;
     RECT  89.104 18.96 94.208 52.2 ;
     RECT  94.208 2.148 94.312 52.2 ;
     RECT  94.208 54.528 94.312 73.452 ;
     RECT  94.312 54.528 94.4 73.182 ;
     RECT  94.312 2.418 94.504 52.2 ;
     RECT  94.4 54.258 94.504 73.182 ;
     RECT  94.504 15.696 98.593 15.816 ;
     RECT  98.449 14.64 99.529 14.664 ;
     RECT  98.593 15.696 99.529 16.68 ;
     RECT  99.529 14.64 99.608 16.68 ;
     RECT  94.504 18.96 99.608 52.2 ;
     RECT  99.608 2.148 99.712 52.2 ;
     RECT  99.608 54.528 99.712 73.452 ;
     RECT  99.712 54.528 99.8 73.182 ;
     RECT  99.712 2.418 99.904 52.2 ;
     RECT  99.8 54.258 99.904 73.182 ;
     RECT  101.041 17.04 101.189 17.064 ;
     RECT  99.904 14.64 105.008 14.664 ;
     RECT  99.904 15.696 105.008 15.816 ;
     RECT  99.904 18.96 105.008 52.2 ;
     RECT  105.008 2.148 105.112 52.2 ;
     RECT  105.008 54.528 105.112 73.452 ;
     RECT  105.112 54.528 105.2 73.182 ;
     RECT  105.112 2.418 105.304 52.2 ;
     RECT  105.2 54.258 105.304 73.182 ;
     RECT  105.304 14.64 106.585 14.664 ;
     RECT  106.585 14.496 106.625 14.664 ;
     RECT  106.625 14.496 110.408 14.52 ;
     RECT  105.304 15.696 110.408 15.816 ;
     RECT  105.304 18.96 110.408 52.2 ;
     RECT  110.408 2.148 110.512 52.2 ;
     RECT  110.408 54.528 110.512 73.452 ;
     RECT  110.512 54.528 110.6 73.182 ;
     RECT  110.512 2.418 110.704 52.2 ;
     RECT  110.6 54.258 110.704 73.182 ;
     RECT  110.704 14.496 111.665 14.52 ;
     RECT  110.704 15.792 112.781 15.816 ;
     RECT  111.913 14.448 113.641 14.472 ;
     RECT  113.641 14.112 113.681 14.472 ;
     RECT  113.681 14.112 115.808 14.136 ;
     RECT  112.957 15.744 115.808 15.768 ;
     RECT  110.704 18.96 115.808 52.2 ;
     RECT  115.808 2.148 115.912 52.2 ;
     RECT  115.808 54.528 115.912 73.452 ;
     RECT  115.912 54.528 116 73.182 ;
     RECT  115.912 2.418 116.104 52.2 ;
     RECT  116 54.258 116.104 73.182 ;
     RECT  116.104 14.112 117.205 14.136 ;
     RECT  117.205 13.68 117.245 14.136 ;
     RECT  117.245 13.68 118.217 13.704 ;
     RECT  116.104 15.744 121.208 15.768 ;
     RECT  116.104 18.96 121.208 52.2 ;
     RECT  121.208 2.148 121.312 52.2 ;
     RECT  121.208 54.528 121.312 73.452 ;
     RECT  121.312 54.528 121.4 73.182 ;
     RECT  121.312 2.418 121.504 52.2 ;
     RECT  121.4 54.258 121.504 73.182 ;
     RECT  121.504 4.704 126.608 4.728 ;
     RECT  121.504 15.744 126.608 15.768 ;
     RECT  121.504 18.96 126.608 52.2 ;
     RECT  126.608 2.148 126.712 52.2 ;
     RECT  126.608 54.528 126.712 73.452 ;
     RECT  126.712 54.528 126.8 73.182 ;
     RECT  126.712 2.418 126.904 52.2 ;
     RECT  126.8 54.258 126.904 73.182 ;
     RECT  126.904 18.96 129.413 52.2 ;
     RECT  126.904 15.744 131.065 15.768 ;
     RECT  129.413 18.96 131.465 21.48 ;
     RECT  126.904 4.704 132.008 4.728 ;
     RECT  131.065 15.264 132.008 15.768 ;
     RECT  131.465 18.96 132.008 21.432 ;
     RECT  132.008 2.148 132.112 21.432 ;
     RECT  132.008 54.528 132.112 73.452 ;
     RECT  132.112 54.528 132.2 73.182 ;
     RECT  132.112 2.418 132.304 21.432 ;
     RECT  132.2 54.258 132.304 73.182 ;
     RECT  132.304 15.264 134.485 15.768 ;
     RECT  132.304 18.96 135.101 21.432 ;
     RECT  132.304 4.704 137.408 4.728 ;
     RECT  134.485 15.168 137.408 15.768 ;
     RECT  135.101 18.96 137.408 21.384 ;
     RECT  137.408 2.148 137.512 21.384 ;
     RECT  137.408 54.528 137.512 73.452 ;
     RECT  137.512 54.528 137.6 73.182 ;
     RECT  137.512 2.418 137.704 21.384 ;
     RECT  137.6 54.258 137.704 73.182 ;
     RECT  137.704 4.704 142.808 4.728 ;
     RECT  137.704 15.168 142.808 15.768 ;
     RECT  137.704 18.96 142.808 21.384 ;
     RECT  142.808 2.148 142.912 21.384 ;
     RECT  142.808 54.528 142.912 73.452 ;
     RECT  142.912 54.528 143 73.182 ;
     RECT  142.912 2.418 143.104 21.384 ;
     RECT  143 54.258 143.104 73.182 ;
     RECT  143.104 15.168 147.517 15.768 ;
     RECT  143.104 18.96 147.881 21.384 ;
     RECT  143.104 4.704 148.208 4.728 ;
     RECT  147.517 15.168 148.208 16.008 ;
     RECT  147.881 18.96 148.208 20.808 ;
     RECT  148.208 2.148 148.312 20.808 ;
     RECT  148.208 54.528 148.312 73.452 ;
     RECT  148.312 54.528 148.4 73.182 ;
     RECT  148.312 2.418 148.504 20.808 ;
     RECT  148.4 54.258 148.504 73.182 ;
     RECT  148.504 18.96 153.497 20.808 ;
     RECT  148.504 4.704 153.608 4.728 ;
     RECT  148.504 15.168 153.608 16.008 ;
     RECT  153.497 18.96 153.608 20.262 ;
     RECT  153.608 2.148 153.712 20.262 ;
     RECT  153.608 54.528 153.712 73.452 ;
     RECT  153.712 54.528 153.8 73.182 ;
     RECT  153.712 2.418 153.904 20.262 ;
     RECT  153.8 54.258 153.904 73.182 ;
     RECT  153.904 4.704 159.008 4.728 ;
     RECT  153.904 15.168 159.008 16.008 ;
     RECT  153.904 18.96 159.008 20.04 ;
     RECT  159.008 2.148 159.112 20.04 ;
     RECT  159.008 54.528 159.112 73.452 ;
     RECT  159.112 2.418 159.2 20.04 ;
     RECT  159.112 54.528 159.2 73.182 ;
     RECT  159.2 2.418 159.304 20.262 ;
     RECT  159.2 54.258 159.304 73.182 ;
     RECT  159.304 4.704 164.408 4.728 ;
     RECT  159.304 15.168 164.408 16.008 ;
     RECT  159.304 18.96 164.408 20.04 ;
     RECT  164.408 2.148 164.512 20.04 ;
     RECT  164.408 54.528 164.512 73.452 ;
     RECT  164.512 2.418 164.6 20.04 ;
     RECT  164.512 54.528 164.6 73.182 ;
     RECT  164.6 2.418 164.704 20.262 ;
     RECT  164.6 54.258 164.704 73.182 ;
     RECT  164.704 4.704 169.808 4.728 ;
     RECT  164.704 15.168 169.808 16.008 ;
     RECT  164.704 18.96 169.808 20.04 ;
     RECT  169.808 2.148 169.912 20.04 ;
     RECT  169.808 54.528 169.912 73.452 ;
     RECT  169.912 2.418 170 20.04 ;
     RECT  169.912 54.528 170 73.182 ;
     RECT  170 2.418 170.104 20.262 ;
     RECT  170 54.258 170.104 73.182 ;
     RECT  170.104 4.704 175.208 4.728 ;
     RECT  170.104 15.168 175.208 16.008 ;
     RECT  170.104 18.96 175.208 20.04 ;
     RECT  175.208 2.148 175.312 20.04 ;
     RECT  175.208 54.528 175.312 73.452 ;
     RECT  175.312 2.418 175.4 20.04 ;
     RECT  175.312 54.528 175.4 73.182 ;
     RECT  175.4 2.418 175.504 20.262 ;
     RECT  175.4 54.258 175.504 73.182 ;
     RECT  175.504 18.96 176.857 20.04 ;
     RECT  175.504 4.704 180.608 4.728 ;
     RECT  175.504 15.168 180.608 16.008 ;
     RECT  176.857 18.672 180.608 20.04 ;
     RECT  180.608 2.148 180.712 20.04 ;
     RECT  180.608 54.528 180.712 73.452 ;
     RECT  180.712 2.418 180.8 20.04 ;
     RECT  180.712 54.528 180.8 73.182 ;
     RECT  180.8 2.418 180.904 20.262 ;
     RECT  180.8 54.258 180.904 73.182 ;
     RECT  180.904 18.672 183.841 20.04 ;
     RECT  183.841 18.144 184.709 20.04 ;
     RECT  180.904 4.704 186.008 4.728 ;
     RECT  180.904 15.168 186.008 16.008 ;
     RECT  184.709 18.144 186.008 18.984 ;
     RECT  184.709 20.016 186.008 20.04 ;
     RECT  186.008 2.148 186.112 20.04 ;
     RECT  186.008 54.528 186.112 73.452 ;
     RECT  186.112 2.418 186.2 20.04 ;
     RECT  186.112 54.528 186.2 73.182 ;
     RECT  186.2 2.418 186.304 20.262 ;
     RECT  186.2 54.258 186.304 73.182 ;
     RECT  186.304 20.016 190.465 20.04 ;
     RECT  186.304 4.704 191.408 4.728 ;
     RECT  186.304 15.168 191.408 16.008 ;
     RECT  186.304 18.144 191.408 18.984 ;
     RECT  190.465 20.016 191.408 20.136 ;
     RECT  191.408 2.148 191.512 20.136 ;
     RECT  191.408 54.528 191.512 73.452 ;
     RECT  191.512 2.418 191.6 20.136 ;
     RECT  191.512 54.528 191.6 73.182 ;
     RECT  191.6 2.418 191.704 20.262 ;
     RECT  191.6 54.258 191.704 73.182 ;
     RECT  191.704 20.064 192.485 20.136 ;
     RECT  191.704 4.704 196.808 4.728 ;
     RECT  191.704 15.168 196.808 16.008 ;
     RECT  191.704 18.144 196.808 18.984 ;
     RECT  192.485 20.064 196.808 20.088 ;
     RECT  196.808 2.148 196.912 20.088 ;
     RECT  196.808 54.528 196.912 73.452 ;
     RECT  196.912 2.418 197 20.088 ;
     RECT  196.912 54.528 197 73.182 ;
     RECT  197 2.418 197.104 20.262 ;
     RECT  197 54.258 197.104 73.182 ;
     RECT  129.413 22.464 197.376 52.2 ;
     RECT  197.376 23.136 197.561 44.088 ;
     RECT  197.561 23.136 197.597 37.944 ;
     RECT  197.597 31.872 197.633 33.048 ;
     RECT  197.597 34.944 197.633 37.944 ;
     RECT  197.633 32.928 197.705 33.048 ;
     RECT  197.561 41.088 199.073 44.088 ;
     RECT  199.073 41.088 199.181 43.992 ;
     RECT  199.181 41.088 199.901 42.84 ;
     RECT  199.901 42.24 199.937 42.84 ;
     RECT  199.937 42.336 200.117 42.84 ;
     RECT  200.117 42.816 200.261 42.84 ;
     RECT  197.104 4.704 200.473 4.728 ;
     RECT  200.473 4.464 200.693 4.728 ;
     RECT  200.693 4.464 202.208 4.488 ;
     RECT  197.104 15.168 202.208 16.008 ;
     RECT  197.104 18.144 202.208 18.984 ;
     RECT  197.104 20.064 202.208 20.088 ;
     RECT  197.597 23.136 202.208 28.728 ;
     RECT  202.208 2.148 202.312 73.452 ;
     RECT  202.312 2.418 202.504 73.182 ;
     RECT  202.504 4.368 207.608 4.392 ;
     RECT  202.504 15.168 207.608 16.008 ;
     RECT  202.504 18.144 207.608 18.984 ;
     RECT  202.504 20.064 207.608 20.088 ;
     RECT  202.504 23.136 207.608 28.728 ;
     RECT  207.608 2.148 207.712 73.452 ;
     RECT  207.712 2.418 207.904 73.182 ;
     RECT  207.904 23.136 210.125 28.728 ;
     RECT  210.125 23.136 210.341 28.248 ;
     RECT  207.904 15.168 210.841 16.008 ;
     RECT  210.841 15.168 211.021 16.536 ;
     RECT  207.904 18.144 211.021 18.984 ;
     RECT  211.129 6 211.165 6.024 ;
     RECT  211.021 15.168 211.237 18.984 ;
     RECT  211.165 6 211.349 6.84 ;
     RECT  211.237 14.784 211.637 18.984 ;
     RECT  210.341 23.232 211.669 28.248 ;
     RECT  211.669 23.136 211.849 28.248 ;
     RECT  211.637 15.216 211.885 18.984 ;
     RECT  207.904 20.064 211.885 20.088 ;
     RECT  211.309 13.152 211.921 13.176 ;
     RECT  211.129 10.56 212.137 10.584 ;
     RECT  212.137 12.048 212.281 12.072 ;
     RECT  211.921 13.152 212.281 13.608 ;
     RECT  210.949 21.072 212.317 21.096 ;
     RECT  211.849 22.368 212.317 28.248 ;
     RECT  211.885 15.216 212.677 20.088 ;
     RECT  212.137 10.08 212.713 10.584 ;
     RECT  212.677 14.976 212.929 20.088 ;
     RECT  207.904 4.368 213.008 4.392 ;
     RECT  211.349 6 213.008 6.024 ;
     RECT  212.137 7.344 213.008 7.368 ;
     RECT  212.713 10.08 213.008 10.68 ;
     RECT  212.281 12.048 213.008 13.608 ;
     RECT  212.929 14.64 213.008 20.088 ;
     RECT  212.317 21.072 213.008 28.248 ;
     RECT  213.008 2.148 213.112 73.452 ;
     RECT  213.112 2.418 213.304 73.182 ;
     RECT  213.304 10.08 213.473 28.248 ;
     RECT  213.473 10.656 213.833 28.248 ;
     RECT  213.833 19.248 213.905 28.248 ;
     RECT  213.304 6 214.481 6.024 ;
     RECT  213.833 10.656 214.625 18.168 ;
     RECT  214.625 10.896 214.877 18.168 ;
     RECT  213.905 19.248 214.985 27.864 ;
     RECT  213.304 4.368 215.053 4.392 ;
     RECT  214.877 16.512 215.089 18.168 ;
     RECT  214.985 19.248 215.089 24.936 ;
     RECT  215.089 16.512 215.201 24.936 ;
     RECT  215.201 16.944 215.453 24.936 ;
     RECT  214.877 10.896 215.525 13.848 ;
     RECT  215.053 4.368 215.597 4.536 ;
     RECT  215.525 10.896 215.597 13.608 ;
     RECT  214.985 26.256 215.849 27.864 ;
     RECT  215.453 16.944 215.921 24.792 ;
     RECT  215.921 16.944 216.029 23.976 ;
     RECT  215.597 11.616 216.137 13.56 ;
     RECT  214.877 15.168 216.137 15.48 ;
     RECT  216.137 15.216 216.169 15.48 ;
     RECT  216.029 16.944 216.169 23.448 ;
     RECT  216.137 13.536 216.173 13.56 ;
     RECT  216.169 15.216 216.245 23.448 ;
     RECT  216.245 15.216 216.281 23.4 ;
     RECT  216.281 17.616 216.317 23.4 ;
     RECT  215.597 4.368 216.353 4.392 ;
     RECT  216.137 11.616 216.425 12.36 ;
     RECT  215.849 26.784 216.461 27.672 ;
     RECT  216.425 11.616 216.565 11.928 ;
     RECT  216.565 10.848 216.677 11.928 ;
     RECT  216.281 15.216 216.677 16.536 ;
     RECT  216.677 15.36 216.857 16.536 ;
     RECT  216.461 26.784 216.965 27.336 ;
     RECT  216.677 11.712 217.289 11.928 ;
     RECT  217.289 11.808 217.537 11.928 ;
     RECT  217.537 11.808 217.681 12.6 ;
     RECT  217.249 6.24 217.685 6.264 ;
     RECT  216.317 17.616 217.685 23.304 ;
     RECT  217.681 11.808 217.753 12.696 ;
     RECT  217.717 13.824 217.753 13.848 ;
     RECT  216.857 15.36 217.753 16.296 ;
     RECT  217.685 21.888 217.789 23.304 ;
     RECT  217.753 7.008 218.293 7.128 ;
     RECT  217.753 11.808 218.293 16.296 ;
     RECT  217.685 17.616 218.293 20.856 ;
     RECT  218.293 5.088 218.329 5.112 ;
     RECT  218.293 17.568 218.761 20.856 ;
     RECT  218.293 11.616 218.797 16.296 ;
     RECT  218.761 17.376 218.797 20.856 ;
     RECT  218.329 5.088 218.833 5.4 ;
     RECT  218.293 9.792 218.833 9.816 ;
     RECT  218.797 11.616 218.833 20.856 ;
     RECT  217.789 21.888 218.833 23.736 ;
     RECT  218.797 26.4 218.833 26.424 ;
     RECT  218.833 9.792 218.869 10.392 ;
     RECT  218.833 11.616 218.869 23.736 ;
     RECT  218.293 7.008 219.373 7.512 ;
     RECT  218.797 24.768 219.373 24.792 ;
     RECT  218.833 5.088 219.409 5.784 ;
     RECT  219.373 7.008 219.409 7.608 ;
     RECT  218.833 26.208 219.409 26.808 ;
     RECT  218.869 9.696 220.201 10.392 ;
     RECT  218.833 4.032 220.284 4.056 ;
     RECT  219.409 5.088 220.284 5.88 ;
     RECT  219.409 6.912 220.284 7.608 ;
     RECT  218.833 8.64 220.284 8.664 ;
     RECT  220.201 9.696 220.284 10.488 ;
     RECT  218.869 11.52 220.284 23.736 ;
     RECT  219.373 24.768 220.284 25.08 ;
     RECT  219.409 26.112 220.284 26.808 ;
    LAYER M5 ;
     RECT  2.4 2.137 2.52 2.151 ;
     RECT  7.8 2.137 7.92 2.151 ;
     RECT  13.2 2.137 13.32 2.151 ;
     RECT  18.6 2.137 18.72 2.151 ;
     RECT  24 2.137 24.12 2.151 ;
     RECT  29.4 2.137 29.52 2.151 ;
     RECT  34.8 2.137 34.92 2.151 ;
     RECT  40.2 2.137 40.32 2.151 ;
     RECT  45.6 2.137 45.72 2.151 ;
     RECT  51 2.137 51.12 2.151 ;
     RECT  56.4 2.137 56.52 2.151 ;
     RECT  61.8 2.137 61.92 2.151 ;
     RECT  67.2 2.137 67.32 2.151 ;
     RECT  72.6 2.137 72.72 2.151 ;
     RECT  78 2.137 78.12 2.151 ;
     RECT  83.4 2.137 83.52 2.151 ;
     RECT  88.8 2.137 88.92 2.151 ;
     RECT  94.2 2.137 94.32 2.151 ;
     RECT  99.6 2.137 99.72 2.151 ;
     RECT  105 2.137 105.12 2.151 ;
     RECT  110.4 2.137 110.52 2.151 ;
     RECT  115.8 2.137 115.92 2.151 ;
     RECT  121.2 2.137 121.32 2.151 ;
     RECT  126.6 2.137 126.72 2.151 ;
     RECT  132 2.137 132.12 2.151 ;
     RECT  137.4 2.137 137.52 2.151 ;
     RECT  142.8 2.137 142.92 2.151 ;
     RECT  148.2 2.137 148.32 2.151 ;
     RECT  153.6 2.137 153.72 2.151 ;
     RECT  159 2.137 159.12 2.151 ;
     RECT  164.4 2.137 164.52 2.151 ;
     RECT  169.8 2.137 169.92 2.151 ;
     RECT  175.2 2.137 175.32 2.151 ;
     RECT  180.6 2.137 180.72 2.151 ;
     RECT  186 2.137 186.12 2.151 ;
     RECT  191.4 2.137 191.52 2.151 ;
     RECT  196.8 2.137 196.92 2.151 ;
     RECT  202.2 2.137 202.32 2.151 ;
     RECT  207.6 2.137 207.72 2.151 ;
     RECT  213 2.137 213.12 2.151 ;
     RECT  2.4 2.151 2.712 73.449 ;
     RECT  7.8 2.151 8.112 73.449 ;
     RECT  13.2 2.151 13.512 73.449 ;
     RECT  18.6 2.151 18.912 73.449 ;
     RECT  24 2.151 24.312 73.449 ;
     RECT  29.4 2.151 29.712 73.449 ;
     RECT  34.8 2.151 35.112 73.449 ;
     RECT  40.2 2.151 40.512 73.449 ;
     RECT  45.6 2.151 45.912 73.449 ;
     RECT  51 2.151 51.312 73.449 ;
     RECT  56.4 2.151 56.712 73.449 ;
     RECT  61.8 2.151 62.112 73.449 ;
     RECT  67.2 2.151 67.512 73.449 ;
     RECT  72.6 2.151 72.912 73.449 ;
     RECT  78 2.151 78.312 73.449 ;
     RECT  83.4 2.151 83.712 73.449 ;
     RECT  88.8 2.151 89.112 73.449 ;
     RECT  94.2 2.151 94.512 73.449 ;
     RECT  99.6 2.151 99.912 73.449 ;
     RECT  105 2.151 105.312 73.449 ;
     RECT  110.4 2.151 110.712 73.449 ;
     RECT  115.8 2.151 116.112 73.449 ;
     RECT  121.2 2.151 121.512 73.449 ;
     RECT  126.6 2.151 126.912 73.449 ;
     RECT  132 2.151 132.312 73.449 ;
     RECT  137.4 2.151 137.712 73.449 ;
     RECT  142.8 2.151 143.112 73.449 ;
     RECT  148.2 2.151 148.512 73.449 ;
     RECT  153.6 2.151 153.912 73.449 ;
     RECT  159 2.151 159.312 73.449 ;
     RECT  164.4 2.151 164.712 73.449 ;
     RECT  169.8 2.151 170.112 73.449 ;
     RECT  175.2 2.151 175.512 73.449 ;
     RECT  180.6 2.151 180.912 73.449 ;
     RECT  186 2.151 186.312 73.449 ;
     RECT  191.4 2.151 191.712 73.449 ;
     RECT  196.8 2.151 197.112 73.449 ;
     RECT  202.2 2.151 202.512 73.449 ;
     RECT  207.6 2.151 207.912 73.449 ;
     RECT  213 2.151 213.312 73.449 ;
     RECT  2.4 73.449 2.52 73.463 ;
     RECT  7.8 73.449 7.92 73.463 ;
     RECT  13.2 73.449 13.32 73.463 ;
     RECT  18.6 73.449 18.72 73.463 ;
     RECT  24 73.449 24.12 73.463 ;
     RECT  29.4 73.449 29.52 73.463 ;
     RECT  34.8 73.449 34.92 73.463 ;
     RECT  40.2 73.449 40.32 73.463 ;
     RECT  45.6 73.449 45.72 73.463 ;
     RECT  51 73.449 51.12 73.463 ;
     RECT  56.4 73.449 56.52 73.463 ;
     RECT  61.8 73.449 61.92 73.463 ;
     RECT  67.2 73.449 67.32 73.463 ;
     RECT  72.6 73.449 72.72 73.463 ;
     RECT  78 73.449 78.12 73.463 ;
     RECT  83.4 73.449 83.52 73.463 ;
     RECT  88.8 73.449 88.92 73.463 ;
     RECT  94.2 73.449 94.32 73.463 ;
     RECT  99.6 73.449 99.72 73.463 ;
     RECT  105 73.449 105.12 73.463 ;
     RECT  110.4 73.449 110.52 73.463 ;
     RECT  115.8 73.449 115.92 73.463 ;
     RECT  121.2 73.449 121.32 73.463 ;
     RECT  126.6 73.449 126.72 73.463 ;
     RECT  132 73.449 132.12 73.463 ;
     RECT  137.4 73.449 137.52 73.463 ;
     RECT  142.8 73.449 142.92 73.463 ;
     RECT  148.2 73.449 148.32 73.463 ;
     RECT  153.6 73.449 153.72 73.463 ;
     RECT  159 73.449 159.12 73.463 ;
     RECT  164.4 73.449 164.52 73.463 ;
     RECT  169.8 73.449 169.92 73.463 ;
     RECT  175.2 73.449 175.32 73.463 ;
     RECT  180.6 73.449 180.72 73.463 ;
     RECT  186 73.449 186.12 73.463 ;
     RECT  191.4 73.449 191.52 73.463 ;
     RECT  196.8 73.449 196.92 73.463 ;
     RECT  202.2 73.449 202.32 73.463 ;
     RECT  207.6 73.449 207.72 73.463 ;
     RECT  213 73.449 213.12 73.463 ;
  END
END dsfd_vm_static_bank128_E
END LIBRARY
